VERSION 5.8 ;
BUSBITCHARS "[]" ;
DIVIDERCHAR "/" ;

PROPERTYDEFINITIONS
  MACRO CatenaDesignType STRING ;
  MACRO oaTaper STRING ;
END PROPERTYDEFINITIONS

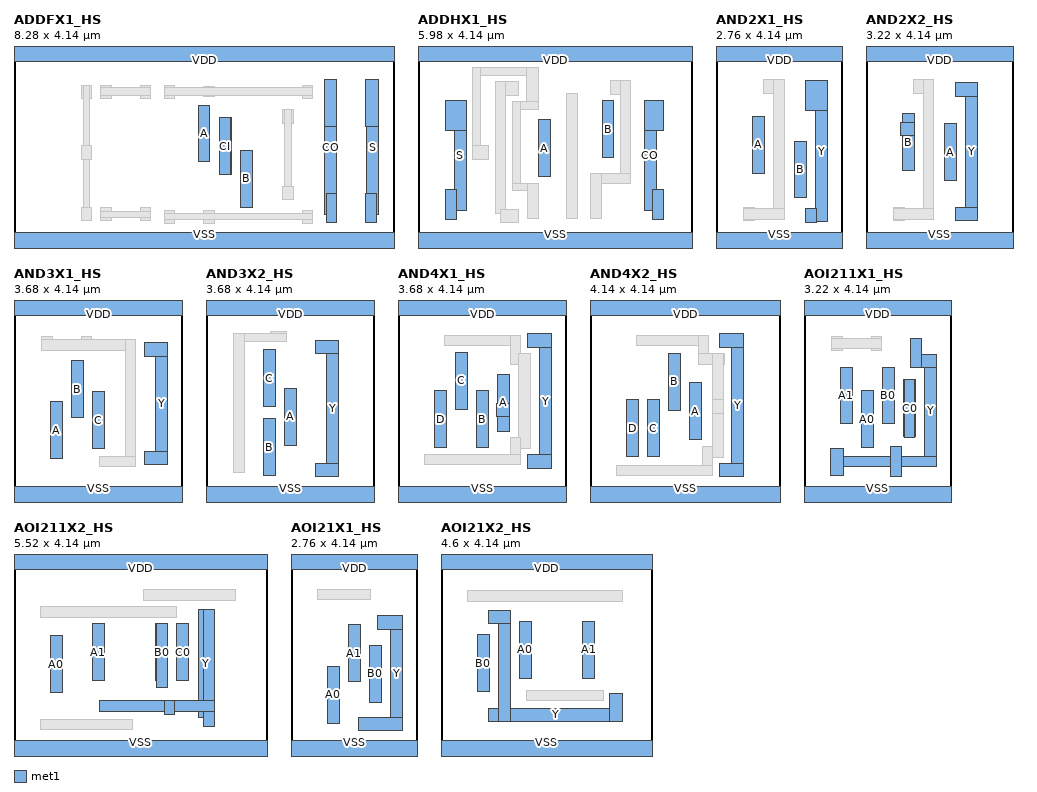
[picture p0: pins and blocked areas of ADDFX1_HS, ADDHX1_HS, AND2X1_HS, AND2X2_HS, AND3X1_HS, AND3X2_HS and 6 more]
MACRO ADDFX1_HS
  CLASS CORE ;
  ORIGIN 0 0 ;
  FOREIGN ADDFX1_HS 0 0 ;
  SIZE 8.28 BY 4.14 ;
  SYMMETRY X Y ;
  SITE CoreSite ;
  PIN A
    DIRECTION INPUT ;
    USE SIGNAL ;
    ANTENNAMODEL OXIDE1 ;
      ANTENNAGATEAREA 0.723 LAYER met1 ;
      ANTENNAMAXAREACAR 1.168603 LAYER met1 ;
      ANTENNAMAXSIDEAREACAR 1.233748 LAYER met1 ;
    PORT
      LAYER met1 ;
        RECT 4.01 1.745 4.27 2.985 ;
    END
  END A
  PIN B
    DIRECTION INPUT ;
    USE SIGNAL ;
    ANTENNAMODEL OXIDE1 ;
      ANTENNAGATEAREA 0.723 LAYER met1 ;
      ANTENNAMAXAREACAR 1.168603 LAYER met1 ;
      ANTENNAMAXSIDEAREACAR 1.233748 LAYER met1 ;
    PORT
      LAYER met1 ;
        RECT 4.93 0.76 5.19 2 ;
    END
  END B
  PIN CI
    DIRECTION INPUT ;
    USE SIGNAL ;
    ANTENNAMODEL OXIDE1 ;
      ANTENNAGATEAREA 0.54225 LAYER met1 ;
      ANTENNAMAXAREACAR 1.504841 LAYER met1 ;
      ANTENNAMAXSIDEAREACAR 1.644998 LAYER met1 ;
    PORT
      LAYER met1 ;
        RECT 4.47 1.47 4.73 2.71 ;
        RECT 4.485 1.465 4.715 2.71 ;
    END
  END CI
  PIN CO
    DIRECTION OUTPUT ;
    USE SIGNAL ;
    ANTENNADIFFAREA 0.5883 LAYER met1 ;
    PORT
      LAYER met1 ;
        RECT 6.77 2.52 7.035 3.53 ;
        RECT 6.805 0.415 7.035 1.065 ;
        RECT 6.77 0.61 7.03 3.53 ;
    END
  END CO
  PIN S
    DIRECTION OUTPUT ;
    USE SIGNAL ;
    ANTENNADIFFAREA 0.5883 LAYER met1 ;
    PORT
      LAYER met1 ;
        RECT 7.665 2.52 7.95 3.53 ;
        RECT 7.69 0.61 7.95 3.53 ;
        RECT 7.665 0.415 7.895 1.065 ;
    END
  END S
  PIN VDD
    DIRECTION INPUT ;
    USE POWER ;
    SHAPE ABUTMENT ;
    NETEXPR "VDD VDD!" ;
    PORT
      LAYER met1 ;
        RECT 0 3.94 8.28 4.34 ;
    END
  END VDD
  PIN VSS
    DIRECTION INPUT ;
    USE GROUND ;
    SHAPE ABUTMENT ;
    NETEXPR "VSS VSS!" ;
    PORT
      LAYER met1 ;
        RECT 0 -0.2 8.28 0.2 ;
    END
  END VSS
  OBS
    LAYER met1 ;
      RECT 6.285 0.405 6.515 0.695 ;
      RECT 4.135 0.405 4.365 0.695 ;
      RECT 3.275 0.405 3.505 0.695 ;
      RECT 3.275 0.48 6.515 0.62 ;
      RECT 6.285 3.13 6.515 3.42 ;
      RECT 3.275 3.13 3.505 3.42 ;
      RECT 4.135 3.16 4.365 3.39 ;
      RECT 3.275 3.19 6.515 3.36 ;
      RECT 5.855 2.59 6.085 2.88 ;
      RECT 5.9 0.93 6.04 2.88 ;
      RECT 5.855 0.93 6.085 1.22 ;
      RECT 2.755 0.46 2.985 0.75 ;
      RECT 1.895 0.46 2.125 0.75 ;
      RECT 1.895 0.535 2.985 0.675 ;
      RECT 2.755 3.13 2.985 3.42 ;
      RECT 1.895 3.13 2.125 3.42 ;
      RECT 1.895 3.19 2.985 3.36 ;
      RECT 1.465 3.13 1.695 3.42 ;
      RECT 1.51 0.46 1.65 3.42 ;
      RECT 1.465 1.805 1.695 2.095 ;
      RECT 1.465 0.46 1.695 0.75 ;
  END
  PROPERTY CatenaDesignType "deviceLevel" ;
END ADDFX1_HS

MACRO ADDHX1_HS
  CLASS CORE ;
  ORIGIN 0 0 ;
  FOREIGN ADDHX1_HS 0 0 ;
  SIZE 5.98 BY 4.14 ;
  SYMMETRY X Y ;
  SITE CoreSite ;
  PIN A
    DIRECTION INPUT ;
    USE SIGNAL ;
    ANTENNAMODEL OXIDE1 ;
      ANTENNAGATEAREA 0.3615 LAYER met1 ;
      ANTENNAMAXAREACAR 1.184509 LAYER met1 ;
      ANTENNAMAXSIDEAREACAR 1.289073 LAYER met1 ;
    PORT
      LAYER met1 ;
        RECT 2.63 1.425 2.89 2.665 ;
    END
  END A
  PIN B
    DIRECTION INPUT ;
    USE SIGNAL ;
    ANTENNAMODEL OXIDE1 ;
      ANTENNAGATEAREA 0.54225 LAYER met1 ;
      ANTENNAMAXAREACAR 0.858276 LAYER met1 ;
      ANTENNAMAXSIDEAREACAR 0.870447 LAYER met1 ;
    PORT
      LAYER met1 ;
        RECT 4.01 1.84 4.27 3.08 ;
        RECT 4.025 1.835 4.255 3.08 ;
    END
  END B
  PIN CO
    DIRECTION OUTPUT ;
    USE SIGNAL ;
    ANTENNADIFFAREA 0.5883 LAYER met1 ;
    PORT
      LAYER met1 ;
        RECT 4.93 2.44 5.345 3.09 ;
        RECT 5.115 0.485 5.345 1.135 ;
        RECT 4.93 0.68 5.19 3.09 ;
    END
  END CO
  PIN S
    DIRECTION OUTPUT ;
    USE SIGNAL ;
    ANTENNADIFFAREA 0.5883 LAYER met1 ;
    PORT
      LAYER met1 ;
        RECT 0.605 2.44 1.05 3.09 ;
        RECT 0.79 0.68 1.05 3.09 ;
        RECT 0.605 0.485 0.835 1.135 ;
    END
  END S
  PIN VDD
    DIRECTION INPUT ;
    USE POWER ;
    SHAPE ABUTMENT ;
    NETEXPR "VDD VDD!" ;
    PORT
      LAYER met1 ;
        RECT 0 3.94 5.98 4.34 ;
    END
  END VDD
  PIN VSS
    DIRECTION INPUT ;
    USE GROUND ;
    SHAPE ABUTMENT ;
    NETEXPR "VSS VSS!" ;
    PORT
      LAYER met1 ;
        RECT 0 -0.2 5.98 0.2 ;
    END
  END VSS
  OBS
    LAYER met1 ;
      RECT 4.195 3.22 4.64 3.51 ;
      RECT 4.41 1.265 4.64 3.51 ;
      RECT 3.765 1.265 4.64 1.495 ;
      RECT 3.765 0.51 3.995 1.495 ;
      RECT 1.19 3.63 2.615 3.8 ;
      RECT 2.355 2.89 2.615 3.8 ;
      RECT 1.19 1.805 1.36 3.8 ;
      RECT 2.065 2.89 2.615 3.06 ;
      RECT 2.065 1.115 2.235 3.06 ;
      RECT 1.19 1.805 1.54 2.095 ;
      RECT 2.065 1.115 2.615 1.285 ;
      RECT 2.385 0.51 2.615 1.285 ;
      RECT 1.68 3.2 2.185 3.49 ;
      RECT 1.68 0.615 1.91 3.49 ;
      RECT 1.795 0.42 2.185 0.71 ;
      RECT 3.245 0.51 3.475 3.235 ;
  END
  PROPERTY CatenaDesignType "deviceLevel" ;
END ADDHX1_HS

MACRO AND2X1_HS
  CLASS CORE ;
  ORIGIN 0 0 ;
  FOREIGN AND2X1_HS 0 0 ;
  SIZE 2.76 BY 4.14 ;
  SYMMETRY X Y ;
  SITE CoreSite ;
  PIN A
    DIRECTION INPUT ;
    USE SIGNAL ;
    ANTENNAMODEL OXIDE1 ;
      ANTENNAGATEAREA 0.18075 LAYER met1 ;
      ANTENNAMAXAREACAR 0.484371 LAYER met1 ;
      ANTENNAMAXSIDEAREACAR 0.569848 LAYER met1 ;
    PORT
      LAYER met1 ;
        RECT 0.79 1.5 1.05 2.74 ;
    END
  END A
  PIN B
    DIRECTION INPUT ;
    USE SIGNAL ;
    ANTENNAMODEL OXIDE1 ;
      ANTENNAGATEAREA 0.18075 LAYER met1 ;
      ANTENNAMAXAREACAR 0.917012 LAYER met1 ;
      ANTENNAMAXSIDEAREACAR 1.078838 LAYER met1 ;
    PORT
      LAYER met1 ;
        RECT 1.71 0.96 1.97 2.2 ;
    END
  END B
  PIN VDD
    DIRECTION INPUT ;
    USE POWER ;
    SHAPE ABUTMENT ;
    NETEXPR "VDD VDD!" ;
    PORT
      LAYER met1 ;
        RECT 0 3.94 2.76 4.34 ;
    END
  END VDD
  PIN VSS
    DIRECTION INPUT ;
    USE GROUND ;
    SHAPE ABUTMENT ;
    NETEXPR "VSS VSS!" ;
    PORT
      LAYER met1 ;
        RECT 0 -0.2 2.76 0.2 ;
    END
  END VSS
  PIN Y
    DIRECTION OUTPUT ;
    USE SIGNAL ;
    ANTENNADIFFAREA 0.5883 LAYER met1 ;
    PORT
      LAYER met1 ;
        RECT 1.955 2.86 2.43 3.51 ;
        RECT 2.17 0.44 2.43 3.51 ;
        RECT 1.955 0.43 2.185 0.72 ;
    END
  END Y
  OBS
    LAYER met1 ;
      RECT 1.035 3.24 1.49 3.53 ;
      RECT 1.26 0.49 1.49 3.53 ;
      RECT 0.605 0.46 0.835 0.75 ;
      RECT 0.605 0.49 1.49 0.72 ;
  END
  PROPERTY CatenaDesignType "deviceLevel" ;
END AND2X1_HS

MACRO AND2X2_HS
  CLASS CORE ;
  ORIGIN 0 0 ;
  FOREIGN AND2X2_HS 0 0 ;
  SIZE 3.22 BY 4.14 ;
  SYMMETRY X Y ;
  SITE CoreSite ;
  PIN A
    DIRECTION INPUT ;
    USE SIGNAL ;
    ANTENNAMODEL OXIDE1 ;
      ANTENNAGATEAREA 0.18075 LAYER met1 ;
      ANTENNAMAXAREACAR 0.935823 LAYER met1 ;
      ANTENNAMAXSIDEAREACAR 1.100968 LAYER met1 ;
    PORT
      LAYER met1 ;
        RECT 1.71 1.34 1.97 2.58 ;
    END
  END A
  PIN B
    DIRECTION INPUT ;
    USE SIGNAL ;
    ANTENNAMODEL OXIDE1 ;
      ANTENNAGATEAREA 0.18075 LAYER met1 ;
      ANTENNAMAXAREACAR 0.672476 LAYER met1 ;
      ANTENNAMAXSIDEAREACAR 0.791148 LAYER met1 ;
    PORT
      LAYER met1 ;
        RECT 0.79 1.55 1.05 2.79 ;
        RECT 0.745 2.31 1.05 2.6 ;
    END
  END B
  PIN VDD
    DIRECTION INPUT ;
    USE POWER ;
    SHAPE ABUTMENT ;
    NETEXPR "VDD VDD!" ;
    PORT
      LAYER met1 ;
        RECT 0 3.94 3.22 4.34 ;
    END
  END VDD
  PIN VSS
    DIRECTION INPUT ;
    USE GROUND ;
    SHAPE ABUTMENT ;
    NETEXPR "VSS VSS!" ;
    PORT
      LAYER met1 ;
        RECT 0 -0.2 3.22 0.2 ;
    END
  END VSS
  PIN Y
    DIRECTION OUTPUT ;
    USE SIGNAL ;
    ANTENNADIFFAREA 0.6216 LAYER met1 ;
    PORT
      LAYER met1 ;
        RECT 1.955 3.18 2.43 3.47 ;
        RECT 2.17 0.46 2.43 3.47 ;
        RECT 1.955 0.46 2.43 0.75 ;
    END
  END Y
  OBS
    LAYER met1 ;
      RECT 1.035 3.24 1.48 3.53 ;
      RECT 1.25 0.685 1.48 3.53 ;
      RECT 0.605 0.46 0.835 0.75 ;
      RECT 0.605 0.49 1.475 0.72 ;
  END
  PROPERTY CatenaDesignType "deviceLevel" ;
END AND2X2_HS

MACRO AND3X1_HS
  CLASS CORE ;
  ORIGIN 0 0 ;
  FOREIGN AND3X1_HS 0 0 ;
  SIZE 3.68 BY 4.14 ;
  SYMMETRY X Y ;
  SITE CoreSite ;
  PIN A
    DIRECTION INPUT ;
    USE SIGNAL ;
    ANTENNAMODEL OXIDE1 ;
      ANTENNAGATEAREA 0.18075 LAYER met1 ;
      ANTENNAMAXAREACAR 0.658368 LAYER met1 ;
      ANTENNAMAXSIDEAREACAR 0.77455 LAYER met1 ;
    PORT
      LAYER met1 ;
        RECT 0.79 0.815 1.05 2.055 ;
    END
  END A
  PIN B
    DIRECTION INPUT ;
    USE SIGNAL ;
    ANTENNAMODEL OXIDE1 ;
      ANTENNAGATEAREA 0.18075 LAYER met1 ;
      ANTENNAMAXAREACAR 0.691286 LAYER met1 ;
      ANTENNAMAXSIDEAREACAR 0.813278 LAYER met1 ;
    PORT
      LAYER met1 ;
        RECT 1.25 1.705 1.51 2.945 ;
    END
  END B
  PIN C
    DIRECTION INPUT ;
    USE SIGNAL ;
    ANTENNAMODEL OXIDE1 ;
      ANTENNAGATEAREA 0.18075 LAYER met1 ;
      ANTENNAMAXAREACAR 0.489073 LAYER met1 ;
      ANTENNAMAXSIDEAREACAR 0.57538 LAYER met1 ;
    PORT
      LAYER met1 ;
        RECT 1.71 1.03 1.97 2.27 ;
    END
  END C
  PIN VDD
    DIRECTION INPUT ;
    USE POWER ;
    SHAPE ABUTMENT ;
    NETEXPR "VDD VDD!" ;
    PORT
      LAYER met1 ;
        RECT 0 3.94 3.68 4.34 ;
    END
  END VDD
  PIN VSS
    DIRECTION INPUT ;
    USE GROUND ;
    SHAPE ABUTMENT ;
    NETEXPR "VSS VSS!" ;
    PORT
      LAYER met1 ;
        RECT 0 -0.2 3.68 0.2 ;
    END
  END VSS
  PIN Y
    DIRECTION OUTPUT ;
    USE SIGNAL ;
    ANTENNADIFFAREA 0.5883 LAYER met1 ;
    PORT
      LAYER met1 ;
        RECT 2.845 3.045 3.35 3.335 ;
        RECT 3.09 0.69 3.35 3.335 ;
        RECT 2.845 0.69 3.35 0.98 ;
    END
  END Y
  OBS
    LAYER met1 ;
      RECT 1.465 3.175 1.695 3.465 ;
      RECT 0.605 3.175 0.835 3.465 ;
      RECT 0.605 3.175 2.65 3.405 ;
      RECT 2.42 0.64 2.65 3.405 ;
      RECT 1.865 0.64 2.65 0.87 ;
  END
  PROPERTY CatenaDesignType "deviceLevel" ;
END AND3X1_HS

MACRO AND3X2_HS
  CLASS CORE ;
  ORIGIN 0 0 ;
  FOREIGN AND3X2_HS 0 0 ;
  SIZE 3.68 BY 4.14 ;
  SYMMETRY X Y ;
  SITE CoreSite ;
  PIN A
    DIRECTION INPUT ;
    USE SIGNAL ;
    ANTENNAMODEL OXIDE1 ;
      ANTENNAGATEAREA 0.18075 LAYER met1 ;
      ANTENNAMAXAREACAR 0.512586 LAYER met1 ;
      ANTENNAMAXSIDEAREACAR 0.603043 LAYER met1 ;
    PORT
      LAYER met1 ;
        RECT 1.71 1.105 1.97 2.345 ;
    END
  END A
  PIN B
    DIRECTION INPUT ;
    USE SIGNAL ;
    ANTENNAMODEL OXIDE1 ;
      ANTENNAGATEAREA 0.18075 LAYER met1 ;
      ANTENNAMAXAREACAR 0.470263 LAYER met1 ;
      ANTENNAMAXSIDEAREACAR 0.55325 LAYER met1 ;
    PORT
      LAYER met1 ;
        RECT 1.25 0.44 1.51 1.68 ;
    END
  END B
  PIN C
    DIRECTION INPUT ;
    USE SIGNAL ;
    ANTENNAMODEL OXIDE1 ;
      ANTENNAGATEAREA 0.18075 LAYER met1 ;
      ANTENNAMAXAREACAR 0.91231 LAYER met1 ;
      ANTENNAMAXSIDEAREACAR 1.073306 LAYER met1 ;
    PORT
      LAYER met1 ;
        RECT 1.25 1.945 1.51 3.185 ;
    END
  END C
  PIN VDD
    DIRECTION INPUT ;
    USE POWER ;
    SHAPE ABUTMENT ;
    NETEXPR "VDD VDD!" ;
    PORT
      LAYER met1 ;
        RECT 0 3.94 3.68 4.34 ;
    END
  END VDD
  PIN VSS
    DIRECTION INPUT ;
    USE GROUND ;
    SHAPE ABUTMENT ;
    NETEXPR "VSS VSS!" ;
    PORT
      LAYER met1 ;
        RECT 0 -0.2 3.68 0.2 ;
    END
  END VSS
  PIN Y
    DIRECTION OUTPUT ;
    USE SIGNAL ;
    ANTENNADIFFAREA 0.6216 LAYER met1 ;
    PORT
      LAYER met1 ;
        RECT 2.385 3.095 2.89 3.385 ;
        RECT 2.63 0.415 2.89 3.385 ;
        RECT 2.385 0.415 2.89 0.705 ;
    END
  END Y
  OBS
    LAYER met1 ;
      RECT 1.415 3.36 1.745 3.59 ;
      RECT 0.605 3.36 1.745 3.53 ;
      RECT 0.605 0.51 0.835 3.53 ;
  END
  PROPERTY CatenaDesignType "deviceLevel" ;
END AND3X2_HS

MACRO AND4X1_HS
  CLASS CORE ;
  ORIGIN 0 0 ;
  FOREIGN AND4X1_HS 0 0 ;
  SIZE 3.68 BY 4.14 ;
  SYMMETRY X Y ;
  SITE CoreSite ;
  PIN A
    DIRECTION INPUT ;
    USE SIGNAL ;
    ANTENNAMODEL OXIDE1 ;
      ANTENNAGATEAREA 0.18075 LAYER met1 ;
      ANTENNAMAXAREACAR 0.545505 LAYER met1 ;
      ANTENNAMAXSIDEAREACAR 0.64177 LAYER met1 ;
    PORT
      LAYER met1 ;
        RECT 2.17 1.41 2.43 2.65 ;
        RECT 2.14 1.73 2.43 2.02 ;
    END
  END A
  PIN B
    DIRECTION INPUT ;
    USE SIGNAL ;
    ANTENNAMODEL OXIDE1 ;
      ANTENNAGATEAREA 0.18075 LAYER met1 ;
      ANTENNAMAXAREACAR 0.5361 LAYER met1 ;
      ANTENNAMAXSIDEAREACAR 0.630705 LAYER met1 ;
    PORT
      LAYER met1 ;
        RECT 1.71 1.055 1.97 2.295 ;
    END
  END B
  PIN C
    DIRECTION INPUT ;
    USE SIGNAL ;
    ANTENNAMODEL OXIDE1 ;
      ANTENNAGATEAREA 0.18075 LAYER met1 ;
      ANTENNAMAXAREACAR 0.489073 LAYER met1 ;
      ANTENNAMAXSIDEAREACAR 0.57538 LAYER met1 ;
    PORT
      LAYER met1 ;
        RECT 1.25 1.89 1.51 3.13 ;
    END
  END C
  PIN D
    DIRECTION INPUT ;
    USE SIGNAL ;
    ANTENNAMODEL OXIDE1 ;
      ANTENNAGATEAREA 0.18075 LAYER met1 ;
      ANTENNAMAXAREACAR 0.484371 LAYER met1 ;
      ANTENNAMAXSIDEAREACAR 0.569848 LAYER met1 ;
    PORT
      LAYER met1 ;
        RECT 0.79 1.055 1.05 2.295 ;
    END
  END D
  PIN VDD
    DIRECTION INPUT ;
    USE POWER ;
    SHAPE ABUTMENT ;
    NETEXPR "VDD VDD!" ;
    PORT
      LAYER met1 ;
        RECT 0 3.94 3.68 4.34 ;
    END
  END VDD
  PIN VSS
    DIRECTION INPUT ;
    USE GROUND ;
    SHAPE ABUTMENT ;
    NETEXPR "VSS VSS!" ;
    PORT
      LAYER met1 ;
        RECT 0 -0.2 3.68 0.2 ;
    END
  END VSS
  PIN Y
    DIRECTION OUTPUT ;
    USE SIGNAL ;
    ANTENNADIFFAREA 0.5883 LAYER met1 ;
    PORT
      LAYER met1 ;
        RECT 2.815 3.24 3.35 3.53 ;
        RECT 3.09 0.61 3.35 3.53 ;
        RECT 2.815 0.61 3.35 0.9 ;
    END
  END Y
  OBS
    LAYER met1 ;
      RECT 1.005 3.27 2.675 3.5 ;
      RECT 2.445 2.87 2.675 3.5 ;
      RECT 2.63 1.04 2.89 3.1 ;
      RECT 2.445 0.685 2.675 1.27 ;
      RECT 0.575 0.685 2.675 0.915 ;
  END
  PROPERTY CatenaDesignType "deviceLevel" ;
END AND4X1_HS

MACRO AND4X2_HS
  CLASS CORE ;
  ORIGIN 0 0 ;
  FOREIGN AND4X2_HS 0 0 ;
  SIZE 4.14 BY 4.14 ;
  SYMMETRY X Y ;
  SITE CoreSite ;
  PIN A
    DIRECTION INPUT ;
    USE SIGNAL ;
    ANTENNAMODEL OXIDE1 ;
      ANTENNAGATEAREA 0.18075 LAYER met1 ;
      ANTENNAMAXAREACAR 0.757123 LAYER met1 ;
      ANTENNAMAXSIDEAREACAR 0.890733 LAYER met1 ;
    PORT
      LAYER met1 ;
        RECT 2.17 1.23 2.43 2.47 ;
    END
  END A
  PIN B
    DIRECTION INPUT ;
    USE SIGNAL ;
    ANTENNAMODEL OXIDE1 ;
      ANTENNAGATEAREA 0.18075 LAYER met1 ;
      ANTENNAMAXAREACAR 0.719502 LAYER met1 ;
      ANTENNAMAXSIDEAREACAR 0.846473 LAYER met1 ;
    PORT
      LAYER met1 ;
        RECT 1.71 1.865 1.97 3.105 ;
    END
  END B
  PIN C
    DIRECTION INPUT ;
    USE SIGNAL ;
    ANTENNAMODEL OXIDE1 ;
      ANTENNAGATEAREA 0.18075 LAYER met1 ;
      ANTENNAMAXAREACAR 0.681881 LAYER met1 ;
      ANTENNAMAXSIDEAREACAR 0.802213 LAYER met1 ;
    PORT
      LAYER met1 ;
        RECT 1.25 0.86 1.51 2.1 ;
    END
  END C
  PIN D
    DIRECTION INPUT ;
    USE SIGNAL ;
    ANTENNAMODEL OXIDE1 ;
      ANTENNAGATEAREA 0.18075 LAYER met1 ;
      ANTENNAMAXAREACAR 0.681881 LAYER met1 ;
      ANTENNAMAXSIDEAREACAR 0.802213 LAYER met1 ;
    PORT
      LAYER met1 ;
        RECT 0.79 0.86 1.05 2.1 ;
    END
  END D
  PIN VDD
    DIRECTION INPUT ;
    USE POWER ;
    SHAPE ABUTMENT ;
    NETEXPR "VDD VDD!" ;
    PORT
      LAYER met1 ;
        RECT 0 3.94 4.14 4.34 ;
    END
  END VDD
  PIN VSS
    DIRECTION INPUT ;
    USE GROUND ;
    SHAPE ABUTMENT ;
    NETEXPR "VSS VSS!" ;
    PORT
      LAYER met1 ;
        RECT 0 -0.2 4.14 0.2 ;
    END
  END VSS
  PIN Y
    DIRECTION OUTPUT ;
    USE SIGNAL ;
    ANTENNADIFFAREA 0.6216 LAYER met1 ;
    PORT
      LAYER met1 ;
        RECT 2.815 3.24 3.35 3.53 ;
        RECT 3.09 0.415 3.35 3.53 ;
        RECT 2.815 0.415 3.35 0.705 ;
    END
  END Y
  OBS
    LAYER met1 ;
      RECT 1.005 3.27 2.585 3.5 ;
      RECT 2.355 2.87 2.585 3.5 ;
      RECT 2.355 2.87 2.94 3.1 ;
      RECT 2.675 0.845 2.905 3.1 ;
      RECT 2.67 1.805 2.905 2.095 ;
      RECT 2.445 0.445 2.675 1.075 ;
      RECT 0.575 0.445 2.675 0.675 ;
  END
  PROPERTY CatenaDesignType "deviceLevel" ;
END AND4X2_HS

MACRO AOI211X1_HS
  CLASS CORE ;
  ORIGIN 0 0 ;
  FOREIGN AOI211X1_HS 0 0 ;
  SIZE 3.22 BY 4.14 ;
  SYMMETRY X Y ;
  SITE CoreSite ;
  PIN A0
    DIRECTION INPUT ;
    USE SIGNAL ;
    ANTENNAMODEL OXIDE1 ;
      ANTENNAGATEAREA 0.333 LAYER met1 ;
      ANTENNAMAXAREACAR 0.262913 LAYER met1 ;
      ANTENNAMAXSIDEAREACAR 0.309309 LAYER met1 ;
    PORT
      LAYER met1 ;
        RECT 1.25 1.05 1.51 2.29 ;
    END
  END A0
  PIN A1
    DIRECTION INPUT ;
    USE SIGNAL ;
    ANTENNAMODEL OXIDE1 ;
      ANTENNAGATEAREA 0.333 LAYER met1 ;
      ANTENNAMAXAREACAR 0.262913 LAYER met1 ;
      ANTENNAMAXSIDEAREACAR 0.309309 LAYER met1 ;
    PORT
      LAYER met1 ;
        RECT 0.79 1.57 1.05 2.81 ;
    END
  END A1
  PIN B0
    DIRECTION INPUT ;
    USE SIGNAL ;
    ANTENNAMODEL OXIDE1 ;
      ANTENNAGATEAREA 0.333 LAYER met1 ;
      ANTENNAMAXAREACAR 0.278228 LAYER met1 ;
      ANTENNAMAXSIDEAREACAR 0.327327 LAYER met1 ;
    PORT
      LAYER met1 ;
        RECT 1.71 1.57 1.97 2.81 ;
    END
  END B0
  PIN C0
    DIRECTION INPUT ;
    USE SIGNAL ;
    ANTENNAMODEL OXIDE1 ;
      ANTENNAGATEAREA 0.333 LAYER met1 ;
      ANTENNAMAXAREACAR 0.293544 LAYER met1 ;
      ANTENNAMAXSIDEAREACAR 0.345345 LAYER met1 ;
    PORT
      LAYER met1 ;
        RECT 2.17 1.29 2.43 2.53 ;
        RECT 2.185 1.285 2.415 2.53 ;
    END
  END C0
  PIN VDD
    DIRECTION INPUT ;
    USE POWER ;
    SHAPE ABUTMENT ;
    NETEXPR "VDD VDD!" ;
    PORT
      LAYER met1 ;
        RECT 0 3.94 3.22 4.34 ;
    END
  END VDD
  PIN VSS
    DIRECTION INPUT ;
    USE GROUND ;
    SHAPE ABUTMENT ;
    NETEXPR "VSS VSS!" ;
    PORT
      LAYER met1 ;
        RECT 0 -0.2 3.22 0.2 ;
    END
  END VSS
  PIN Y
    DIRECTION OUTPUT ;
    USE SIGNAL ;
    ANTENNADIFFAREA 0.8011 LAYER met1 ;
    PORT
      LAYER met1 ;
        RECT 2.33 2.79 2.89 3.08 ;
        RECT 2.63 0.64 2.89 3.08 ;
        RECT 0.575 0.64 2.89 0.87 ;
        RECT 2.33 2.79 2.56 3.44 ;
        RECT 1.895 0.43 2.125 1.08 ;
        RECT 0.575 0.445 0.865 1.035 ;
    END
  END Y
  OBS
    LAYER met1 ;
      RECT 1.465 3.18 1.695 3.47 ;
      RECT 0.605 3.18 0.835 3.47 ;
      RECT 0.605 3.21 1.695 3.44 ;
  END
  PROPERTY CatenaDesignType "deviceLevel" ;
END AOI211X1_HS

MACRO AOI211X2_HS
  CLASS CORE ;
  ORIGIN 0 0 ;
  FOREIGN AOI211X2_HS 0 0 ;
  SIZE 5.52 BY 4.14 ;
  SYMMETRY X Y ;
  SITE CoreSite ;
  PIN A0
    DIRECTION INPUT ;
    USE SIGNAL ;
    ANTENNAMODEL OXIDE1 ;
      ANTENNAGATEAREA 0.666 LAYER met1 ;
      ANTENNAMAXAREACAR 0.279505 LAYER met1 ;
      ANTENNAMAXSIDEAREACAR 0.277778 LAYER met1 ;
    PORT
      LAYER met1 ;
        RECT 0.79 1.25 1.05 2.49 ;
    END
  END A0
  PIN A1
    DIRECTION INPUT ;
    USE SIGNAL ;
    ANTENNAMODEL OXIDE1 ;
      ANTENNAGATEAREA 0.666 LAYER met1 ;
      ANTENNAMAXAREACAR 0.270571 LAYER met1 ;
      ANTENNAMAXSIDEAREACAR 0.267267 LAYER met1 ;
    PORT
      LAYER met1 ;
        RECT 1.71 1.51 1.97 2.75 ;
    END
  END A1
  PIN B0
    DIRECTION INPUT ;
    USE SIGNAL ;
    ANTENNAMODEL OXIDE1 ;
      ANTENNAGATEAREA 0.666 LAYER met1 ;
      ANTENNAMAXAREACAR 0.295345 LAYER met1 ;
      ANTENNAMAXSIDEAREACAR 0.282282 LAYER met1 ;
    PORT
      LAYER met1 ;
        RECT 3.09 1.51 3.35 2.75 ;
        RECT 3.105 1.37 3.335 2.75 ;
    END
  END B0
  PIN C0
    DIRECTION INPUT ;
    USE SIGNAL ;
    ANTENNAMODEL OXIDE1 ;
      ANTENNAGATEAREA 0.666 LAYER met1 ;
      ANTENNAMAXAREACAR 0.366291 LAYER met1 ;
      ANTENNAMAXSIDEAREACAR 0.37988 LAYER met1 ;
    PORT
      LAYER met1 ;
        RECT 3.55 1.51 3.81 2.75 ;
    END
  END C0
  PIN VDD
    DIRECTION INPUT ;
    USE POWER ;
    SHAPE ABUTMENT ;
    NETEXPR "VDD VDD!" ;
    PORT
      LAYER met1 ;
        RECT 0 3.94 5.52 4.34 ;
    END
  END VDD
  PIN VSS
    DIRECTION INPUT ;
    USE GROUND ;
    SHAPE ABUTMENT ;
    NETEXPR "VSS VSS!" ;
    PORT
      LAYER met1 ;
        RECT 0 -0.2 5.52 0.2 ;
    END
  END VSS
  PIN Y
    DIRECTION OUTPUT ;
    USE SIGNAL ;
    ANTENNADIFFAREA 1.0472 LAYER met1 ;
    PORT
      LAYER met1 ;
        RECT 4.01 0.7 4.365 3.07 ;
        RECT 4.135 0.505 4.365 3.07 ;
        RECT 1.865 0.84 4.365 1.07 ;
        RECT 3.275 0.775 3.505 1.07 ;
    END
  END Y
  OBS
    LAYER met1 ;
      RECT 2.815 3.26 4.825 3.49 ;
      RECT 0.57 2.89 3.535 3.12 ;
      RECT 0.57 0.445 2.58 0.675 ;
  END
  PROPERTY CatenaDesignType "deviceLevel" ;
END AOI211X2_HS

MACRO AOI21X1_HS
  CLASS CORE ;
  ORIGIN 0 0 ;
  FOREIGN AOI21X1_HS 0 0 ;
  SIZE 2.76 BY 4.14 ;
  SYMMETRY X Y ;
  SITE CoreSite ;
  PIN A0
    DIRECTION INPUT ;
    USE SIGNAL ;
    ANTENNAMODEL OXIDE1 ;
      ANTENNAGATEAREA 0.333 LAYER met1 ;
      ANTENNAMAXAREACAR 0.324174 LAYER met1 ;
      ANTENNAMAXSIDEAREACAR 0.381381 LAYER met1 ;
    PORT
      LAYER met1 ;
        RECT 0.79 0.58 1.05 1.82 ;
    END
  END A0
  PIN A1
    DIRECTION INPUT ;
    USE SIGNAL ;
    ANTENNAMODEL OXIDE1 ;
      ANTENNAGATEAREA 0.333 LAYER met1 ;
      ANTENNAMAXAREACAR 0.296096 LAYER met1 ;
      ANTENNAMAXSIDEAREACAR 0.348348 LAYER met1 ;
    PORT
      LAYER met1 ;
        RECT 1.25 1.49 1.51 2.73 ;
    END
  END A1
  PIN B0
    DIRECTION INPUT ;
    USE SIGNAL ;
    ANTENNAMODEL OXIDE1 ;
      ANTENNAGATEAREA 0.333 LAYER met1 ;
      ANTENNAMAXAREACAR 0.321622 LAYER met1 ;
      ANTENNAMAXSIDEAREACAR 0.378378 LAYER met1 ;
    PORT
      LAYER met1 ;
        RECT 1.71 1.04 1.97 2.28 ;
    END
  END B0
  PIN VDD
    DIRECTION INPUT ;
    USE POWER ;
    SHAPE ABUTMENT ;
    NETEXPR "VDD VDD!" ;
    PORT
      LAYER met1 ;
        RECT 0 3.94 2.76 4.34 ;
    END
  END VDD
  PIN VSS
    DIRECTION INPUT ;
    USE GROUND ;
    SHAPE ABUTMENT ;
    NETEXPR "VSS VSS!" ;
    PORT
      LAYER met1 ;
        RECT 0 -0.2 2.76 0.2 ;
    END
  END VSS
  PIN Y
    DIRECTION OUTPUT ;
    USE SIGNAL ;
    ANTENNADIFFAREA 0.5997 LAYER met1 ;
    PORT
      LAYER met1 ;
        RECT 1.895 2.635 2.43 2.925 ;
        RECT 2.17 0.415 2.43 2.925 ;
        RECT 1.465 0.415 2.43 0.705 ;
    END
  END Y
  OBS
    LAYER met1 ;
      RECT 0.575 3.27 1.725 3.5 ;
  END
  PROPERTY CatenaDesignType "deviceLevel" ;
END AOI21X1_HS

MACRO AOI21X2_HS
  CLASS CORE ;
  ORIGIN 0 0 ;
  FOREIGN AOI21X2_HS 0 0 ;
  SIZE 4.6 BY 4.14 ;
  SYMMETRY X Y ;
  SITE CoreSite ;
  PIN A0
    DIRECTION INPUT ;
    USE SIGNAL ;
    ANTENNAMODEL OXIDE1 ;
      ANTENNAGATEAREA 0.666 LAYER met1 ;
      ANTENNAMAXAREACAR 0.257808 LAYER met1 ;
      ANTENNAMAXSIDEAREACAR 0.252252 LAYER met1 ;
    PORT
      LAYER met1 ;
        RECT 1.71 1.565 1.97 2.805 ;
    END
  END A0
  PIN A1
    DIRECTION INPUT ;
    USE SIGNAL ;
    ANTENNAMODEL OXIDE1 ;
      ANTENNAGATEAREA 0.666 LAYER met1 ;
      ANTENNAMAXAREACAR 0.257808 LAYER met1 ;
      ANTENNAMAXSIDEAREACAR 0.252252 LAYER met1 ;
    PORT
      LAYER met1 ;
        RECT 3.09 1.56 3.35 2.8 ;
    END
  END A1
  PIN B0
    DIRECTION INPUT ;
    USE SIGNAL ;
    ANTENNAMODEL OXIDE1 ;
      ANTENNAGATEAREA 0.666 LAYER met1 ;
      ANTENNAMAXAREACAR 0.261637 LAYER met1 ;
      ANTENNAMAXSIDEAREACAR 0.256757 LAYER met1 ;
    PORT
      LAYER met1 ;
        RECT 0.79 1.27 1.05 2.51 ;
    END
  END B0
  PIN VDD
    DIRECTION INPUT ;
    USE POWER ;
    SHAPE ABUTMENT ;
    NETEXPR "VDD VDD!" ;
    PORT
      LAYER met1 ;
        RECT 0 3.94 4.6 4.34 ;
    END
  END VDD
  PIN VSS
    DIRECTION INPUT ;
    USE GROUND ;
    SHAPE ABUTMENT ;
    NETEXPR "VSS VSS!" ;
    PORT
      LAYER met1 ;
        RECT 0 -0.2 4.6 0.2 ;
    END
  END VSS
  PIN Y
    DIRECTION OUTPUT ;
    USE SIGNAL ;
    ANTENNADIFFAREA 1.0244 LAYER met1 ;
    PORT
      LAYER met1 ;
        RECT 3.675 0.625 3.965 1.23 ;
        RECT 1.035 0.625 3.965 0.915 ;
        RECT 1.035 2.755 1.51 3.045 ;
        RECT 1.25 0.625 1.51 3.045 ;
    END
  END Y
  OBS
    LAYER met1 ;
      RECT 0.575 3.24 3.965 3.47 ;
      RECT 1.865 1.07 3.53 1.3 ;
  END
  PROPERTY CatenaDesignType "deviceLevel" ;
END AOI21X2_HS

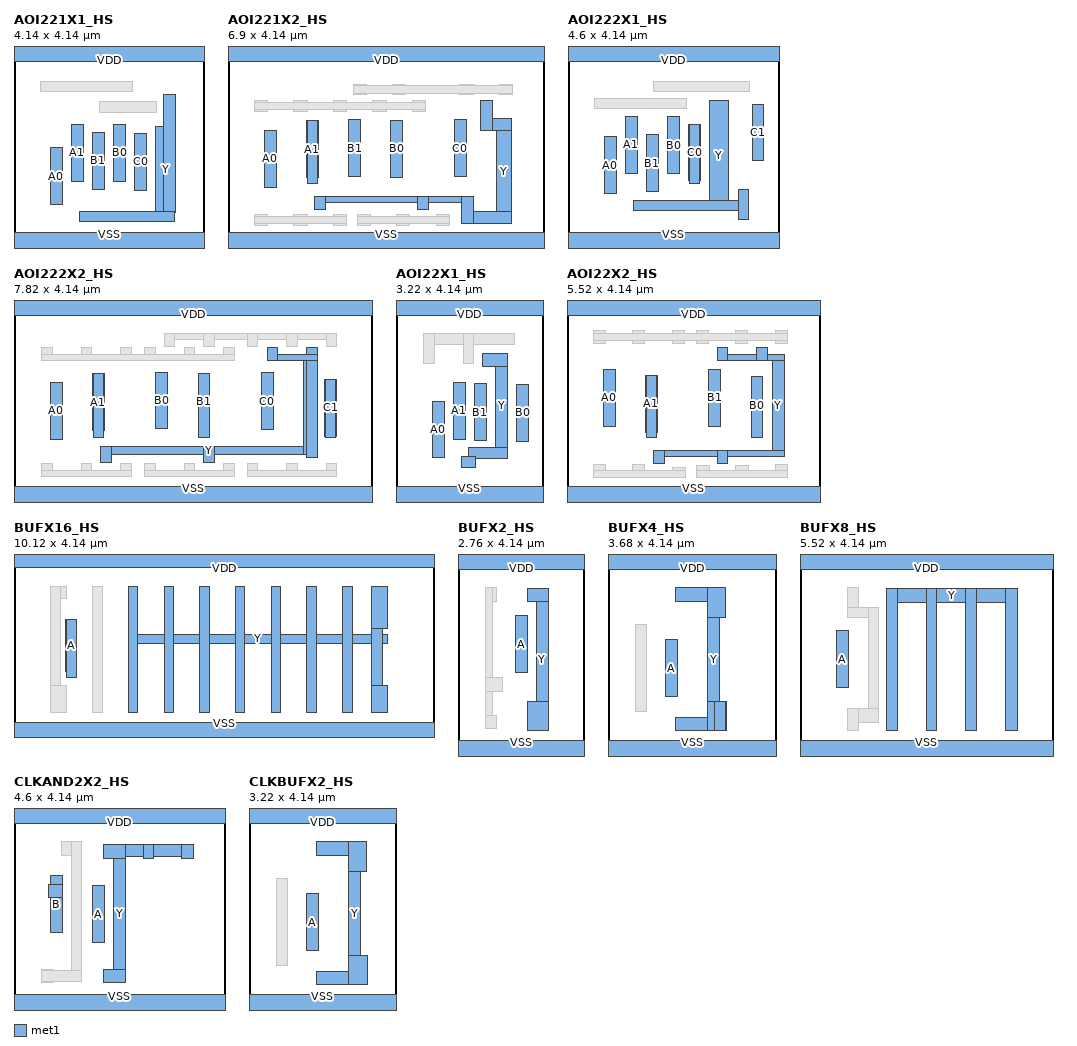
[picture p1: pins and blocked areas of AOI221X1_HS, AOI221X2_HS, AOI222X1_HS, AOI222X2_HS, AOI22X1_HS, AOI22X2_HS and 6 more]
MACRO AOI221X1_HS
  CLASS CORE ;
  ORIGIN 0 0 ;
  FOREIGN AOI221X1_HS 0 0 ;
  SIZE 4.14 BY 4.14 ;
  SYMMETRY X Y ;
  SITE CoreSite ;
  PIN A0
    DIRECTION INPUT ;
    USE SIGNAL ;
    ANTENNAMODEL OXIDE1 ;
      ANTENNAGATEAREA 0.333 LAYER met1 ;
      ANTENNAMAXAREACAR 0.37012 LAYER met1 ;
      ANTENNAMAXSIDEAREACAR 0.435435 LAYER met1 ;
    PORT
      LAYER met1 ;
        RECT 0.79 0.81 1.05 2.05 ;
    END
  END A0
  PIN A1
    DIRECTION INPUT ;
    USE SIGNAL ;
    ANTENNAMODEL OXIDE1 ;
      ANTENNAGATEAREA 0.333 LAYER met1 ;
      ANTENNAMAXAREACAR 0.37012 LAYER met1 ;
      ANTENNAMAXSIDEAREACAR 0.435435 LAYER met1 ;
    PORT
      LAYER met1 ;
        RECT 1.25 1.325 1.51 2.565 ;
    END
  END A1
  PIN B0
    DIRECTION INPUT ;
    USE SIGNAL ;
    ANTENNAMODEL OXIDE1 ;
      ANTENNAGATEAREA 0.333 LAYER met1 ;
      ANTENNAMAXAREACAR 0.37012 LAYER met1 ;
      ANTENNAMAXSIDEAREACAR 0.435435 LAYER met1 ;
    PORT
      LAYER met1 ;
        RECT 2.17 1.325 2.43 2.565 ;
    END
  END B0
  PIN B1
    DIRECTION INPUT ;
    USE SIGNAL ;
    ANTENNAMODEL OXIDE1 ;
      ANTENNAGATEAREA 0.333 LAYER met1 ;
      ANTENNAMAXAREACAR 0.37012 LAYER met1 ;
      ANTENNAMAXSIDEAREACAR 0.435435 LAYER met1 ;
    PORT
      LAYER met1 ;
        RECT 1.71 1.15 1.97 2.39 ;
    END
  END B1
  PIN C0
    DIRECTION INPUT ;
    USE SIGNAL ;
    ANTENNAMODEL OXIDE1 ;
      ANTENNAGATEAREA 0.333 LAYER met1 ;
      ANTENNAMAXAREACAR 0.46967 LAYER met1 ;
      ANTENNAMAXSIDEAREACAR 0.552553 LAYER met1 ;
    PORT
      LAYER met1 ;
        RECT 2.63 1.13 2.89 2.37 ;
    END
  END C0
  PIN VDD
    DIRECTION INPUT ;
    USE POWER ;
    SHAPE ABUTMENT ;
    NETEXPR "VDD VDD!" ;
    PORT
      LAYER met1 ;
        RECT 0 3.94 4.14 4.34 ;
    END
  END VDD
  PIN VSS
    DIRECTION INPUT ;
    USE GROUND ;
    SHAPE ABUTMENT ;
    NETEXPR "VSS VSS!" ;
    PORT
      LAYER met1 ;
        RECT 0 -0.2 4.14 0.2 ;
    END
  END VSS
  PIN Y
    DIRECTION OUTPUT ;
    USE SIGNAL ;
    ANTENNADIFFAREA 0.8011 LAYER met1 ;
    PORT
      LAYER met1 ;
        RECT 3.26 0.64 3.52 3.215 ;
        RECT 1.435 0.445 3.505 0.675 ;
        RECT 3.09 0.64 3.52 2.525 ;
    END
  END Y
  OBS
    LAYER met1 ;
      RECT 1.865 2.83 3.105 3.06 ;
      RECT 0.575 3.27 2.585 3.5 ;
  END
  PROPERTY CatenaDesignType "deviceLevel" ;
END AOI221X1_HS

MACRO AOI221X2_HS
  CLASS CORE ;
  ORIGIN 0 0 ;
  FOREIGN AOI221X2_HS 0 0 ;
  SIZE 6.9 BY 4.14 ;
  SYMMETRY X Y ;
  SITE CoreSite ;
  PIN A0
    DIRECTION INPUT ;
    USE SIGNAL ;
    ANTENNAMODEL OXIDE1 ;
      ANTENNAGATEAREA 0.666 LAYER met1 ;
      ANTENNAMAXAREACAR 0.32545 LAYER met1 ;
      ANTENNAMAXSIDEAREACAR 0.331832 LAYER met1 ;
    PORT
      LAYER met1 ;
        RECT 0.79 1.19 1.05 2.43 ;
    END
  END A0
  PIN A1
    DIRECTION INPUT ;
    USE SIGNAL ;
    ANTENNAMODEL OXIDE1 ;
      ANTENNAGATEAREA 0.666 LAYER met1 ;
      ANTENNAMAXAREACAR 0.32545 LAYER met1 ;
      ANTENNAMAXSIDEAREACAR 0.331832 LAYER met1 ;
    PORT
      LAYER met1 ;
        RECT 1.71 1.4 1.97 2.64 ;
        RECT 1.725 1.285 1.955 2.64 ;
    END
  END A1
  PIN B0
    DIRECTION INPUT ;
    USE SIGNAL ;
    ANTENNAMODEL OXIDE1 ;
      ANTENNAGATEAREA 0.666 LAYER met1 ;
      ANTENNAMAXAREACAR 0.169745 LAYER met1 ;
      ANTENNAMAXSIDEAREACAR 0.1997 LAYER met1 ;
    PORT
      LAYER met1 ;
        RECT 3.55 1.415 3.81 2.655 ;
    END
  END B0
  PIN B1
    DIRECTION INPUT ;
    USE SIGNAL ;
    ANTENNAMODEL OXIDE1 ;
      ANTENNAGATEAREA 0.666 LAYER met1 ;
      ANTENNAMAXAREACAR 0.154429 LAYER met1 ;
      ANTENNAMAXSIDEAREACAR 0.181682 LAYER met1 ;
    PORT
      LAYER met1 ;
        RECT 2.63 1.42 2.89 2.66 ;
    END
  END B1
  PIN C0
    DIRECTION INPUT ;
    USE SIGNAL ;
    ANTENNAMODEL OXIDE1 ;
      ANTENNAGATEAREA 0.666 LAYER met1 ;
      ANTENNAMAXAREACAR 0.361186 LAYER met1 ;
      ANTENNAMAXSIDEAREACAR 0.373874 LAYER met1 ;
    PORT
      LAYER met1 ;
        RECT 4.93 1.425 5.19 2.665 ;
    END
  END C0
  PIN VDD
    DIRECTION INPUT ;
    USE POWER ;
    SHAPE ABUTMENT ;
    NETEXPR "VDD VDD!" ;
    PORT
      LAYER met1 ;
        RECT 0 3.94 6.9 4.34 ;
    END
  END VDD
  PIN VSS
    DIRECTION INPUT ;
    USE GROUND ;
    SHAPE ABUTMENT ;
    NETEXPR "VSS VSS!" ;
    PORT
      LAYER met1 ;
        RECT 0 -0.2 6.9 0.2 ;
    END
  END VSS
  PIN Y
    DIRECTION OUTPUT ;
    USE SIGNAL ;
    ANTENNADIFFAREA 1.2372 LAYER met1 ;
    PORT
      LAYER met1 ;
        RECT 5.51 2.43 6.175 2.69 ;
        RECT 5.85 0.395 6.175 2.69 ;
        RECT 5.08 0.395 6.175 0.655 ;
        RECT 5.51 2.43 5.77 3.08 ;
        RECT 1.895 0.855 5.34 0.995 ;
        RECT 5.08 0.395 5.34 0.995 ;
        RECT 4.135 0.705 4.365 0.995 ;
        RECT 1.895 0.705 2.125 0.995 ;
    END
  END Y
  OBS
    LAYER met1 ;
      RECT 5.915 3.21 6.205 3.44 ;
      RECT 5.055 3.21 5.345 3.44 ;
      RECT 3.585 3.21 3.875 3.44 ;
      RECT 2.725 3.21 3.015 3.44 ;
      RECT 2.725 3.24 6.205 3.41 ;
      RECT 4.535 0.365 4.825 0.595 ;
      RECT 3.675 0.365 3.965 0.595 ;
      RECT 2.815 0.365 3.105 0.595 ;
      RECT 2.815 0.395 4.825 0.565 ;
      RECT 4.015 2.85 4.305 3.08 ;
      RECT 3.155 2.85 3.445 3.08 ;
      RECT 2.295 2.85 2.585 3.08 ;
      RECT 1.435 2.85 1.725 3.08 ;
      RECT 0.575 2.85 0.865 3.08 ;
      RECT 0.575 2.88 4.305 3.05 ;
      RECT 2.295 0.365 2.585 0.595 ;
      RECT 1.435 0.365 1.725 0.595 ;
      RECT 0.575 0.365 0.865 0.595 ;
      RECT 0.575 0.395 2.585 0.565 ;
  END
  PROPERTY CatenaDesignType "deviceLevel" ;
END AOI221X2_HS

MACRO AOI222X1_HS
  CLASS CORE ;
  ORIGIN 0 0 ;
  FOREIGN AOI222X1_HS 0 0 ;
  SIZE 4.6 BY 4.14 ;
  SYMMETRY X Y ;
  SITE CoreSite ;
  PIN A0
    DIRECTION INPUT ;
    USE SIGNAL ;
    ANTENNAMODEL OXIDE1 ;
      ANTENNAGATEAREA 0.333 LAYER met1 ;
      ANTENNAMAXAREACAR 0.321622 LAYER met1 ;
      ANTENNAMAXSIDEAREACAR 0.378378 LAYER met1 ;
    PORT
      LAYER met1 ;
        RECT 0.79 1.05 1.05 2.29 ;
    END
  END A0
  PIN A1
    DIRECTION INPUT ;
    USE SIGNAL ;
    ANTENNAMODEL OXIDE1 ;
      ANTENNAGATEAREA 0.333 LAYER met1 ;
      ANTENNAMAXAREACAR 0.321622 LAYER met1 ;
      ANTENNAMAXSIDEAREACAR 0.378378 LAYER met1 ;
    PORT
      LAYER met1 ;
        RECT 1.25 1.495 1.51 2.735 ;
    END
  END A1
  PIN B0
    DIRECTION INPUT ;
    USE SIGNAL ;
    ANTENNAMODEL OXIDE1 ;
      ANTENNAGATEAREA 0.333 LAYER met1 ;
      ANTENNAMAXAREACAR 0.410961 LAYER met1 ;
      ANTENNAMAXSIDEAREACAR 0.483483 LAYER met1 ;
    PORT
      LAYER met1 ;
        RECT 2.17 1.49 2.43 2.73 ;
    END
  END B0
  PIN B1
    DIRECTION INPUT ;
    USE SIGNAL ;
    ANTENNAMODEL OXIDE1 ;
      ANTENNAGATEAREA 0.333 LAYER met1 ;
      ANTENNAMAXAREACAR 0.321622 LAYER met1 ;
      ANTENNAMAXSIDEAREACAR 0.378378 LAYER met1 ;
    PORT
      LAYER met1 ;
        RECT 1.71 1.1 1.97 2.34 ;
    END
  END B1
  PIN C0
    DIRECTION INPUT ;
    USE SIGNAL ;
    ANTENNAMODEL OXIDE1 ;
      ANTENNAGATEAREA 0.333 LAYER met1 ;
      ANTENNAMAXAREACAR 0.446697 LAYER met1 ;
      ANTENNAMAXSIDEAREACAR 0.525526 LAYER met1 ;
    PORT
      LAYER met1 ;
        RECT 2.63 1.33 2.89 2.57 ;
        RECT 2.645 1.285 2.875 2.57 ;
    END
  END C0
  PIN C1
    DIRECTION INPUT ;
    USE SIGNAL ;
    ANTENNAMODEL OXIDE1 ;
      ANTENNAGATEAREA 0.333 LAYER met1 ;
      ANTENNAMAXAREACAR 0.507958 LAYER met1 ;
      ANTENNAMAXSIDEAREACAR 0.597598 LAYER met1 ;
    PORT
      LAYER met1 ;
        RECT 4.01 1.765 4.27 3.005 ;
    END
  END C1
  PIN VDD
    DIRECTION INPUT ;
    USE POWER ;
    SHAPE ABUTMENT ;
    NETEXPR "VDD VDD!" ;
    PORT
      LAYER met1 ;
        RECT 0 3.94 4.6 4.34 ;
    END
  END VDD
  PIN VSS
    DIRECTION INPUT ;
    USE GROUND ;
    SHAPE ABUTMENT ;
    NETEXPR "VSS VSS!" ;
    PORT
      LAYER met1 ;
        RECT 0 -0.2 4.6 0.2 ;
    END
  END VSS
  PIN Y
    DIRECTION OUTPUT ;
    USE SIGNAL ;
    ANTENNADIFFAREA 0.823 LAYER met1 ;
    PORT
      LAYER met1 ;
        RECT 3.705 0.485 3.935 1.135 ;
        RECT 1.435 0.68 3.935 0.91 ;
        RECT 3.09 0.68 3.505 3.09 ;
    END
  END Y
  OBS
    LAYER met1 ;
      RECT 1.865 3.27 3.965 3.5 ;
      RECT 0.575 2.9 2.585 3.13 ;
  END
  PROPERTY CatenaDesignType "deviceLevel" ;
END AOI222X1_HS

MACRO AOI222X2_HS
  CLASS CORE ;
  ORIGIN 0 0 ;
  FOREIGN AOI222X2_HS 0 0 ;
  SIZE 7.82 BY 4.14 ;
  SYMMETRY X Y ;
  SITE CoreSite ;
  PIN A0
    DIRECTION INPUT ;
    USE SIGNAL ;
    ANTENNAMODEL OXIDE1 ;
      ANTENNAGATEAREA 0.666 LAYER met1 ;
      ANTENNAMAXAREACAR 0.28461 LAYER met1 ;
      ANTENNAMAXSIDEAREACAR 0.283784 LAYER met1 ;
    PORT
      LAYER met1 ;
        RECT 0.79 1.24 1.05 2.48 ;
    END
  END A0
  PIN A1
    DIRECTION INPUT ;
    USE SIGNAL ;
    ANTENNAMODEL OXIDE1 ;
      ANTENNAGATEAREA 0.666 LAYER met1 ;
      ANTENNAMAXAREACAR 0.280781 LAYER met1 ;
      ANTENNAMAXSIDEAREACAR 0.279279 LAYER met1 ;
    PORT
      LAYER met1 ;
        RECT 1.71 1.42 1.97 2.66 ;
        RECT 1.725 1.285 1.955 2.66 ;
    END
  END A1
  PIN B0
    DIRECTION INPUT ;
    USE SIGNAL ;
    ANTENNAMODEL OXIDE1 ;
      ANTENNAGATEAREA 0.666 LAYER met1 ;
      ANTENNAMAXAREACAR 0.280781 LAYER met1 ;
      ANTENNAMAXSIDEAREACAR 0.279279 LAYER met1 ;
    PORT
      LAYER met1 ;
        RECT 3.09 1.46 3.35 2.7 ;
    END
  END B0
  PIN B1
    DIRECTION INPUT ;
    USE SIGNAL ;
    ANTENNAMODEL OXIDE1 ;
      ANTENNAGATEAREA 0.666 LAYER met1 ;
      ANTENNAMAXAREACAR 0.280781 LAYER met1 ;
      ANTENNAMAXSIDEAREACAR 0.279279 LAYER met1 ;
    PORT
      LAYER met1 ;
        RECT 4.01 1.43 4.27 2.67 ;
        RECT 4.025 1.285 4.255 2.67 ;
    END
  END B1
  PIN C0
    DIRECTION INPUT ;
    USE SIGNAL ;
    ANTENNAMODEL OXIDE1 ;
      ANTENNAGATEAREA 0.666 LAYER met1 ;
      ANTENNAMAXAREACAR 0.280781 LAYER met1 ;
      ANTENNAMAXSIDEAREACAR 0.279279 LAYER met1 ;
    PORT
      LAYER met1 ;
        RECT 5.39 1.445 5.65 2.685 ;
    END
  END C0
  PIN C1
    DIRECTION INPUT ;
    USE SIGNAL ;
    ANTENNAMODEL OXIDE1 ;
      ANTENNAGATEAREA 0.666 LAYER met1 ;
      ANTENNAMAXAREACAR 0.330556 LAYER met1 ;
      ANTENNAMAXSIDEAREACAR 0.337838 LAYER met1 ;
    PORT
      LAYER met1 ;
        RECT 6.77 1.305 7.03 2.545 ;
        RECT 6.785 1.285 7.015 2.545 ;
    END
  END C1
  PIN VDD
    DIRECTION INPUT ;
    USE POWER ;
    SHAPE ABUTMENT ;
    NETEXPR "VDD VDD!" ;
    PORT
      LAYER met1 ;
        RECT 0 3.94 7.82 4.34 ;
    END
  END VDD
  PIN VSS
    DIRECTION INPUT ;
    USE GROUND ;
    SHAPE ABUTMENT ;
    NETEXPR "VSS VSS!" ;
    PORT
      LAYER met1 ;
        RECT 0 -0.2 7.82 0.2 ;
    END
  END VSS
  PIN Y
    DIRECTION OUTPUT ;
    USE SIGNAL ;
    ANTENNADIFFAREA 1.456 LAYER met1 ;
    PORT
      LAYER met1 ;
        RECT 6.375 0.845 6.605 3.235 ;
        RECT 5.515 2.945 6.605 3.085 ;
        RECT 6.31 0.905 6.605 3.085 ;
        RECT 1.895 0.905 6.605 1.075 ;
        RECT 5.515 2.945 5.745 3.235 ;
        RECT 4.135 0.725 4.365 1.075 ;
        RECT 1.895 0.725 2.125 1.075 ;
    END
  END Y
  OBS
    LAYER met1 ;
      RECT 6.805 0.415 7.035 0.705 ;
      RECT 5.945 0.415 6.175 0.705 ;
      RECT 5.085 0.415 5.315 0.705 ;
      RECT 5.085 0.415 7.035 0.555 ;
      RECT 3.275 3.405 7.035 3.545 ;
      RECT 6.805 3.255 7.035 3.545 ;
      RECT 5.945 3.255 6.175 3.545 ;
      RECT 5.085 3.255 5.315 3.545 ;
      RECT 4.135 3.255 4.365 3.545 ;
      RECT 3.275 3.255 3.505 3.545 ;
      RECT 4.565 0.415 4.795 0.705 ;
      RECT 3.705 0.415 3.935 0.705 ;
      RECT 2.845 0.415 3.075 0.705 ;
      RECT 2.845 0.415 4.795 0.555 ;
      RECT 4.565 2.945 4.795 3.235 ;
      RECT 3.705 2.945 3.935 3.235 ;
      RECT 2.845 2.945 3.075 3.235 ;
      RECT 2.325 2.945 2.555 3.235 ;
      RECT 1.465 2.945 1.695 3.235 ;
      RECT 0.605 2.945 0.835 3.235 ;
      RECT 0.605 2.945 4.795 3.085 ;
      RECT 2.325 0.415 2.555 0.705 ;
      RECT 1.465 0.415 1.695 0.705 ;
      RECT 0.605 0.415 0.835 0.705 ;
      RECT 0.605 0.415 2.555 0.555 ;
  END
  PROPERTY CatenaDesignType "deviceLevel" ;
END AOI222X2_HS

MACRO AOI22X1_HS
  CLASS CORE ;
  ORIGIN 0 0 ;
  FOREIGN AOI22X1_HS 0 0 ;
  SIZE 3.22 BY 4.14 ;
  SYMMETRY X Y ;
  SITE CoreSite ;
  PIN A0
    DIRECTION INPUT ;
    USE SIGNAL ;
    ANTENNAMODEL OXIDE1 ;
      ANTENNAGATEAREA 0.333 LAYER met1 ;
      ANTENNAMAXAREACAR 0.3497 LAYER met1 ;
      ANTENNAMAXSIDEAREACAR 0.411411 LAYER met1 ;
    PORT
      LAYER met1 ;
        RECT 0.79 0.83 1.05 2.07 ;
    END
  END A0
  PIN A1
    DIRECTION INPUT ;
    USE SIGNAL ;
    ANTENNAMODEL OXIDE1 ;
      ANTENNAGATEAREA 0.333 LAYER met1 ;
      ANTENNAMAXAREACAR 0.38033 LAYER met1 ;
      ANTENNAMAXSIDEAREACAR 0.447447 LAYER met1 ;
    PORT
      LAYER met1 ;
        RECT 1.25 1.24 1.51 2.48 ;
    END
  END A1
  PIN B0
    DIRECTION INPUT ;
    USE SIGNAL ;
    ANTENNAMODEL OXIDE1 ;
      ANTENNAGATEAREA 0.333 LAYER met1 ;
      ANTENNAMAXAREACAR 0.515616 LAYER met1 ;
      ANTENNAMAXSIDEAREACAR 0.606607 LAYER met1 ;
    PORT
      LAYER met1 ;
        RECT 2.63 1.195 2.89 2.435 ;
    END
  END B0
  PIN B1
    DIRECTION INPUT ;
    USE SIGNAL ;
    ANTENNAMODEL OXIDE1 ;
      ANTENNAGATEAREA 0.333 LAYER met1 ;
      ANTENNAMAXAREACAR 0.367568 LAYER met1 ;
      ANTENNAMAXSIDEAREACAR 0.432432 LAYER met1 ;
    PORT
      LAYER met1 ;
        RECT 1.71 1.205 1.97 2.445 ;
    END
  END B1
  PIN VDD
    DIRECTION INPUT ;
    USE POWER ;
    SHAPE ABUTMENT ;
    NETEXPR "VDD VDD!" ;
    PORT
      LAYER met1 ;
        RECT 0 3.94 3.22 4.34 ;
    END
  END VDD
  PIN VSS
    DIRECTION INPUT ;
    USE GROUND ;
    SHAPE ABUTMENT ;
    NETEXPR "VSS VSS!" ;
    PORT
      LAYER met1 ;
        RECT 0 -0.2 3.22 0.2 ;
    END
  END VSS
  PIN Y
    DIRECTION OUTPUT ;
    USE SIGNAL ;
    ANTENNADIFFAREA 0.6216 LAYER met1 ;
    PORT
      LAYER met1 ;
        RECT 1.895 2.82 2.43 3.11 ;
        RECT 2.17 0.82 2.43 3.11 ;
        RECT 1.58 0.82 2.43 1.05 ;
        RECT 1.435 0.625 1.725 0.855 ;
    END
  END Y
  OBS
    LAYER met1 ;
      RECT 0.605 3.3 2.585 3.53 ;
      RECT 1.465 2.88 1.695 3.53 ;
      RECT 0.605 2.88 0.835 3.53 ;
  END
  PROPERTY CatenaDesignType "deviceLevel" ;
END AOI22X1_HS

MACRO AOI22X2_HS
  CLASS CORE ;
  ORIGIN 0 0 ;
  FOREIGN AOI22X2_HS 0 0 ;
  SIZE 5.52 BY 4.14 ;
  SYMMETRY X Y ;
  SITE CoreSite ;
  PIN A0
    DIRECTION INPUT ;
    USE SIGNAL ;
    ANTENNAMODEL OXIDE1 ;
      ANTENNAGATEAREA 0.666 LAYER met1 ;
      ANTENNAMAXAREACAR 0.32545 LAYER met1 ;
      ANTENNAMAXSIDEAREACAR 0.331832 LAYER met1 ;
    PORT
      LAYER met1 ;
        RECT 0.79 1.52 1.05 2.76 ;
    END
  END A0
  PIN A1
    DIRECTION INPUT ;
    USE SIGNAL ;
    ANTENNAMODEL OXIDE1 ;
      ANTENNAGATEAREA 0.666 LAYER met1 ;
      ANTENNAMAXAREACAR 0.32545 LAYER met1 ;
      ANTENNAMAXSIDEAREACAR 0.331832 LAYER met1 ;
    PORT
      LAYER met1 ;
        RECT 1.71 1.39 1.97 2.63 ;
        RECT 1.725 1.285 1.955 2.63 ;
    END
  END A1
  PIN B0
    DIRECTION INPUT ;
    USE SIGNAL ;
    ANTENNAMODEL OXIDE1 ;
      ANTENNAGATEAREA 0.666 LAYER met1 ;
      ANTENNAMAXAREACAR 0.32545 LAYER met1 ;
      ANTENNAMAXSIDEAREACAR 0.331832 LAYER met1 ;
    PORT
      LAYER met1 ;
        RECT 4.01 1.355 4.27 2.595 ;
        RECT 4.025 1.285 4.255 2.595 ;
    END
  END B0
  PIN B1
    DIRECTION INPUT ;
    USE SIGNAL ;
    ANTENNAMODEL OXIDE1 ;
      ANTENNAGATEAREA 0.666 LAYER met1 ;
      ANTENNAMAXAREACAR 0.32545 LAYER met1 ;
      ANTENNAMAXSIDEAREACAR 0.331832 LAYER met1 ;
    PORT
      LAYER met1 ;
        RECT 3.09 1.52 3.35 2.76 ;
    END
  END B1
  PIN VDD
    DIRECTION INPUT ;
    USE POWER ;
    SHAPE ABUTMENT ;
    NETEXPR "VDD VDD!" ;
    PORT
      LAYER met1 ;
        RECT 0 3.94 5.52 4.34 ;
    END
  END VDD
  PIN VSS
    DIRECTION INPUT ;
    USE GROUND ;
    SHAPE ABUTMENT ;
    NETEXPR "VSS VSS!" ;
    PORT
      LAYER met1 ;
        RECT 0 -0.2 5.52 0.2 ;
    END
  END VSS
  PIN Y
    DIRECTION OUTPUT ;
    USE SIGNAL ;
    ANTENNADIFFAREA 1.2432 LAYER met1 ;
    PORT
      LAYER met1 ;
        RECT 3.275 2.95 4.73 3.09 ;
        RECT 4.47 0.85 4.73 3.09 ;
        RECT 1.895 0.855 4.73 0.995 ;
        RECT 4.135 2.95 4.365 3.24 ;
        RECT 3.275 2.95 3.505 3.24 ;
        RECT 3.275 0.705 3.505 0.995 ;
        RECT 1.895 0.705 2.125 0.995 ;
    END
  END Y
  OBS
    LAYER met1 ;
      RECT 4.535 0.395 4.795 0.685 ;
      RECT 3.675 0.395 3.965 0.655 ;
      RECT 2.815 0.395 3.105 0.655 ;
      RECT 2.815 0.395 4.795 0.565 ;
      RECT 4.535 3.32 4.795 3.61 ;
      RECT 3.675 3.32 3.935 3.61 ;
      RECT 2.815 3.32 3.075 3.61 ;
      RECT 2.295 3.32 2.555 3.61 ;
      RECT 1.435 3.32 1.695 3.61 ;
      RECT 0.575 3.32 0.835 3.61 ;
      RECT 0.575 3.38 4.795 3.55 ;
      RECT 1.435 0.395 1.695 0.685 ;
      RECT 0.575 0.395 0.835 0.685 ;
      RECT 2.295 0.395 2.585 0.625 ;
      RECT 0.575 0.395 2.585 0.565 ;
  END
  PROPERTY CatenaDesignType "deviceLevel" ;
END AOI22X2_HS

MACRO BUFX16_HS
  CLASS CORE ;
  ORIGIN 0 0 ;
  FOREIGN BUFX16_HS 0 0 ;
  SIZE 10.12 BY 4.14 ;
  SYMMETRY X Y ;
  SITE CoreSite ;
  PIN A
    DIRECTION INPUT ;
    USE SIGNAL ;
    ANTENNAMODEL OXIDE1 ;
      ANTENNAGATEAREA 1.332 LAYER met1 ;
      ANTENNAMAXAREACAR 0.216967 LAYER met1 ;
      ANTENNAMAXSIDEAREACAR 0.204204 LAYER met1 ;
    PORT
      LAYER met1 ;
        RECT 1.25 1.435 1.51 2.675 ;
        RECT 1.265 1.285 1.495 2.675 ;
    END
  END A
  PIN VDD
    DIRECTION INPUT ;
    USE POWER ;
    SHAPE ABUTMENT ;
    NETEXPR "VDD VDD!" ;
    PORT
      LAYER met1 ;
        RECT 0 3.94 10.12 4.34 ;
    END
  END VDD
  PIN VSS
    DIRECTION INPUT ;
    USE GROUND ;
    SHAPE ABUTMENT ;
    NETEXPR "VSS VSS!" ;
    PORT
      LAYER met1 ;
        RECT 0 -0.2 10.12 0.2 ;
    END
  END VSS
  PIN Y
    DIRECTION OUTPUT ;
    USE SIGNAL ;
    ANTENNADIFFAREA 4.9728 LAYER met1 ;
    PORT
      LAYER met1 ;
        RECT 8.61 2.48 9.005 3.49 ;
        RECT 2.755 2.105 9.005 2.335 ;
        RECT 8.61 0.45 9.005 1.1 ;
        RECT 8.61 0.45 8.87 3.49 ;
        RECT 7.915 0.45 8.145 3.49 ;
        RECT 7.055 0.45 7.285 3.49 ;
        RECT 6.195 0.45 6.425 3.49 ;
        RECT 5.335 0.45 5.565 3.49 ;
        RECT 4.475 0.45 4.705 3.49 ;
        RECT 3.615 0.45 3.845 3.49 ;
        RECT 2.755 0.45 2.985 3.49 ;
    END
  END Y
  OBS
    LAYER met1 ;
      RECT 0.88 3.2 1.265 3.49 ;
      RECT 0.88 0.45 1.11 3.49 ;
      RECT 0.88 0.45 1.265 1.1 ;
      RECT 1.895 0.45 2.125 3.49 ;
  END
  PROPERTY CatenaDesignType "deviceLevel" ;
END BUFX16_HS

MACRO BUFX2_HS
  CLASS CORE ;
  ORIGIN 0 0 ;
  FOREIGN BUFX2_HS 0 0 ;
  SIZE 2.76 BY 4.14 ;
  SYMMETRY X Y ;
  SITE CoreSite ;
  PIN A
    DIRECTION INPUT ;
    USE SIGNAL ;
    ANTENNAMODEL OXIDE1 ;
      ANTENNAGATEAREA 0.18075 LAYER met1 ;
      ANTENNAMAXAREACAR 0.827663 LAYER met1 ;
      ANTENNAMAXSIDEAREACAR 0.973721 LAYER met1 ;
    PORT
      LAYER met1 ;
        RECT 1.25 1.685 1.51 2.925 ;
    END
  END A
  PIN VDD
    DIRECTION INPUT ;
    USE POWER ;
    SHAPE ABUTMENT ;
    NETEXPR "VDD VDD!" ;
    PORT
      LAYER met1 ;
        RECT 0 3.94 2.76 4.34 ;
    END
  END VDD
  PIN VSS
    DIRECTION INPUT ;
    USE GROUND ;
    SHAPE ABUTMENT ;
    NETEXPR "VSS VSS!" ;
    PORT
      LAYER met1 ;
        RECT 0 -0.2 2.76 0.2 ;
    END
  END VSS
  PIN Y
    DIRECTION OUTPUT ;
    USE SIGNAL ;
    ANTENNADIFFAREA 0.6216 LAYER met1 ;
    PORT
      LAYER met1 ;
        RECT 1.525 3.23 1.97 3.52 ;
        RECT 1.71 0.415 1.97 3.52 ;
        RECT 1.525 0.415 1.97 1.065 ;
    END
  END Y
  OBS
    LAYER met1 ;
      RECT 0.605 3.24 0.835 3.53 ;
      RECT 0.605 0.46 0.745 3.53 ;
      RECT 0.605 1.285 0.975 1.575 ;
      RECT 0.605 0.46 0.835 0.75 ;
  END
  PROPERTY CatenaDesignType "deviceLevel" ;
END BUFX2_HS

MACRO BUFX4_HS
  CLASS CORE ;
  ORIGIN 0 0 ;
  FOREIGN BUFX4_HS 0 0 ;
  SIZE 3.68 BY 4.14 ;
  SYMMETRY X Y ;
  SITE CoreSite ;
  PIN A
    DIRECTION INPUT ;
    USE SIGNAL ;
    ANTENNAMODEL OXIDE1 ;
      ANTENNAGATEAREA 0.333 LAYER met1 ;
      ANTENNAMAXAREACAR 0.523273 LAYER met1 ;
      ANTENNAMAXSIDEAREACAR 0.615616 LAYER met1 ;
    PORT
      LAYER met1 ;
        RECT 1.25 1.165 1.51 2.405 ;
    END
  END A
  PIN VDD
    DIRECTION INPUT ;
    USE POWER ;
    SHAPE ABUTMENT ;
    NETEXPR "VDD VDD!" ;
    PORT
      LAYER met1 ;
        RECT 0 3.94 3.68 4.34 ;
    END
  END VDD
  PIN VSS
    DIRECTION INPUT ;
    USE GROUND ;
    SHAPE ABUTMENT ;
    NETEXPR "VSS VSS!" ;
    PORT
      LAYER met1 ;
        RECT 0 -0.2 3.68 0.2 ;
    END
  END VSS
  PIN Y
    DIRECTION OUTPUT ;
    USE SIGNAL ;
    ANTENNADIFFAREA 1.2432 LAYER met1 ;
    PORT
      LAYER met1 ;
        RECT 2.17 0.42 2.585 1.065 ;
        RECT 1.465 3.24 2.555 3.53 ;
        RECT 2.17 2.88 2.555 3.53 ;
        RECT 2.325 0.415 2.555 1.065 ;
        RECT 2.17 0.42 2.43 3.53 ;
        RECT 1.465 0.42 2.585 0.71 ;
    END
  END Y
  OBS
    LAYER met1 ;
      RECT 0.605 0.845 0.835 2.73 ;
  END
  PROPERTY CatenaDesignType "deviceLevel" ;
END BUFX4_HS

MACRO BUFX8_HS
  CLASS CORE ;
  ORIGIN 0 0 ;
  FOREIGN BUFX8_HS 0 0 ;
  SIZE 5.52 BY 4.14 ;
  SYMMETRY X Y ;
  SITE CoreSite ;
  PIN A
    DIRECTION INPUT ;
    USE SIGNAL ;
    ANTENNAMODEL OXIDE1 ;
      ANTENNAGATEAREA 0.666 LAYER met1 ;
      ANTENNAMAXAREACAR 0.307583 LAYER met1 ;
      ANTENNAMAXSIDEAREACAR 0.310811 LAYER met1 ;
    PORT
      LAYER met1 ;
        RECT 0.79 1.355 1.05 2.595 ;
    END
  END A
  PIN VDD
    DIRECTION INPUT ;
    USE POWER ;
    SHAPE ABUTMENT ;
    NETEXPR "VDD VDD!" ;
    PORT
      LAYER met1 ;
        RECT 0 3.94 5.52 4.34 ;
    END
  END VDD
  PIN VSS
    DIRECTION INPUT ;
    USE GROUND ;
    SHAPE ABUTMENT ;
    NETEXPR "VSS VSS!" ;
    PORT
      LAYER met1 ;
        RECT 0 -0.2 5.52 0.2 ;
    END
  END VSS
  PIN Y
    DIRECTION OUTPUT ;
    USE SIGNAL ;
    ANTENNADIFFAREA 2.4864 LAYER met1 ;
    PORT
      LAYER met1 ;
        RECT 1.895 3.22 4.73 3.51 ;
        RECT 4.47 0.43 4.73 3.51 ;
        RECT 3.615 0.43 3.845 3.51 ;
        RECT 2.755 0.43 2.985 3.51 ;
        RECT 1.895 0.435 2.125 3.51 ;
    END
  END Y
  OBS
    LAYER met1 ;
      RECT 1.035 2.88 1.265 3.53 ;
      RECT 1.035 2.88 1.72 3.11 ;
      RECT 1.49 0.61 1.72 3.11 ;
      RECT 1.035 0.61 1.72 0.9 ;
      RECT 1.035 0.415 1.265 0.9 ;
  END
  PROPERTY CatenaDesignType "deviceLevel" ;
END BUFX8_HS

MACRO CLKAND2X2_HS
  CLASS CORE ;
  ORIGIN 0 0 ;
  FOREIGN CLKAND2X2_HS 0 0 ;
  SIZE 4.6 BY 4.14 ;
  SYMMETRY X Y ;
  SITE CoreSite ;
  PIN A
    DIRECTION INPUT ;
    USE SIGNAL ;
    ANTENNAMODEL OXIDE1 ;
      ANTENNAGATEAREA 0.18075 LAYER met1 ;
      ANTENNAMAXAREACAR 0.935823 LAYER met1 ;
      ANTENNAMAXSIDEAREACAR 1.100968 LAYER met1 ;
    PORT
      LAYER met1 ;
        RECT 1.71 1.34 1.97 2.58 ;
    END
  END A
  PIN B
    DIRECTION INPUT ;
    USE SIGNAL ;
    ANTENNAMODEL OXIDE1 ;
      ANTENNAGATEAREA 0.18075 LAYER met1 ;
      ANTENNAMAXAREACAR 0.672476 LAYER met1 ;
      ANTENNAMAXSIDEAREACAR 0.791148 LAYER met1 ;
    PORT
      LAYER met1 ;
        RECT 0.79 1.55 1.05 2.79 ;
        RECT 0.745 2.31 1.05 2.6 ;
    END
  END B
  PIN VDD
    DIRECTION INPUT ;
    USE POWER ;
    SHAPE ABUTMENT ;
    NETEXPR "VDD VDD!" ;
    PORT
      LAYER met1 ;
        RECT 0 3.94 4.6 4.34 ;
    END
  END VDD
  PIN VSS
    DIRECTION INPUT ;
    USE GROUND ;
    SHAPE ABUTMENT ;
    NETEXPR "VSS VSS!" ;
    PORT
      LAYER met1 ;
        RECT 0 -0.2 4.6 0.2 ;
    END
  END VSS
  PIN Y
    DIRECTION OUTPUT ;
    USE SIGNAL ;
    ANTENNADIFFAREA 1.4392 LAYER met1 ;
    PORT
      LAYER met1 ;
        RECT 1.955 3.21 3.92 3.47 ;
        RECT 3.66 3.18 3.92 3.47 ;
        RECT 2.815 3.18 3.045 3.47 ;
        RECT 1.955 3.18 2.43 3.47 ;
        RECT 2.17 0.46 2.43 3.47 ;
        RECT 1.955 0.46 2.43 0.75 ;
    END
  END Y
  OBS
    LAYER met1 ;
      RECT 1.035 3.24 1.48 3.53 ;
      RECT 1.25 0.685 1.48 3.53 ;
      RECT 0.605 0.46 0.835 0.75 ;
      RECT 0.605 0.49 1.475 0.72 ;
  END
  PROPERTY CatenaDesignType "deviceLevel" ;
END CLKAND2X2_HS

MACRO CLKBUFX2_HS
  CLASS CORE ;
  ORIGIN 0 0 ;
  FOREIGN CLKBUFX2_HS 0 0 ;
  SIZE 3.22 BY 4.14 ;
  SYMMETRY X Y ;
  SITE CoreSite ;
  PIN A
    DIRECTION INPUT ;
    USE SIGNAL ;
    ANTENNAMODEL OXIDE1 ;
      ANTENNAGATEAREA 0.273 LAYER met1 ;
      ANTENNAMAXAREACAR 0.638278 LAYER met1 ;
      ANTENNAMAXSIDEAREACAR 0.750916 LAYER met1 ;
    PORT
      LAYER met1 ;
        RECT 1.25 1.165 1.51 2.405 ;
    END
  END A
  PIN VDD
    DIRECTION INPUT ;
    USE POWER ;
    SHAPE ABUTMENT ;
    NETEXPR "VDD VDD!" ;
    PORT
      LAYER met1 ;
        RECT 0 3.94 3.22 4.34 ;
    END
  END VDD
  PIN VSS
    DIRECTION INPUT ;
    USE GROUND ;
    SHAPE ABUTMENT ;
    NETEXPR "VSS VSS!" ;
    PORT
      LAYER met1 ;
        RECT 0 -0.2 3.22 0.2 ;
    END
  END VSS
  PIN Y
    DIRECTION OUTPUT ;
    USE SIGNAL ;
    ANTENNADIFFAREA 0.8064 LAYER met1 ;
    PORT
      LAYER met1 ;
        RECT 2.17 0.42 2.585 1.065 ;
        RECT 1.465 3.24 2.555 3.53 ;
        RECT 2.17 2.88 2.555 3.53 ;
        RECT 2.17 0.42 2.43 3.53 ;
        RECT 1.465 0.42 2.585 0.71 ;
    END
  END Y
  OBS
    LAYER met1 ;
      RECT 0.605 0.845 0.835 2.73 ;
  END
  PROPERTY CatenaDesignType "deviceLevel" ;
END CLKBUFX2_HS

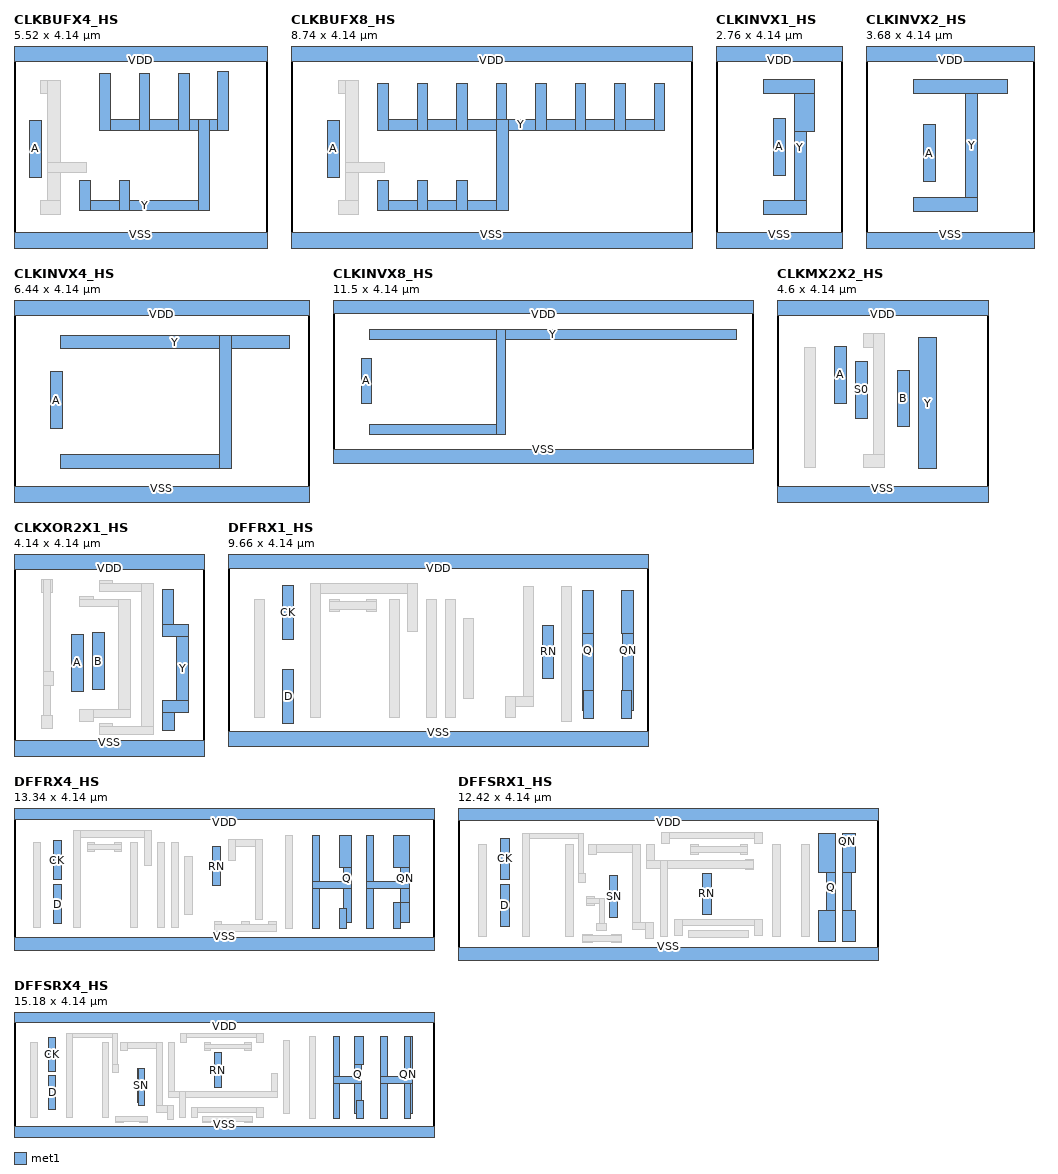
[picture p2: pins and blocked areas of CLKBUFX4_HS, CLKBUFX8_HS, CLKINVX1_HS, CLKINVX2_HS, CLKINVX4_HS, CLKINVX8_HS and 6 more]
MACRO CLKBUFX4_HS
  CLASS CORE ;
  ORIGIN 0 0 ;
  FOREIGN CLKBUFX4_HS 0 0 ;
  SIZE 5.52 BY 4.14 ;
  SYMMETRY X Y ;
  SITE CoreSite ;
  PIN A
    DIRECTION INPUT ;
    USE SIGNAL ;
    ANTENNAMODEL OXIDE1 ;
      ANTENNAGATEAREA 0.333 LAYER met1 ;
      ANTENNAMAXAREACAR 0.574324 LAYER met1 ;
      ANTENNAMAXSIDEAREACAR 0.573574 LAYER met1 ;
    PORT
      LAYER met1 ;
        RECT 0.33 1.415 0.59 2.655 ;
    END
  END A
  PIN VDD
    DIRECTION INPUT ;
    USE POWER ;
    SHAPE ABUTMENT ;
    NETEXPR "VDD VDD!" ;
    PORT
      LAYER met1 ;
        RECT 0 3.94 5.52 4.34 ;
    END
  END VDD
  PIN VSS
    DIRECTION INPUT ;
    USE GROUND ;
    SHAPE ABUTMENT ;
    NETEXPR "VSS VSS!" ;
    PORT
      LAYER met1 ;
        RECT 0 -0.2 5.52 0.2 ;
    END
  END VSS
  PIN Y
    DIRECTION OUTPUT ;
    USE SIGNAL ;
    ANTENNADIFFAREA 1.6128 LAYER met1 ;
    PORT
      LAYER met1 ;
        RECT 4.445 2.44 4.675 3.725 ;
        RECT 1.865 2.44 4.675 2.67 ;
        RECT 4.01 0.68 4.27 2.67 ;
        RECT 1.435 0.68 4.27 0.91 ;
        RECT 3.585 2.44 3.815 3.68 ;
        RECT 2.725 2.44 2.955 3.68 ;
        RECT 2.295 0.68 2.525 1.33 ;
        RECT 1.865 2.44 2.095 3.68 ;
        RECT 1.435 0.68 1.665 1.33 ;
    END
  END Y
  OBS
    LAYER met1 ;
      RECT 0.575 3.235 1.02 3.525 ;
      RECT 0.73 0.61 1.02 3.525 ;
      RECT 0.73 1.51 1.57 1.74 ;
      RECT 0.575 0.61 1.02 0.9 ;
  END
  PROPERTY CatenaDesignType "deviceLevel" ;
END CLKBUFX4_HS

MACRO CLKBUFX8_HS
  CLASS CORE ;
  ORIGIN 0 0 ;
  FOREIGN CLKBUFX8_HS 0 0 ;
  SIZE 8.74 BY 4.14 ;
  SYMMETRY X Y ;
  SITE CoreSite ;
  PIN A
    DIRECTION INPUT ;
    USE SIGNAL ;
    ANTENNAMODEL OXIDE1 ;
      ANTENNAGATEAREA 0.546 LAYER met1 ;
      ANTENNAMAXAREACAR 0.350275 LAYER met1 ;
      ANTENNAMAXSIDEAREACAR 0.349817 LAYER met1 ;
    PORT
      LAYER met1 ;
        RECT 0.79 1.415 1.05 2.655 ;
    END
  END A
  PIN VDD
    DIRECTION INPUT ;
    USE POWER ;
    SHAPE ABUTMENT ;
    NETEXPR "VDD VDD!" ;
    PORT
      LAYER met1 ;
        RECT 0 3.94 8.74 4.34 ;
    END
  END VDD
  PIN VSS
    DIRECTION INPUT ;
    USE GROUND ;
    SHAPE ABUTMENT ;
    NETEXPR "VSS VSS!" ;
    PORT
      LAYER met1 ;
        RECT 0 -0.2 8.74 0.2 ;
    END
  END VSS
  PIN Y
    DIRECTION OUTPUT ;
    USE SIGNAL ;
    ANTENNADIFFAREA 3.2256 LAYER met1 ;
    PORT
      LAYER met1 ;
        RECT 7.915 2.44 8.145 3.45 ;
        RECT 1.895 2.44 8.145 2.67 ;
        RECT 7.055 2.44 7.285 3.45 ;
        RECT 6.195 2.44 6.425 3.45 ;
        RECT 5.335 2.44 5.565 3.45 ;
        RECT 4.47 0.68 4.73 2.67 ;
        RECT 4.475 0.68 4.705 3.45 ;
        RECT 1.895 0.68 4.73 0.91 ;
        RECT 3.615 2.44 3.845 3.45 ;
        RECT 3.615 0.68 3.845 1.33 ;
        RECT 2.755 2.44 2.985 3.45 ;
        RECT 2.755 0.68 2.985 1.33 ;
        RECT 1.895 2.44 2.125 3.45 ;
        RECT 1.895 0.68 2.125 1.33 ;
    END
  END Y
  OBS
    LAYER met1 ;
      RECT 1.035 3.235 1.48 3.525 ;
      RECT 1.19 0.61 1.48 3.525 ;
      RECT 1.19 1.51 2.03 1.74 ;
      RECT 1.035 0.61 1.48 0.9 ;
  END
  PROPERTY CatenaDesignType "deviceLevel" ;
END CLKBUFX8_HS

MACRO CLKINVX1_HS
  CLASS CORE ;
  ORIGIN 0 0 ;
  FOREIGN CLKINVX1_HS 0 0 ;
  SIZE 2.76 BY 4.14 ;
  SYMMETRY X Y ;
  SITE CoreSite ;
  PIN A
    DIRECTION INPUT ;
    USE SIGNAL ;
    ANTENNAMODEL OXIDE1 ;
      ANTENNAGATEAREA 0.591 LAYER met1 ;
      ANTENNAMAXAREACAR 0.451607 LAYER met1 ;
      ANTENNAMAXSIDEAREACAR 0.416244 LAYER met1 ;
    PORT
      LAYER met1 ;
        RECT 1.25 1.455 1.51 2.695 ;
    END
  END A
  PIN VDD
    DIRECTION INPUT ;
    USE POWER ;
    SHAPE ABUTMENT ;
    NETEXPR "VDD VDD!" ;
    PORT
      LAYER met1 ;
        RECT 0 3.94 2.76 4.34 ;
    END
  END VDD
  PIN VSS
    DIRECTION INPUT ;
    USE GROUND ;
    SHAPE ABUTMENT ;
    NETEXPR "VSS VSS!" ;
    PORT
      LAYER met1 ;
        RECT 0 -0.2 2.76 0.2 ;
    END
  END VSS
  PIN Y
    DIRECTION OUTPUT ;
    USE SIGNAL ;
    ANTENNADIFFAREA 0.7791 LAYER met1 ;
    PORT
      LAYER met1 ;
        RECT 1.035 3.24 2.155 3.53 ;
        RECT 1.71 2.41 2.155 3.53 ;
        RECT 1.71 0.61 1.97 3.53 ;
        RECT 1.035 0.61 1.97 0.9 ;
    END
  END Y
  PROPERTY CatenaDesignType "deviceLevel" ;
END CLKINVX1_HS

MACRO CLKINVX2_HS
  CLASS CORE ;
  ORIGIN 0 0 ;
  FOREIGN CLKINVX2_HS 0 0 ;
  SIZE 3.68 BY 4.14 ;
  SYMMETRY X Y ;
  SITE CoreSite ;
  PIN A
    DIRECTION INPUT ;
    USE SIGNAL ;
    ANTENNAMODEL OXIDE1 ;
      ANTENNAGATEAREA 1.182 LAYER met1 ;
      ANTENNAMAXAREACAR 0.512014 LAYER met1 ;
      ANTENNAMAXSIDEAREACAR 0.458545 LAYER met1 ;
    PORT
      LAYER met1 ;
        RECT 1.25 1.315 1.51 2.555 ;
    END
  END A
  PIN VDD
    DIRECTION INPUT ;
    USE POWER ;
    SHAPE ABUTMENT ;
    NETEXPR "VDD VDD!" ;
    PORT
      LAYER met1 ;
        RECT 0 3.94 3.68 4.34 ;
    END
  END VDD
  PIN VSS
    DIRECTION INPUT ;
    USE GROUND ;
    SHAPE ABUTMENT ;
    NETEXPR "VSS VSS!" ;
    PORT
      LAYER met1 ;
        RECT 0 -0.2 3.68 0.2 ;
    END
  END VSS
  PIN Y
    DIRECTION OUTPUT ;
    USE SIGNAL ;
    ANTENNADIFFAREA 1.1032 LAYER met1 ;
    PORT
      LAYER met1 ;
        RECT 1.035 3.24 3.075 3.53 ;
        RECT 2.17 0.675 2.43 3.53 ;
        RECT 1.035 0.675 2.43 0.965 ;
    END
  END Y
  PROPERTY CatenaDesignType "deviceLevel" ;
END CLKINVX2_HS

MACRO CLKINVX4_HS
  CLASS CORE ;
  ORIGIN 0 0 ;
  FOREIGN CLKINVX4_HS 0 0 ;
  SIZE 6.44 BY 4.14 ;
  SYMMETRY X Y ;
  SITE CoreSite ;
  PIN A
    DIRECTION INPUT ;
    USE SIGNAL ;
    ANTENNAMODEL OXIDE1 ;
      ANTENNAGATEAREA 2.364 LAYER met1 ;
      ANTENNAMAXAREACAR 0.513092 LAYER met1 ;
      ANTENNAMAXSIDEAREACAR 0.445431 LAYER met1 ;
    PORT
      LAYER met1 ;
        RECT 0.79 1.465 1.05 2.705 ;
    END
  END A
  PIN VDD
    DIRECTION INPUT ;
    USE POWER ;
    SHAPE ABUTMENT ;
    NETEXPR "VDD VDD!" ;
    PORT
      LAYER met1 ;
        RECT 0 3.94 6.44 4.34 ;
    END
  END VDD
  PIN VSS
    DIRECTION INPUT ;
    USE GROUND ;
    SHAPE ABUTMENT ;
    NETEXPR "VSS VSS!" ;
    PORT
      LAYER met1 ;
        RECT 0 -0.2 6.44 0.2 ;
    END
  END VSS
  PIN Y
    DIRECTION OUTPUT ;
    USE SIGNAL ;
    ANTENNADIFFAREA 2.2064 LAYER met1 ;
    PORT
      LAYER met1 ;
        RECT 1.005 3.21 6.005 3.5 ;
        RECT 1.005 0.61 4.735 0.9 ;
        RECT 4.47 0.61 4.73 3.5 ;
    END
  END Y
  PROPERTY CatenaDesignType "deviceLevel" ;
END CLKINVX4_HS

MACRO CLKINVX8_HS
  CLASS CORE ;
  ORIGIN 0 0 ;
  FOREIGN CLKINVX8_HS 0 0 ;
  SIZE 11.5 BY 4.14 ;
  SYMMETRY X Y ;
  SITE CoreSite ;
  PIN A
    DIRECTION INPUT ;
    USE SIGNAL ;
    ANTENNAMODEL OXIDE1 ;
      ANTENNAGATEAREA 4.728 LAYER met1 ;
      ANTENNAMAXAREACAR 0.515609 LAYER met1 ;
      ANTENNAMAXSIDEAREACAR 0.441201 LAYER met1 ;
    PORT
      LAYER met1 ;
        RECT 0.79 1.465 1.05 2.705 ;
    END
  END A
  PIN VDD
    DIRECTION INPUT ;
    USE POWER ;
    SHAPE ABUTMENT ;
    NETEXPR "VDD VDD!" ;
    PORT
      LAYER met1 ;
        RECT 0 3.94 11.5 4.34 ;
    END
  END VDD
  PIN VSS
    DIRECTION INPUT ;
    USE GROUND ;
    SHAPE ABUTMENT ;
    NETEXPR "VSS VSS!" ;
    PORT
      LAYER met1 ;
        RECT 0 -0.2 11.5 0.2 ;
    END
  END VSS
  PIN Y
    DIRECTION OUTPUT ;
    USE SIGNAL ;
    ANTENNADIFFAREA 4.4128 LAYER met1 ;
    PORT
      LAYER met1 ;
        RECT 1.005 3.21 11.04 3.5 ;
        RECT 1.005 0.61 4.735 0.9 ;
        RECT 4.47 0.61 4.73 3.5 ;
    END
  END Y
  PROPERTY CatenaDesignType "deviceLevel" ;
  PROPERTY oaTaper "virtuosoDefaultSetup" ;
END CLKINVX8_HS

MACRO CLKMX2X2_HS
  CLASS CORE ;
  ORIGIN 0 0 ;
  FOREIGN CLKMX2X2_HS 0 0 ;
  SIZE 4.6 BY 4.14 ;
  SYMMETRY X Y ;
  SITE CoreSite ;
  PIN A
    DIRECTION INPUT ;
    USE SIGNAL ;
    ANTENNAMODEL OXIDE1 ;
      ANTENNAGATEAREA 0.18075 LAYER met1 ;
      ANTENNAMAXAREACAR 0.686584 LAYER met1 ;
      ANTENNAMAXSIDEAREACAR 0.807746 LAYER met1 ;
    PORT
      LAYER met1 ;
        RECT 1.25 2.02 1.51 3.26 ;
    END
  END A
  PIN B
    DIRECTION INPUT ;
    USE SIGNAL ;
    ANTENNAMODEL OXIDE1 ;
      ANTENNAGATEAREA 0.18075 LAYER met1 ;
      ANTENNAMAXAREACAR 0.672476 LAYER met1 ;
      ANTENNAMAXSIDEAREACAR 0.791148 LAYER met1 ;
    PORT
      LAYER met1 ;
        RECT 2.63 1.505 2.89 2.745 ;
    END
  END B
  PIN S0
    DIRECTION INPUT ;
    USE SIGNAL ;
    ANTENNAMODEL OXIDE1 ;
      ANTENNAGATEAREA 0.3615 LAYER met1 ;
      ANTENNAMAXAREACAR 0.94758 LAYER met1 ;
      ANTENNAMAXSIDEAREACAR 0.954357 LAYER met1 ;
    PORT
      LAYER met1 ;
        RECT 1.71 1.69 1.97 2.93 ;
    END
  END S0
  PIN VDD
    DIRECTION INPUT ;
    USE POWER ;
    SHAPE ABUTMENT ;
    NETEXPR "VDD VDD!" ;
    PORT
      LAYER met1 ;
        RECT 0 3.94 4.6 4.34 ;
    END
  END VDD
  PIN VSS
    DIRECTION INPUT ;
    USE GROUND ;
    SHAPE ABUTMENT ;
    NETEXPR "VSS VSS!" ;
    PORT
      LAYER met1 ;
        RECT 0 -0.2 4.6 0.2 ;
    END
  END VSS
  PIN Y
    DIRECTION OUTPUT ;
    USE SIGNAL ;
    ANTENNADIFFAREA 0.5376 LAYER met1 ;
    PORT
      LAYER met1 ;
        RECT 3.09 0.59 3.475 3.45 ;
    END
  END Y
  OBS
    LAYER met1 ;
      RECT 1.895 3.24 2.34 3.53 ;
      RECT 2.11 0.615 2.34 3.53 ;
      RECT 1.895 0.615 2.34 0.905 ;
      RECT 0.605 0.615 0.835 3.235 ;
  END
  PROPERTY CatenaDesignType "deviceLevel" ;
END CLKMX2X2_HS

MACRO CLKXOR2X1_HS
  CLASS CORE ;
  ORIGIN 0 0 ;
  FOREIGN CLKXOR2X1_HS 0 0 ;
  SIZE 4.14 BY 4.14 ;
  SYMMETRY X Y ;
  SITE CoreSite ;
  PIN A
    DIRECTION INPUT ;
    USE SIGNAL ;
    ANTENNAMODEL OXIDE1 ;
      ANTENNAGATEAREA 0.18075 LAYER met1 ;
      ANTENNAMAXAREACAR 0.606639 LAYER met1 ;
      ANTENNAMAXSIDEAREACAR 0.713693 LAYER met1 ;
    PORT
      LAYER met1 ;
        RECT 1.25 1.285 1.51 2.525 ;
    END
  END A
  PIN B
    DIRECTION INPUT ;
    USE SIGNAL ;
    ANTENNAMODEL OXIDE1 ;
      ANTENNAGATEAREA 0.3615 LAYER met1 ;
      ANTENNAMAXAREACAR 1.795934 LAYER met1 ;
      ANTENNAMAXSIDEAREACAR 1.767635 LAYER met1 ;
    PORT
      LAYER met1 ;
        RECT 1.71 1.31 1.97 2.55 ;
    END
  END B
  PIN VDD
    DIRECTION INPUT ;
    USE POWER ;
    SHAPE ABUTMENT ;
    NETEXPR "VDD VDD!" ;
    PORT
      LAYER met1 ;
        RECT 0 3.94 4.14 4.34 ;
    END
  END VDD
  PIN VSS
    DIRECTION INPUT ;
    USE GROUND ;
    SHAPE ABUTMENT ;
    NETEXPR "VSS VSS!" ;
    PORT
      LAYER met1 ;
        RECT 0 -0.2 4.14 0.2 ;
    END
  END VSS
  PIN Y
    DIRECTION OUTPUT ;
    USE SIGNAL ;
    ANTENNADIFFAREA 0.5883 LAYER met1 ;
    PORT
      LAYER met1 ;
        RECT 3.245 2.48 3.81 2.74 ;
        RECT 3.55 0.81 3.81 2.74 ;
        RECT 3.23 0.81 3.81 1.07 ;
        RECT 3.23 0.42 3.49 1.07 ;
        RECT 3.245 2.48 3.475 3.49 ;
    END
  END Y
  OBS
    LAYER met1 ;
      RECT 1.865 3.46 2.155 3.69 ;
      RECT 1.865 3.46 3.03 3.63 ;
      RECT 2.77 0.34 3.03 3.63 ;
      RECT 1.865 0.34 2.155 0.57 ;
      RECT 1.865 0.34 3.03 0.51 ;
      RECT 1.435 3.12 1.725 3.35 ;
      RECT 1.435 3.12 2.535 3.29 ;
      RECT 2.275 0.71 2.535 3.29 ;
      RECT 1.435 0.71 2.535 0.88 ;
      RECT 1.435 0.62 1.725 0.88 ;
      RECT 0.605 3.435 0.835 3.725 ;
      RECT 0.635 0.46 0.805 3.725 ;
      RECT 0.635 1.415 0.865 1.705 ;
      RECT 0.605 0.46 0.835 0.75 ;
  END
  PROPERTY CatenaDesignType "deviceLevel" ;
END CLKXOR2X1_HS

MACRO DFFRX1_HS
  CLASS CORE ;
  ORIGIN 0 0 ;
  FOREIGN DFFRX1_HS 0 0 ;
  SIZE 9.66 BY 4.14 ;
  SYMMETRY X Y ;
  SITE CoreSite ;
  PIN CK
    DIRECTION INPUT ;
    USE SIGNAL ;
    ANTENNAMODEL OXIDE1 ;
      ANTENNAGATEAREA 0.18075 LAYER met1 ;
      ANTENNAMAXAREACAR 0.799447 LAYER met1 ;
      ANTENNAMAXSIDEAREACAR 0.940526 LAYER met1 ;
    PORT
      LAYER met1 ;
        RECT 1.25 2.315 1.51 3.555 ;
    END
  END CK
  PIN D
    DIRECTION INPUT ;
    USE SIGNAL ;
    ANTENNAMODEL OXIDE1 ;
      ANTENNAGATEAREA 0.18075 LAYER met1 ;
      ANTENNAMAXAREACAR 0.686584 LAYER met1 ;
      ANTENNAMAXSIDEAREACAR 0.807746 LAYER met1 ;
    PORT
      LAYER met1 ;
        RECT 1.25 0.385 1.51 1.625 ;
    END
  END D
  PIN Q
    DIRECTION OUTPUT ;
    USE SIGNAL ;
    ANTENNADIFFAREA 0.5883 LAYER met1 ;
    PORT
      LAYER met1 ;
        RECT 8.15 2.44 8.415 3.45 ;
        RECT 8.185 0.485 8.415 1.135 ;
        RECT 8.15 0.68 8.41 3.45 ;
    END
  END Q
  PIN QN
    DIRECTION OUTPUT ;
    USE SIGNAL ;
    ANTENNADIFFAREA 0.5883 LAYER met1 ;
    PORT
      LAYER met1 ;
        RECT 9.045 2.44 9.33 3.45 ;
        RECT 9.07 0.68 9.33 3.45 ;
        RECT 9.045 0.485 9.275 1.135 ;
    END
  END QN
  PIN RN
    DIRECTION INPUT ;
    USE SIGNAL ;
    ANTENNAMODEL OXIDE1 ;
      ANTENNAGATEAREA 0.3615 LAYER met1 ;
      ANTENNAMAXAREACAR 2.283126 LAYER met1 ;
      ANTENNAMAXSIDEAREACAR 2.591978 LAYER met1 ;
    PORT
      LAYER met1 ;
        RECT 7.23 1.405 7.49 2.645 ;
    END
  END RN
  PIN VDD
    DIRECTION INPUT ;
    USE POWER ;
    SHAPE ABUTMENT ;
    NETEXPR "VDD VDD!" ;
    PORT
      LAYER met1 ;
        RECT 0 3.94 9.66 4.34 ;
    END
  END VDD
  PIN VSS
    DIRECTION INPUT ;
    USE GROUND ;
    SHAPE ABUTMENT ;
    NETEXPR "VSS VSS!" ;
    PORT
      LAYER met1 ;
        RECT 0 -0.2 9.66 0.2 ;
    END
  END VSS
  OBS
    LAYER met1 ;
      RECT 6.805 0.765 7.035 3.53 ;
      RECT 6.375 0.765 7.035 0.995 ;
      RECT 6.375 0.51 6.605 0.995 ;
      RECT 1.895 3.375 4.365 3.605 ;
      RECT 4.135 2.495 4.365 3.605 ;
      RECT 1.895 0.51 2.125 3.605 ;
      RECT 3.185 2.945 3.415 3.235 ;
      RECT 2.325 2.945 2.555 3.235 ;
      RECT 2.325 3.005 3.415 3.175 ;
      RECT 7.665 0.415 7.895 3.53 ;
      RECT 5.425 0.95 5.655 2.795 ;
      RECT 4.995 0.51 5.225 3.235 ;
      RECT 4.565 0.51 4.795 3.235 ;
      RECT 3.705 0.51 3.935 3.235 ;
      RECT 0.605 0.51 0.835 3.235 ;
  END
  PROPERTY CatenaDesignType "deviceLevel" ;
END DFFRX1_HS

MACRO DFFRX4_HS
  CLASS CORE ;
  ORIGIN 0 0 ;
  FOREIGN DFFRX4_HS 0 0 ;
  SIZE 13.34 BY 4.14 ;
  SYMMETRY X Y ;
  SITE CoreSite ;
  PIN CK
    DIRECTION INPUT ;
    USE SIGNAL ;
    ANTENNAMODEL OXIDE1 ;
      ANTENNAGATEAREA 0.18075 LAYER met1 ;
      ANTENNAMAXAREACAR 0.879391 LAYER met1 ;
      ANTENNAMAXSIDEAREACAR 1.034578 LAYER met1 ;
    PORT
      LAYER met1 ;
        RECT 1.25 2.045 1.51 3.285 ;
    END
  END CK
  PIN D
    DIRECTION INPUT ;
    USE SIGNAL ;
    ANTENNAMODEL OXIDE1 ;
      ANTENNAGATEAREA 0.18075 LAYER met1 ;
      ANTENNAMAXAREACAR 0.686584 LAYER met1 ;
      ANTENNAMAXSIDEAREACAR 0.807746 LAYER met1 ;
    PORT
      LAYER met1 ;
        RECT 1.25 0.645 1.51 1.885 ;
    END
  END D
  PIN Q
    DIRECTION OUTPUT ;
    USE SIGNAL ;
    ANTENNADIFFAREA 1.2432 LAYER met1 ;
    PORT
      LAYER met1 ;
        RECT 10.335 2.44 10.71 3.45 ;
        RECT 10.45 0.68 10.71 3.45 ;
        RECT 10.335 0.485 10.565 1.135 ;
        RECT 9.475 1.77 10.71 2 ;
        RECT 9.475 0.485 9.705 3.45 ;
    END
  END Q
  PIN QN
    DIRECTION OUTPUT ;
    USE SIGNAL ;
    ANTENNADIFFAREA 1.2432 LAYER met1 ;
    PORT
      LAYER met1 ;
        RECT 12.055 2.44 12.55 3.45 ;
        RECT 12.29 0.68 12.55 3.45 ;
        RECT 11.195 1.77 12.55 2 ;
        RECT 12.055 0.68 12.55 1.33 ;
        RECT 12.055 0.485 12.285 1.33 ;
        RECT 11.195 0.485 11.425 3.45 ;
    END
  END QN
  PIN RN
    DIRECTION INPUT ;
    USE SIGNAL ;
    ANTENNAMODEL OXIDE1 ;
      ANTENNAGATEAREA 0.73575 LAYER met1 ;
      ANTENNAMAXAREACAR 1.141881 LAYER met1 ;
      ANTENNAMAXSIDEAREACAR 1.201495 LAYER met1 ;
    PORT
      LAYER met1 ;
        RECT 6.31 1.85 6.57 3.09 ;
    END
  END RN
  PIN VDD
    DIRECTION INPUT ;
    USE POWER ;
    SHAPE ABUTMENT ;
    NETEXPR "VDD VDD!" ;
    PORT
      LAYER met1 ;
        RECT 0 3.94 13.34 4.34 ;
    END
  END VDD
  PIN VSS
    DIRECTION INPUT ;
    USE GROUND ;
    SHAPE ABUTMENT ;
    NETEXPR "VSS VSS!" ;
    PORT
      LAYER met1 ;
        RECT 0 -0.2 13.34 0.2 ;
    END
  END VSS
  OBS
    LAYER met1 ;
      RECT 8.095 0.4 8.325 0.705 ;
      RECT 7.235 0.4 7.465 0.705 ;
      RECT 6.375 0.4 6.605 0.705 ;
      RECT 6.375 0.4 8.325 0.63 ;
      RECT 6.805 3.1 7.895 3.33 ;
      RECT 7.665 0.775 7.895 3.33 ;
      RECT 6.805 2.665 7.035 3.33 ;
      RECT 1.895 3.375 4.365 3.605 ;
      RECT 4.135 2.495 4.365 3.605 ;
      RECT 1.895 0.51 2.125 3.605 ;
      RECT 3.185 2.945 3.415 3.235 ;
      RECT 2.325 2.945 2.555 3.235 ;
      RECT 2.325 3.005 3.415 3.175 ;
      RECT 8.615 0.485 8.845 3.45 ;
      RECT 5.425 0.95 5.655 2.795 ;
      RECT 4.995 0.51 5.225 3.235 ;
      RECT 4.565 0.51 4.795 3.235 ;
      RECT 3.705 0.51 3.935 3.235 ;
      RECT 0.605 0.51 0.835 3.235 ;
  END
  PROPERTY CatenaDesignType "deviceLevel" ;
END DFFRX4_HS

MACRO DFFSRX1_HS
  CLASS CORE ;
  ORIGIN 0 0 ;
  FOREIGN DFFSRX1_HS 0 0 ;
  SIZE 12.42 BY 4.14 ;
  SYMMETRY X Y ;
  SITE CoreSite ;
  PIN CK
    DIRECTION INPUT ;
    USE SIGNAL ;
    ANTENNAMODEL OXIDE1 ;
      ANTENNAGATEAREA 0.18075 LAYER met1 ;
      ANTENNAMAXAREACAR 0.888797 LAYER met1 ;
      ANTENNAMAXSIDEAREACAR 1.045643 LAYER met1 ;
    PORT
      LAYER met1 ;
        RECT 1.25 2.19 1.51 3.43 ;
    END
  END CK
  PIN D
    DIRECTION INPUT ;
    USE SIGNAL ;
    ANTENNAMODEL OXIDE1 ;
      ANTENNAGATEAREA 0.18075 LAYER met1 ;
      ANTENNAMAXAREACAR 0.550207 LAYER met1 ;
      ANTENNAMAXSIDEAREACAR 0.647303 LAYER met1 ;
    PORT
      LAYER met1 ;
        RECT 1.25 0.805 1.51 2.045 ;
    END
  END D
  PIN Q
    DIRECTION OUTPUT ;
    USE SIGNAL ;
    ANTENNADIFFAREA 0.5883 LAYER met1 ;
    PORT
      LAYER met1 ;
        RECT 10.675 2.42 11.17 3.57 ;
        RECT 10.91 0.375 11.17 3.57 ;
        RECT 10.675 0.375 11.17 1.275 ;
    END
  END Q
  PIN QN
    DIRECTION OUTPUT ;
    USE SIGNAL ;
    ANTENNADIFFAREA 0.5883 LAYER met1 ;
    PORT
      LAYER met1 ;
        RECT 11.37 2.42 11.765 3.57 ;
        RECT 11.37 0.375 11.765 1.275 ;
        RECT 11.37 0.375 11.63 3.57 ;
    END
  END QN
  PIN RN
    DIRECTION INPUT ;
    USE SIGNAL ;
    ANTENNAMODEL OXIDE1 ;
      ANTENNAGATEAREA 0.18075 LAYER met1 ;
      ANTENNAMAXAREACAR 0.757123 LAYER met1 ;
      ANTENNAMAXSIDEAREACAR 0.890733 LAYER met1 ;
    PORT
      LAYER met1 ;
        RECT 7.23 1.155 7.49 2.395 ;
    END
  END RN
  PIN SN
    DIRECTION INPUT ;
    USE SIGNAL ;
    ANTENNAMODEL OXIDE1 ;
      ANTENNAGATEAREA 0.3615 LAYER met1 ;
      ANTENNAMAXAREACAR 1.526003 LAYER met1 ;
      ANTENNAMAXSIDEAREACAR 1.701245 LAYER met1 ;
    PORT
      LAYER met1 ;
        RECT 4.47 1.075 4.73 2.315 ;
    END
  END SN
  PIN VDD
    DIRECTION INPUT ;
    USE POWER ;
    SHAPE ABUTMENT ;
    NETEXPR "VDD VDD!" ;
    PORT
      LAYER met1 ;
        RECT 0 3.94 12.42 4.34 ;
    END
  END VDD
  PIN VSS
    DIRECTION INPUT ;
    USE GROUND ;
    SHAPE ABUTMENT ;
    NETEXPR "VSS VSS!" ;
    PORT
      LAYER met1 ;
        RECT 0 -0.2 12.42 0.2 ;
    END
  END VSS
  OBS
    LAYER met1 ;
      RECT 6.405 0.845 9.005 1.015 ;
      RECT 8.775 0.555 9.005 1.015 ;
      RECT 6.405 0.555 6.635 1.015 ;
      RECT 6.015 3.425 9.005 3.595 ;
      RECT 8.775 3.26 9.005 3.595 ;
      RECT 6.015 3.26 6.245 3.595 ;
      RECT 5.585 2.535 5.815 3.235 ;
      RECT 8.51 2.495 8.74 2.785 ;
      RECT 5.585 2.535 8.74 2.765 ;
      RECT 5.975 0.51 6.205 2.765 ;
      RECT 8.345 2.945 8.575 3.235 ;
      RECT 6.875 2.945 7.105 3.235 ;
      RECT 6.875 3.005 8.575 3.175 ;
      RECT 3.865 3.005 5.385 3.235 ;
      RECT 5.155 0.715 5.385 3.235 ;
      RECT 3.865 2.945 4.095 3.235 ;
      RECT 5.155 0.715 5.775 0.945 ;
      RECT 5.545 0.46 5.775 0.945 ;
      RECT 4.535 0.345 4.825 0.575 ;
      RECT 3.675 0.345 3.965 0.575 ;
      RECT 3.675 0.375 4.825 0.545 ;
      RECT 3.8 1.42 4.03 1.71 ;
      RECT 3.8 1.5 4.32 1.64 ;
      RECT 4.18 0.685 4.32 1.64 ;
      RECT 4.105 0.685 4.395 0.915 ;
      RECT 1.895 3.405 3.725 3.575 ;
      RECT 3.555 2.105 3.725 3.575 ;
      RECT 1.895 0.51 2.125 3.575 ;
      RECT 3.555 2.105 3.785 2.395 ;
      RECT 10.155 0.51 10.385 3.235 ;
      RECT 9.295 0.51 9.525 3.235 ;
      RECT 6.805 0.475 8.605 0.705 ;
      RECT 3.185 0.51 3.415 3.235 ;
      RECT 0.605 0.51 0.835 3.235 ;
  END
  PROPERTY CatenaDesignType "deviceLevel" ;
END DFFSRX1_HS

MACRO DFFSRX4_HS
  CLASS CORE ;
  ORIGIN 0 0 ;
  FOREIGN DFFSRX4_HS 0 0 ;
  SIZE 15.18 BY 4.14 ;
  SYMMETRY X Y ;
  SITE CoreSite ;
  PIN CK
    DIRECTION INPUT ;
    USE SIGNAL ;
    ANTENNAMODEL OXIDE1 ;
      ANTENNAGATEAREA 0.18075 LAYER met1 ;
      ANTENNAMAXAREACAR 0.874689 LAYER met1 ;
      ANTENNAMAXSIDEAREACAR 1.029046 LAYER met1 ;
    PORT
      LAYER met1 ;
        RECT 1.25 2.19 1.51 3.43 ;
    END
  END CK
  PIN D
    DIRECTION INPUT ;
    USE SIGNAL ;
    ANTENNAMODEL OXIDE1 ;
      ANTENNAGATEAREA 0.18075 LAYER met1 ;
      ANTENNAMAXAREACAR 0.686584 LAYER met1 ;
      ANTENNAMAXSIDEAREACAR 0.807746 LAYER met1 ;
    PORT
      LAYER met1 ;
        RECT 1.25 0.805 1.51 2.045 ;
    END
  END D
  PIN Q
    DIRECTION OUTPUT ;
    USE SIGNAL ;
    ANTENNADIFFAREA 1.2432 LAYER met1 ;
    PORT
      LAYER met1 ;
        RECT 12.29 2.44 12.625 3.45 ;
        RECT 12.395 0.485 12.625 1.135 ;
        RECT 12.29 0.68 12.55 3.45 ;
        RECT 11.535 1.77 12.55 2 ;
        RECT 11.535 0.485 11.765 3.45 ;
    END
  END Q
  PIN QN
    DIRECTION OUTPUT ;
    USE SIGNAL ;
    ANTENNADIFFAREA 1.2432 LAYER met1 ;
    PORT
      LAYER met1 ;
        RECT 14.115 0.68 14.39 3.45 ;
        RECT 14.115 0.485 14.345 3.45 ;
        RECT 13.255 1.77 14.39 2 ;
        RECT 13.255 0.485 13.485 3.45 ;
    END
  END QN
  PIN RN
    DIRECTION INPUT ;
    USE SIGNAL ;
    ANTENNAMODEL OXIDE1 ;
      ANTENNAGATEAREA 0.18075 LAYER met1 ;
      ANTENNAMAXAREACAR 0.757123 LAYER met1 ;
      ANTENNAMAXSIDEAREACAR 0.890733 LAYER met1 ;
    PORT
      LAYER met1 ;
        RECT 7.23 1.62 7.49 2.86 ;
    END
  END RN
  PIN SN
    DIRECTION INPUT ;
    USE SIGNAL ;
    ANTENNAMODEL OXIDE1 ;
      ANTENNAGATEAREA 0.3615 LAYER met1 ;
      ANTENNAMAXAREACAR 1.5213 LAYER met1 ;
      ANTENNAMAXSIDEAREACAR 1.695712 LAYER met1 ;
    PORT
      LAYER met1 ;
        RECT 4.47 1.06 4.73 2.3 ;
        RECT 4.495 0.95 4.725 2.3 ;
    END
  END SN
  PIN VDD
    DIRECTION INPUT ;
    USE POWER ;
    SHAPE ABUTMENT ;
    NETEXPR "VDD VDD!" ;
    PORT
      LAYER met1 ;
        RECT 0 3.94 15.18 4.34 ;
    END
  END VDD
  PIN VSS
    DIRECTION INPUT ;
    USE GROUND ;
    SHAPE ABUTMENT ;
    NETEXPR "VSS VSS!" ;
    PORT
      LAYER met1 ;
        RECT 0 -0.2 15.18 0.2 ;
    END
  END VSS
  OBS
    LAYER met1 ;
      RECT 5.585 1.25 5.815 3.235 ;
      RECT 9.295 1.25 9.525 2.115 ;
      RECT 5.585 1.25 9.525 1.48 ;
      RECT 5.975 0.51 6.205 1.48 ;
      RECT 6.405 0.715 9.005 0.885 ;
      RECT 8.775 0.51 9.005 0.885 ;
      RECT 6.405 0.51 6.635 0.885 ;
      RECT 6.015 3.405 9.005 3.575 ;
      RECT 8.775 3.24 9.005 3.575 ;
      RECT 6.015 3.24 6.245 3.575 ;
      RECT 8.315 0.345 8.605 0.575 ;
      RECT 6.805 0.345 7.095 0.575 ;
      RECT 6.805 0.375 8.605 0.545 ;
      RECT 8.345 2.945 8.575 3.235 ;
      RECT 6.875 2.945 7.105 3.235 ;
      RECT 6.875 3.005 8.575 3.175 ;
      RECT 3.865 3.005 5.385 3.235 ;
      RECT 5.155 0.715 5.385 3.235 ;
      RECT 3.865 2.945 4.095 3.235 ;
      RECT 5.155 0.715 5.775 0.945 ;
      RECT 5.545 0.46 5.775 0.945 ;
      RECT 4.535 0.345 4.825 0.575 ;
      RECT 3.675 0.345 3.965 0.575 ;
      RECT 3.675 0.375 4.825 0.545 ;
      RECT 1.895 3.405 3.725 3.575 ;
      RECT 3.555 2.155 3.725 3.575 ;
      RECT 1.895 0.51 2.125 3.575 ;
      RECT 3.555 2.155 3.785 2.445 ;
      RECT 10.675 0.485 10.905 3.45 ;
      RECT 9.725 0.685 9.955 3.315 ;
      RECT 3.185 0.51 3.415 3.235 ;
      RECT 0.605 0.51 0.835 3.235 ;
  END
  PROPERTY CatenaDesignType "deviceLevel" ;
END DFFSRX4_HS

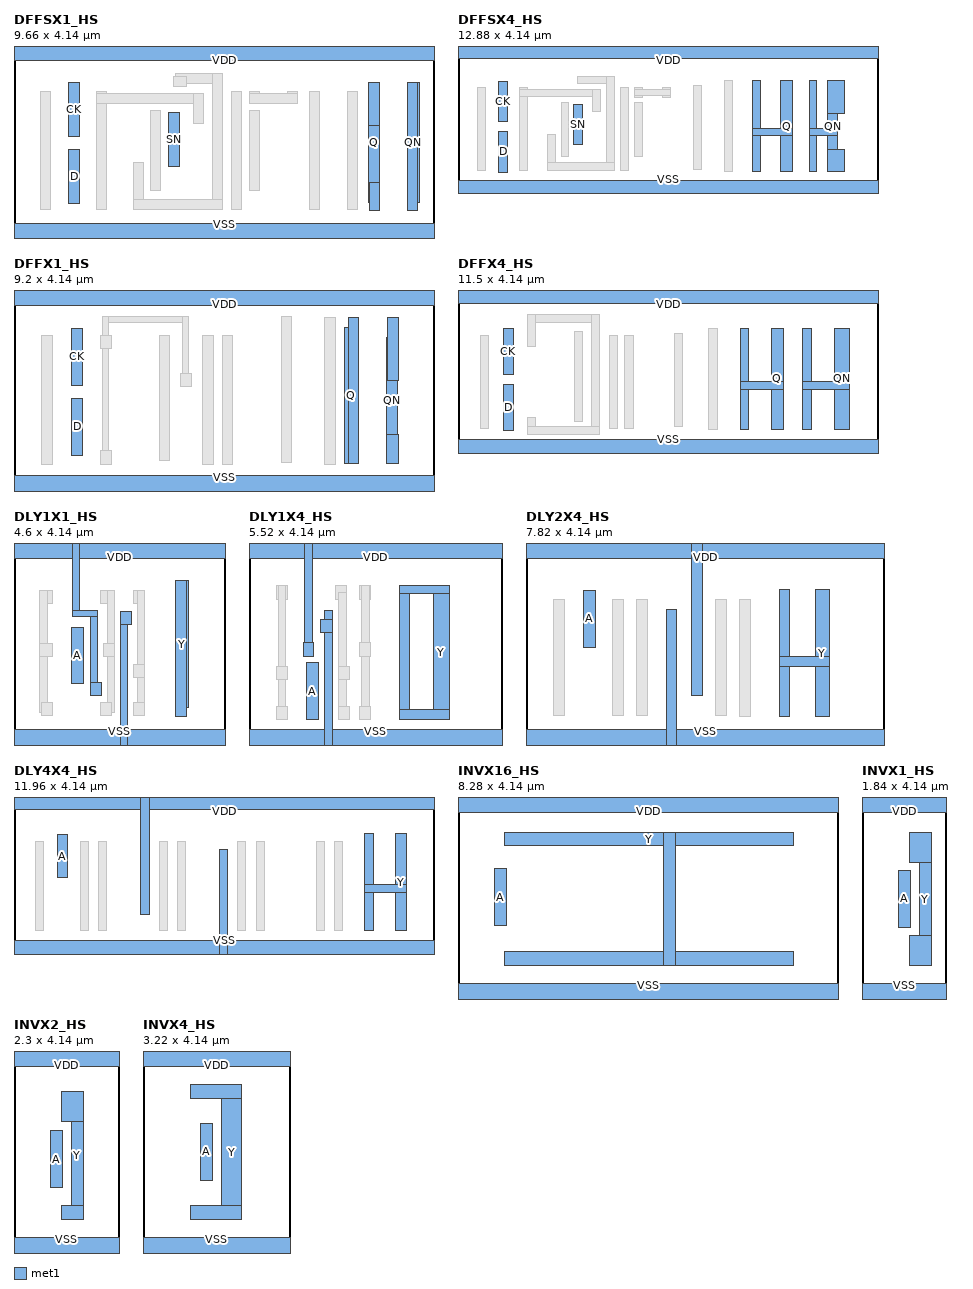
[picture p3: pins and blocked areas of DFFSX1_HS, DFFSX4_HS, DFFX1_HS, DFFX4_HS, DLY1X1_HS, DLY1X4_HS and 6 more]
MACRO DFFSX1_HS
  CLASS CORE ;
  ORIGIN 0 0 ;
  FOREIGN DFFSX1_HS 0 0 ;
  SIZE 9.66 BY 4.14 ;
  SYMMETRY X Y ;
  SITE CoreSite ;
  PIN CK
    DIRECTION INPUT ;
    USE SIGNAL ;
    ANTENNAMODEL OXIDE1 ;
      ANTENNAGATEAREA 0.18075 LAYER met1 ;
      ANTENNAMAXAREACAR 0.874689 LAYER met1 ;
      ANTENNAMAXSIDEAREACAR 1.029046 LAYER met1 ;
    PORT
      LAYER met1 ;
        RECT 1.25 2.19 1.51 3.43 ;
    END
  END CK
  PIN D
    DIRECTION INPUT ;
    USE SIGNAL ;
    ANTENNAMODEL OXIDE1 ;
      ANTENNAGATEAREA 0.18075 LAYER met1 ;
      ANTENNAMAXAREACAR 0.686584 LAYER met1 ;
      ANTENNAMAXSIDEAREACAR 0.807746 LAYER met1 ;
    PORT
      LAYER met1 ;
        RECT 1.25 0.655 1.51 1.895 ;
    END
  END D
  PIN Q
    DIRECTION OUTPUT ;
    USE SIGNAL ;
    ANTENNADIFFAREA 0.5883 LAYER met1 ;
    PORT
      LAYER met1 ;
        RECT 8.15 2.44 8.415 3.45 ;
        RECT 8.185 0.485 8.415 1.135 ;
        RECT 8.15 0.68 8.41 3.45 ;
    END
  END Q
  PIN QN
    DIRECTION OUTPUT ;
    USE SIGNAL ;
    ANTENNADIFFAREA 0.5883 LAYER met1 ;
    PORT
      LAYER met1 ;
        RECT 9.045 0.68 9.33 3.45 ;
        RECT 9.045 0.485 9.275 3.45 ;
    END
  END QN
  PIN SN
    DIRECTION INPUT ;
    USE SIGNAL ;
    ANTENNAMODEL OXIDE1 ;
      ANTENNAGATEAREA 0.3615 LAYER met1 ;
      ANTENNAMAXAREACAR 1.5213 LAYER met1 ;
      ANTENNAMAXSIDEAREACAR 1.695712 LAYER met1 ;
    PORT
      LAYER met1 ;
        RECT 3.545 1.5 3.805 2.74 ;
    END
  END SN
  PIN VDD
    DIRECTION INPUT ;
    USE POWER ;
    SHAPE ABUTMENT ;
    NETEXPR "VDD VDD!" ;
    PORT
      LAYER met1 ;
        RECT 0 3.94 9.66 4.34 ;
    END
  END VDD
  PIN VSS
    DIRECTION INPUT ;
    USE GROUND ;
    SHAPE ABUTMENT ;
    NETEXPR "VSS VSS!" ;
    PORT
      LAYER met1 ;
        RECT 0 -0.2 9.66 0.2 ;
    END
  END VSS
  OBS
    LAYER met1 ;
      RECT 6.285 2.945 6.515 3.235 ;
      RECT 5.425 2.945 5.655 3.235 ;
      RECT 5.425 2.945 6.515 3.175 ;
      RECT 3.705 3.41 4.795 3.64 ;
      RECT 4.565 0.51 4.795 3.64 ;
      RECT 3.675 3.355 3.965 3.585 ;
      RECT 2.755 0.51 2.985 1.6 ;
      RECT 2.755 0.51 4.795 0.74 ;
      RECT 1.895 0.51 2.125 3.235 ;
      RECT 1.895 2.965 4.365 3.195 ;
      RECT 4.135 2.495 4.365 3.195 ;
      RECT 7.665 0.51 7.895 3.235 ;
      RECT 6.805 0.51 7.035 3.235 ;
      RECT 5.425 0.95 5.655 2.795 ;
      RECT 4.995 0.51 5.225 3.235 ;
      RECT 3.145 0.95 3.375 2.795 ;
      RECT 0.605 0.51 0.835 3.235 ;
  END
  PROPERTY CatenaDesignType "deviceLevel" ;
END DFFSX1_HS

MACRO DFFSX4_HS
  CLASS CORE ;
  ORIGIN 0 0 ;
  FOREIGN DFFSX4_HS 0 0 ;
  SIZE 12.88 BY 4.14 ;
  SYMMETRY X Y ;
  SITE CoreSite ;
  PIN CK
    DIRECTION INPUT ;
    USE SIGNAL ;
    ANTENNAMODEL OXIDE1 ;
      ANTENNAGATEAREA 0.18075 LAYER met1 ;
      ANTENNAMAXAREACAR 0.874689 LAYER met1 ;
      ANTENNAMAXSIDEAREACAR 1.029046 LAYER met1 ;
    PORT
      LAYER met1 ;
        RECT 1.25 1.995 1.51 3.235 ;
    END
  END CK
  PIN D
    DIRECTION INPUT ;
    USE SIGNAL ;
    ANTENNAMODEL OXIDE1 ;
      ANTENNAGATEAREA 0.18075 LAYER met1 ;
      ANTENNAMAXAREACAR 0.686584 LAYER met1 ;
      ANTENNAMAXSIDEAREACAR 0.807746 LAYER met1 ;
    PORT
      LAYER met1 ;
        RECT 1.25 0.46 1.51 1.7 ;
    END
  END D
  PIN Q
    DIRECTION OUTPUT ;
    USE SIGNAL ;
    ANTENNADIFFAREA 1.2432 LAYER met1 ;
    PORT
      LAYER met1 ;
        RECT 9.905 0.485 10.25 3.255 ;
        RECT 9.045 1.575 10.25 1.805 ;
        RECT 9.045 0.485 9.275 3.255 ;
    END
  END Q
  PIN QN
    DIRECTION OUTPUT ;
    USE SIGNAL ;
    ANTENNADIFFAREA 1.2432 LAYER met1 ;
    PORT
      LAYER met1 ;
        RECT 11.345 2.245 11.855 3.255 ;
        RECT 11.345 0.485 11.855 1.135 ;
        RECT 11.345 0.485 11.63 3.255 ;
        RECT 10.765 1.575 11.63 1.805 ;
        RECT 10.765 0.485 10.995 3.255 ;
    END
  END QN
  PIN SN
    DIRECTION INPUT ;
    USE SIGNAL ;
    ANTENNAMODEL OXIDE1 ;
      ANTENNAGATEAREA 0.3615 LAYER met1 ;
      ANTENNAMAXAREACAR 1.518949 LAYER met1 ;
      ANTENNAMAXSIDEAREACAR 1.692946 LAYER met1 ;
    PORT
      LAYER met1 ;
        RECT 3.55 1.305 3.81 2.545 ;
    END
  END SN
  PIN VDD
    DIRECTION INPUT ;
    USE POWER ;
    SHAPE ABUTMENT ;
    NETEXPR "VDD VDD!" ;
    PORT
      LAYER met1 ;
        RECT 0 3.94 12.88 4.34 ;
    END
  END VDD
  PIN VSS
    DIRECTION INPUT ;
    USE GROUND ;
    SHAPE ABUTMENT ;
    NETEXPR "VSS VSS!" ;
    PORT
      LAYER met1 ;
        RECT 0 -0.2 12.88 0.2 ;
    END
  END VSS
  OBS
    LAYER met1 ;
      RECT 6.285 2.75 6.515 3.04 ;
      RECT 5.425 2.75 5.655 3.04 ;
      RECT 5.425 2.81 6.515 2.98 ;
      RECT 3.675 3.16 4.795 3.39 ;
      RECT 4.565 0.51 4.795 3.39 ;
      RECT 2.755 0.51 2.985 1.6 ;
      RECT 2.755 0.51 4.795 0.74 ;
      RECT 1.895 0.51 2.125 3.04 ;
      RECT 1.895 2.77 4.365 3 ;
      RECT 4.135 2.31 4.365 3 ;
      RECT 8.185 0.485 8.415 3.255 ;
      RECT 7.235 0.55 7.465 3.12 ;
      RECT 5.425 0.95 5.655 2.6 ;
      RECT 4.995 0.51 5.225 3.04 ;
      RECT 3.17 0.95 3.4 2.6 ;
      RECT 0.605 0.51 0.835 3.04 ;
  END
  PROPERTY CatenaDesignType "deviceLevel" ;
END DFFSX4_HS

MACRO DFFX1_HS
  CLASS CORE ;
  ORIGIN 0 0 ;
  FOREIGN DFFX1_HS 0 0 ;
  SIZE 9.2 BY 4.14 ;
  SYMMETRY X Y ;
  SITE CoreSite ;
  PIN CK
    DIRECTION INPUT ;
    USE SIGNAL ;
    ANTENNAMODEL OXIDE1 ;
      ANTENNAGATEAREA 0.18075 LAYER met1 ;
      ANTENNAMAXAREACAR 0.874689 LAYER met1 ;
      ANTENNAMAXSIDEAREACAR 1.029046 LAYER met1 ;
    PORT
      LAYER met1 ;
        RECT 1.25 2.19 1.51 3.43 ;
    END
  END CK
  PIN D
    DIRECTION INPUT ;
    USE SIGNAL ;
    ANTENNAMODEL OXIDE1 ;
      ANTENNAGATEAREA 0.18075 LAYER met1 ;
      ANTENNAMAXAREACAR 0.686584 LAYER met1 ;
      ANTENNAMAXSIDEAREACAR 0.807746 LAYER met1 ;
    PORT
      LAYER met1 ;
        RECT 1.25 0.655 1.51 1.895 ;
    END
  END D
  PIN Q
    DIRECTION OUTPUT ;
    USE SIGNAL ;
    ANTENNADIFFAREA 0.5883 LAYER met1 ;
    PORT
      LAYER met1 ;
        RECT 7.325 0.465 7.555 3.67 ;
        RECT 7.23 0.465 7.555 3.45 ;
    END
  END Q
  PIN QN
    DIRECTION OUTPUT ;
    USE SIGNAL ;
    ANTENNADIFFAREA 0.5883 LAYER met1 ;
    PORT
      LAYER met1 ;
        RECT 8.185 2.3 8.415 3.67 ;
        RECT 8.15 0.465 8.415 1.115 ;
        RECT 8.15 0.465 8.41 3.235 ;
    END
  END QN
  PIN VDD
    DIRECTION INPUT ;
    USE POWER ;
    SHAPE ABUTMENT ;
    NETEXPR "VDD VDD!" ;
    PORT
      LAYER met1 ;
        RECT 0 3.94 9.2 4.34 ;
    END
  END VDD
  PIN VSS
    DIRECTION INPUT ;
    USE GROUND ;
    SHAPE ABUTMENT ;
    NETEXPR "VSS VSS!" ;
    PORT
      LAYER met1 ;
        RECT 0 -0.2 9.2 0.2 ;
    END
  END VSS
  OBS
    LAYER met1 ;
      RECT 1.94 3.555 3.83 3.695 ;
      RECT 3.69 2.155 3.83 3.695 ;
      RECT 1.94 0.46 2.08 3.695 ;
      RECT 1.895 2.985 2.125 3.275 ;
      RECT 3.65 2.155 3.88 2.445 ;
      RECT 1.895 0.46 2.125 0.75 ;
      RECT 6.805 0.445 7.035 3.675 ;
      RECT 5.855 0.5 6.085 3.69 ;
      RECT 4.565 0.46 4.795 3.275 ;
      RECT 4.135 0.46 4.365 3.275 ;
      RECT 3.185 0.54 3.415 3.275 ;
      RECT 0.605 0.46 0.835 3.275 ;
  END
  PROPERTY CatenaDesignType "deviceLevel" ;
END DFFX1_HS

MACRO DFFX4_HS
  CLASS CORE ;
  ORIGIN 0 0 ;
  FOREIGN DFFX4_HS 0 0 ;
  SIZE 11.5 BY 4.14 ;
  SYMMETRY X Y ;
  SITE CoreSite ;
  PIN CK
    DIRECTION INPUT ;
    USE SIGNAL ;
    ANTENNAMODEL OXIDE1 ;
      ANTENNAGATEAREA 0.18075 LAYER met1 ;
      ANTENNAMAXAREACAR 0.874689 LAYER met1 ;
      ANTENNAMAXSIDEAREACAR 1.029046 LAYER met1 ;
    PORT
      LAYER met1 ;
        RECT 1.25 1.995 1.51 3.235 ;
    END
  END CK
  PIN D
    DIRECTION INPUT ;
    USE SIGNAL ;
    ANTENNAMODEL OXIDE1 ;
      ANTENNAGATEAREA 0.18075 LAYER met1 ;
      ANTENNAMAXAREACAR 0.686584 LAYER met1 ;
      ANTENNAMAXSIDEAREACAR 0.807746 LAYER met1 ;
    PORT
      LAYER met1 ;
        RECT 1.25 0.46 1.51 1.7 ;
    END
  END D
  PIN Q
    DIRECTION OUTPUT ;
    USE SIGNAL ;
    ANTENNADIFFAREA 1.2432 LAYER met1 ;
    PORT
      LAYER met1 ;
        RECT 8.585 0.485 8.91 3.255 ;
        RECT 7.725 1.575 8.91 1.805 ;
        RECT 7.725 0.485 7.955 3.255 ;
    END
  END Q
  PIN QN
    DIRECTION OUTPUT ;
    USE SIGNAL ;
    ANTENNADIFFAREA 1.2432 LAYER met1 ;
    PORT
      LAYER met1 ;
        RECT 10.305 0.485 10.71 3.255 ;
        RECT 9.445 1.575 10.71 1.805 ;
        RECT 9.445 0.485 9.675 3.255 ;
    END
  END QN
  PIN VDD
    DIRECTION INPUT ;
    USE POWER ;
    SHAPE ABUTMENT ;
    NETEXPR "VDD VDD!" ;
    PORT
      LAYER met1 ;
        RECT 0 3.94 11.5 4.34 ;
    END
  END VDD
  PIN VSS
    DIRECTION INPUT ;
    USE GROUND ;
    SHAPE ABUTMENT ;
    NETEXPR "VSS VSS!" ;
    PORT
      LAYER met1 ;
        RECT 0 -0.2 11.5 0.2 ;
    END
  END VSS
  OBS
    LAYER met1 ;
      RECT 1.895 3.41 3.88 3.64 ;
      RECT 3.65 0.34 3.88 3.64 ;
      RECT 1.895 2.75 2.125 3.64 ;
      RECT 1.895 0.34 2.125 0.8 ;
      RECT 1.895 0.34 3.88 0.57 ;
      RECT 6.865 0.485 7.095 3.255 ;
      RECT 5.915 0.55 6.145 3.12 ;
      RECT 4.565 0.51 4.795 3.04 ;
      RECT 4.135 0.51 4.365 3.04 ;
      RECT 3.185 0.71 3.415 3.16 ;
      RECT 0.605 0.51 0.835 3.04 ;
  END
  PROPERTY CatenaDesignType "deviceLevel" ;
END DFFX4_HS

MACRO DLY1X1_HS
  CLASS CORE ;
  ORIGIN 0 0 ;
  FOREIGN DLY1X1_HS 0 0 ;
  SIZE 4.6 BY 4.14 ;
  SYMMETRY X Y ;
  SITE CoreSite ;
  PIN A
    DIRECTION INPUT ;
    USE SIGNAL ;
    ANTENNAMODEL OXIDE1 ;
      ANTENNAGATEAREA 0.18075 LAYER met1 ;
      ANTENNAMAXAREACAR 0.902905 LAYER met1 ;
      ANTENNAMAXSIDEAREACAR 1.062241 LAYER met1 ;
    PORT
      LAYER met1 ;
        RECT 1.25 1.2 1.51 2.44 ;
    END
  END A
  PIN VDD
    DIRECTION INPUT ;
    USE POWER ;
    SHAPE ABUTMENT ;
    NETEXPR "VDD VDD!" ;
    PORT
      LAYER met1 ;
        RECT 0 3.94 4.6 4.34 ;
        RECT 1.675 0.95 1.905 1.24 ;
        RECT 1.28 2.66 1.815 2.8 ;
        RECT 1.675 0.95 1.815 2.8 ;
        RECT 1.28 2.66 1.42 4.34 ;
    END
  END VDD
  PIN VSS
    DIRECTION INPUT ;
    USE GROUND ;
    SHAPE ABUTMENT ;
    NETEXPR "VSS VSS!" ;
    PORT
      LAYER met1 ;
        RECT 0 -0.2 4.6 0.2 ;
        RECT 2.325 2.495 2.555 2.785 ;
        RECT 2.325 -0.2 2.465 2.785 ;
    END
  END VSS
  PIN Y
    DIRECTION OUTPUT ;
    USE SIGNAL ;
    ANTENNADIFFAREA 0.5883 LAYER met1 ;
    PORT
      LAYER met1 ;
        RECT 3.525 0.68 3.81 3.45 ;
        RECT 3.525 0.485 3.755 3.45 ;
    END
  END Y
  OBS
    LAYER met1 ;
      RECT 2.605 2.955 2.835 3.245 ;
      RECT 2.695 0.51 2.835 3.245 ;
      RECT 2.605 1.33 2.835 1.62 ;
      RECT 2.605 0.51 2.835 0.8 ;
      RECT 1.895 2.955 2.185 3.245 ;
      RECT 2.045 0.585 2.185 3.245 ;
      RECT 1.955 1.8 2.185 2.09 ;
      RECT 1.895 0.51 2.125 0.8 ;
      RECT 0.55 2.945 0.835 3.235 ;
      RECT 0.55 0.57 0.72 3.235 ;
      RECT 0.55 1.8 0.835 2.09 ;
      RECT 0.605 0.51 0.835 0.8 ;
  END
  PROPERTY CatenaDesignType "deviceLevel" ;
END DLY1X1_HS

MACRO DLY1X4_HS
  CLASS CORE ;
  ORIGIN 0 0 ;
  FOREIGN DLY1X4_HS 0 0 ;
  SIZE 5.52 BY 4.14 ;
  SYMMETRY X Y ;
  SITE CoreSite ;
  PIN A
    DIRECTION INPUT ;
    USE SIGNAL ;
    ANTENNAMODEL OXIDE1 ;
      ANTENNAGATEAREA 0.18075 LAYER met1 ;
      ANTENNAMAXAREACAR 0.945228 LAYER met1 ;
      ANTENNAMAXSIDEAREACAR 1.112033 LAYER met1 ;
    PORT
      LAYER met1 ;
        RECT 1.25 0.425 1.51 1.665 ;
    END
  END A
  PIN VDD
    DIRECTION INPUT ;
    USE POWER ;
    SHAPE ABUTMENT ;
    NETEXPR "VDD VDD!" ;
    PORT
      LAYER met1 ;
        RECT 0 3.94 5.52 4.34 ;
        RECT 1.185 1.805 1.415 2.095 ;
        RECT 1.215 1.805 1.385 4.34 ;
    END
  END VDD
  PIN VSS
    DIRECTION INPUT ;
    USE GROUND ;
    SHAPE ABUTMENT ;
    NETEXPR "VSS VSS!" ;
    PORT
      LAYER met1 ;
        RECT 0 -0.2 5.52 0.2 ;
        RECT 1.65 -0.2 1.82 2.795 ;
        RECT 1.555 2.31 1.82 2.6 ;
    END
  END VSS
  PIN Y
    DIRECTION OUTPUT ;
    USE SIGNAL ;
    ANTENNADIFFAREA 1.2432 LAYER met1 ;
    PORT
      LAYER met1 ;
        RECT 3.275 3.165 4.365 3.335 ;
        RECT 4.01 0.415 4.365 3.335 ;
        RECT 3.275 0.415 4.365 0.645 ;
        RECT 3.275 0.415 3.505 3.335 ;
    END
  END Y
  OBS
    LAYER met1 ;
      RECT 2.415 3.045 2.645 3.335 ;
      RECT 2.445 0.415 2.615 3.335 ;
      RECT 2.415 1.805 2.645 2.095 ;
      RECT 2.415 0.415 2.645 0.705 ;
      RECT 1.895 3.045 2.125 3.335 ;
      RECT 1.96 0.415 2.13 3.19 ;
      RECT 1.96 1.29 2.19 1.58 ;
      RECT 1.96 0.415 2.19 0.705 ;
      RECT 0.605 3.045 0.835 3.335 ;
      RECT 0.635 0.415 0.805 3.335 ;
      RECT 0.6 1.29 0.83 1.58 ;
      RECT 0.605 0.415 0.835 0.705 ;
  END
  PROPERTY CatenaDesignType "deviceLevel" ;
END DLY1X4_HS

MACRO DLY2X4_HS
  CLASS CORE ;
  ORIGIN 0 0 ;
  FOREIGN DLY2X4_HS 0 0 ;
  SIZE 7.82 BY 4.14 ;
  SYMMETRY X Y ;
  SITE CoreSite ;
  PIN A
    DIRECTION INPUT ;
    USE SIGNAL ;
    ANTENNAMODEL OXIDE1 ;
      ANTENNAGATEAREA 0.18075 LAYER met1 ;
      ANTENNAMAXAREACAR 0.893499 LAYER met1 ;
      ANTENNAMAXSIDEAREACAR 1.051176 LAYER met1 ;
    PORT
      LAYER met1 ;
        RECT 1.25 1.995 1.51 3.235 ;
    END
  END A
  PIN VDD
    DIRECTION INPUT ;
    USE POWER ;
    SHAPE ABUTMENT ;
    NETEXPR "VDD VDD!" ;
    PORT
      LAYER met1 ;
        RECT 0 3.94 7.82 4.34 ;
        RECT 3.615 0.95 3.845 4.34 ;
    END
  END VDD
  PIN VSS
    DIRECTION INPUT ;
    USE GROUND ;
    SHAPE ABUTMENT ;
    NETEXPR "VSS VSS!" ;
    PORT
      LAYER met1 ;
        RECT 0 -0.2 7.82 0.2 ;
        RECT 3.06 -0.2 3.29 2.815 ;
    END
  END VSS
  PIN Y
    DIRECTION OUTPUT ;
    USE SIGNAL ;
    ANTENNADIFFAREA 1.2432 LAYER met1 ;
    PORT
      LAYER met1 ;
        RECT 6.31 0.485 6.605 3.255 ;
        RECT 5.515 1.575 6.605 1.805 ;
        RECT 5.515 0.485 5.745 3.255 ;
    END
  END Y
  OBS
    LAYER met1 ;
      RECT 4.655 0.485 4.885 3.04 ;
      RECT 4.135 0.51 4.365 3.04 ;
      RECT 2.415 0.51 2.645 3.04 ;
      RECT 1.895 0.51 2.125 3.04 ;
      RECT 0.605 0.51 0.835 3.04 ;
  END
  PROPERTY CatenaDesignType "deviceLevel" ;
END DLY2X4_HS

MACRO DLY4X4_HS
  CLASS CORE ;
  ORIGIN 0 0 ;
  FOREIGN DLY4X4_HS 0 0 ;
  SIZE 11.96 BY 4.14 ;
  SYMMETRY X Y ;
  SITE CoreSite ;
  PIN A
    DIRECTION INPUT ;
    USE SIGNAL ;
    ANTENNAMODEL OXIDE1 ;
      ANTENNAGATEAREA 0.18075 LAYER met1 ;
      ANTENNAMAXAREACAR 0.893499 LAYER met1 ;
      ANTENNAMAXSIDEAREACAR 1.051176 LAYER met1 ;
    PORT
      LAYER met1 ;
        RECT 1.25 1.995 1.51 3.235 ;
    END
  END A
  PIN VDD
    DIRECTION INPUT ;
    USE POWER ;
    SHAPE ABUTMENT ;
    NETEXPR "VDD VDD!" ;
    PORT
      LAYER met1 ;
        RECT 0 3.94 11.96 4.34 ;
        RECT 3.615 0.95 3.845 4.34 ;
    END
  END VDD
  PIN VSS
    DIRECTION INPUT ;
    USE GROUND ;
    SHAPE ABUTMENT ;
    NETEXPR "VSS VSS!" ;
    PORT
      LAYER met1 ;
        RECT 0 -0.2 11.965 0.2 ;
        RECT 5.855 -0.2 6.085 2.815 ;
    END
  END VSS
  PIN Y
    DIRECTION OUTPUT ;
    USE SIGNAL ;
    ANTENNADIFFAREA 1.2432 LAYER met1 ;
    PORT
      LAYER met1 ;
        RECT 10.855 0.485 11.17 3.255 ;
        RECT 9.995 1.575 11.17 1.805 ;
        RECT 9.995 0.485 10.225 3.255 ;
    END
  END Y
  OBS
    LAYER met1 ;
      RECT 9.135 0.485 9.365 3.04 ;
      RECT 8.615 0.51 8.845 3.04 ;
      RECT 6.895 0.51 7.125 3.04 ;
      RECT 6.375 0.51 6.605 3.04 ;
      RECT 4.655 0.51 4.885 3.04 ;
      RECT 4.135 0.51 4.365 3.04 ;
      RECT 2.415 0.51 2.645 3.04 ;
      RECT 1.895 0.51 2.125 3.04 ;
      RECT 0.605 0.51 0.835 3.04 ;
  END
  PROPERTY CatenaDesignType "deviceLevel" ;
END DLY4X4_HS

MACRO INVX16_HS
  CLASS CORE ;
  ORIGIN 0 0 ;
  FOREIGN INVX16_HS 0 0 ;
  SIZE 8.28 BY 4.14 ;
  SYMMETRY X Y ;
  SITE CoreSite ;
  PIN A
    DIRECTION INPUT ;
    USE SIGNAL ;
    ANTENNAMODEL OXIDE1 ;
      ANTENNAGATEAREA 5.328 LAYER met1 ;
      ANTENNAMAXAREACAR 0.303594 LAYER met1 ;
      ANTENNAMAXSIDEAREACAR 0.261449 LAYER met1 ;
    PORT
      LAYER met1 ;
        RECT 0.79 1.465 1.05 2.705 ;
    END
  END A
  PIN VDD
    DIRECTION INPUT ;
    USE POWER ;
    SHAPE ABUTMENT ;
    NETEXPR "VDD VDD!" ;
    PORT
      LAYER met1 ;
        RECT 0 3.94 8.28 4.34 ;
    END
  END VDD
  PIN VSS
    DIRECTION INPUT ;
    USE GROUND ;
    SHAPE ABUTMENT ;
    NETEXPR "VSS VSS!" ;
    PORT
      LAYER met1 ;
        RECT 0 -0.2 8.28 0.2 ;
    END
  END VSS
  PIN Y
    DIRECTION OUTPUT ;
    USE SIGNAL ;
    ANTENNADIFFAREA 4.9728 LAYER met1 ;
    PORT
      LAYER met1 ;
        RECT 1.005 3.21 7.315 3.5 ;
        RECT 1.005 0.61 7.315 0.9 ;
        RECT 4.47 0.61 4.73 3.5 ;
    END
  END Y
  PROPERTY CatenaDesignType "deviceLevel" ;
END INVX16_HS

MACRO INVX1_HS
  CLASS CORE ;
  ORIGIN 0 0 ;
  FOREIGN INVX1_HS 0 0 ;
  SIZE 1.84 BY 4.14 ;
  SYMMETRY X Y ;
  SITE CoreSite ;
  PIN A
    DIRECTION INPUT ;
    USE SIGNAL ;
    ANTENNAMODEL OXIDE1 ;
      ANTENNAGATEAREA 0.333 LAYER met1 ;
      ANTENNAMAXAREACAR 0.262913 LAYER met1 ;
      ANTENNAMAXSIDEAREACAR 0.309309 LAYER met1 ;
    PORT
      LAYER met1 ;
        RECT 0.79 1.43 1.05 2.67 ;
    END
  END A
  PIN VDD
    DIRECTION INPUT ;
    USE POWER ;
    SHAPE ABUTMENT ;
    NETEXPR "VDD VDD!" ;
    PORT
      LAYER met1 ;
        RECT 0 3.94 1.84 4.34 ;
    END
  END VDD
  PIN VSS
    DIRECTION INPUT ;
    USE GROUND ;
    SHAPE ABUTMENT ;
    NETEXPR "VSS VSS!" ;
    PORT
      LAYER met1 ;
        RECT 0 -0.2 1.84 0.2 ;
    END
  END VSS
  PIN Y
    DIRECTION OUTPUT ;
    USE SIGNAL ;
    ANTENNADIFFAREA 0.5883 LAYER met1 ;
    PORT
      LAYER met1 ;
        RECT 1.035 2.84 1.51 3.49 ;
        RECT 1.25 0.605 1.51 3.49 ;
        RECT 1.035 0.605 1.51 1.255 ;
    END
  END Y
END INVX1_HS

MACRO INVX2_HS
  CLASS CORE ;
  ORIGIN 0 0 ;
  FOREIGN INVX2_HS 0 0 ;
  SIZE 2.3 BY 4.14 ;
  SYMMETRY X Y ;
  SITE CoreSite ;
  PIN A
    DIRECTION INPUT ;
    USE SIGNAL ;
    ANTENNAMODEL OXIDE1 ;
      ANTENNAGATEAREA 0.666 LAYER met1 ;
      ANTENNAMAXAREACAR 0.320345 LAYER met1 ;
      ANTENNAMAXSIDEAREACAR 0.325826 LAYER met1 ;
    PORT
      LAYER met1 ;
        RECT 0.79 1.29 1.05 2.53 ;
    END
  END A
  PIN VDD
    DIRECTION INPUT ;
    USE POWER ;
    SHAPE ABUTMENT ;
    NETEXPR "VDD VDD!" ;
    PORT
      LAYER met1 ;
        RECT 0 3.94 2.3 4.34 ;
    END
  END VDD
  PIN VSS
    DIRECTION INPUT ;
    USE GROUND ;
    SHAPE ABUTMENT ;
    NETEXPR "VSS VSS!" ;
    PORT
      LAYER met1 ;
        RECT 0 -0.2 2.3 0.2 ;
    END
  END VSS
  PIN Y
    DIRECTION OUTPUT ;
    USE SIGNAL ;
    ANTENNADIFFAREA 0.6216 LAYER met1 ;
    PORT
      LAYER met1 ;
        RECT 1.035 2.735 1.51 3.385 ;
        RECT 1.25 0.61 1.51 3.385 ;
        RECT 1.035 0.61 1.51 0.9 ;
    END
  END Y
  PROPERTY CatenaDesignType "deviceLevel" ;
END INVX2_HS

MACRO INVX4_HS
  CLASS CORE ;
  ORIGIN 0 0 ;
  FOREIGN INVX4_HS 0 0 ;
  SIZE 3.22 BY 4.14 ;
  SYMMETRY X Y ;
  SITE CoreSite ;
  PIN A
    DIRECTION INPUT ;
    USE SIGNAL ;
    ANTENNAMODEL OXIDE1 ;
      ANTENNAGATEAREA 1.332 LAYER met1 ;
      ANTENNAMAXAREACAR 0.259084 LAYER met1 ;
      ANTENNAMAXSIDEAREACAR 0.228228 LAYER met1 ;
    PORT
      LAYER met1 ;
        RECT 1.25 1.455 1.51 2.695 ;
    END
  END A
  PIN VDD
    DIRECTION INPUT ;
    USE POWER ;
    SHAPE ABUTMENT ;
    NETEXPR "VDD VDD!" ;
    PORT
      LAYER met1 ;
        RECT 0 3.94 3.22 4.34 ;
    END
  END VDD
  PIN VSS
    DIRECTION INPUT ;
    USE GROUND ;
    SHAPE ABUTMENT ;
    NETEXPR "VSS VSS!" ;
    PORT
      LAYER met1 ;
        RECT 0 -0.2 3.22 0.2 ;
    END
  END VSS
  PIN Y
    DIRECTION OUTPUT ;
    USE SIGNAL ;
    ANTENNADIFFAREA 1.2432 LAYER met1 ;
    PORT
      LAYER met1 ;
        RECT 1.035 3.24 2.155 3.53 ;
        RECT 1.71 0.61 2.155 3.53 ;
        RECT 1.035 0.61 2.155 0.9 ;
    END
  END Y
  PROPERTY CatenaDesignType "deviceLevel" ;
END INVX4_HS

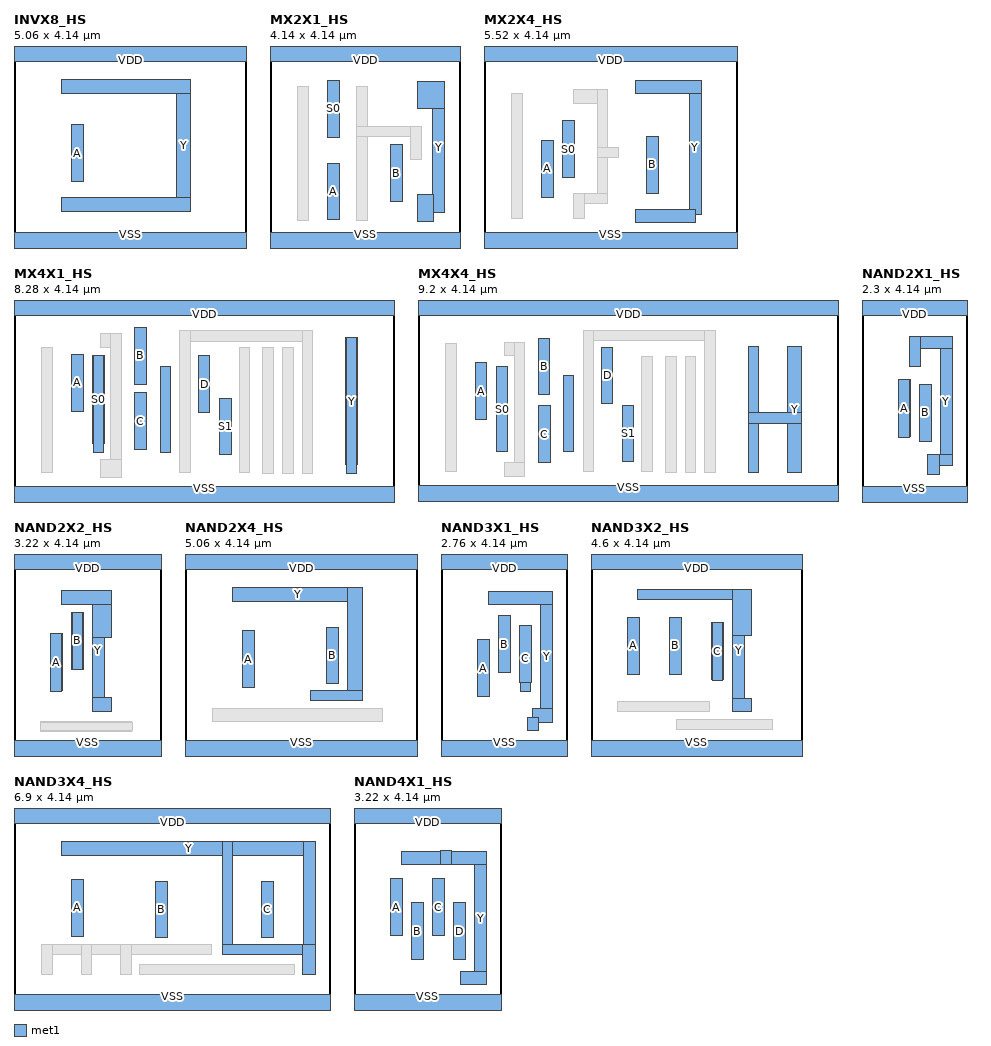
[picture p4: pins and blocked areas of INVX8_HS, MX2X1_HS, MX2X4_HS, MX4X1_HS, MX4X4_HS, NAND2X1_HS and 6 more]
MACRO INVX8_HS
  CLASS CORE ;
  ORIGIN 0 0 ;
  FOREIGN INVX8_HS 0 0 ;
  SIZE 5.06 BY 4.14 ;
  SYMMETRY X Y ;
  SITE CoreSite ;
  PIN A
    DIRECTION INPUT ;
    USE SIGNAL ;
    ANTENNAMODEL OXIDE1 ;
      ANTENNAGATEAREA 2.664 LAYER met1 ;
      ANTENNAMAXAREACAR 0.302477 LAYER met1 ;
      ANTENNAMAXSIDEAREACAR 0.266517 LAYER met1 ;
    PORT
      LAYER met1 ;
        RECT 1.25 1.315 1.51 2.555 ;
    END
  END A
  PIN VDD
    DIRECTION INPUT ;
    USE POWER ;
    SHAPE ABUTMENT ;
    NETEXPR "VDD VDD!" ;
    PORT
      LAYER met1 ;
        RECT 0 3.94 5.06 4.34 ;
    END
  END VDD
  PIN VSS
    DIRECTION INPUT ;
    USE GROUND ;
    SHAPE ABUTMENT ;
    NETEXPR "VSS VSS!" ;
    PORT
      LAYER met1 ;
        RECT 0 -0.2 5.06 0.2 ;
    END
  END VSS
  PIN Y
    DIRECTION OUTPUT ;
    USE SIGNAL ;
    ANTENNADIFFAREA 2.4864 LAYER met1 ;
    PORT
      LAYER met1 ;
        RECT 1.035 3.24 3.845 3.53 ;
        RECT 3.55 0.675 3.845 3.53 ;
        RECT 1.035 0.675 3.845 0.965 ;
    END
  END Y
  PROPERTY CatenaDesignType "deviceLevel" ;
END INVX8_HS

MACRO MX2X1_HS
  CLASS CORE ;
  ORIGIN 0 0 ;
  FOREIGN MX2X1_HS 0 0 ;
  SIZE 4.14 BY 4.14 ;
  SYMMETRY X Y ;
  SITE CoreSite ;
  PIN A
    DIRECTION INPUT ;
    USE SIGNAL ;
    ANTENNAMODEL OXIDE1 ;
      ANTENNAGATEAREA 0.18075 LAYER met1 ;
      ANTENNAMAXAREACAR 0.484371 LAYER met1 ;
      ANTENNAMAXSIDEAREACAR 0.569848 LAYER met1 ;
    PORT
      LAYER met1 ;
        RECT 1.25 0.48 1.51 1.72 ;
    END
  END A
  PIN B
    DIRECTION INPUT ;
    USE SIGNAL ;
    ANTENNAMODEL OXIDE1 ;
      ANTENNAGATEAREA 0.18075 LAYER met1 ;
      ANTENNAMAXAREACAR 0.587828 LAYER met1 ;
      ANTENNAMAXSIDEAREACAR 0.691563 LAYER met1 ;
    PORT
      LAYER met1 ;
        RECT 2.63 0.875 2.89 2.115 ;
    END
  END B
  PIN S0
    DIRECTION INPUT ;
    USE SIGNAL ;
    ANTENNAMODEL OXIDE1 ;
      ANTENNAGATEAREA 0.3615 LAYER met1 ;
      ANTENNAMAXAREACAR 1.991093 LAYER met1 ;
      ANTENNAMAXSIDEAREACAR 1.903181 LAYER met1 ;
    PORT
      LAYER met1 ;
        RECT 1.25 2.28 1.51 3.52 ;
    END
  END S0
  PIN VDD
    DIRECTION INPUT ;
    USE POWER ;
    SHAPE ABUTMENT ;
    NETEXPR "VDD VDD!" ;
    PORT
      LAYER met1 ;
        RECT 0 3.94 4.14 4.34 ;
    END
  END VDD
  PIN VSS
    DIRECTION INPUT ;
    USE GROUND ;
    SHAPE ABUTMENT ;
    NETEXPR "VSS VSS!" ;
    PORT
      LAYER met1 ;
        RECT 0 -0.2 4.14 0.2 ;
    END
  END VSS
  PIN Y
    DIRECTION OUTPUT ;
    USE SIGNAL ;
    ANTENNADIFFAREA 0.5883 LAYER met1 ;
    PORT
      LAYER met1 ;
        RECT 3.215 2.91 3.81 3.5 ;
        RECT 3.55 0.64 3.81 3.5 ;
        RECT 3.215 0.445 3.555 1.035 ;
    END
  END Y
  OBS
    LAYER met1 ;
      RECT 1.895 0.46 2.125 3.38 ;
      RECT 1.895 2.29 3.3 2.52 ;
      RECT 3.07 1.805 3.3 2.52 ;
      RECT 0.605 0.46 0.835 3.38 ;
  END
  PROPERTY CatenaDesignType "deviceLevel" ;
  PROPERTY oaTaper "virtuosoDefaultSetup" ;
END MX2X1_HS

MACRO MX2X4_HS
  CLASS CORE ;
  ORIGIN 0 0 ;
  FOREIGN MX2X4_HS 0 0 ;
  SIZE 5.52 BY 4.14 ;
  SYMMETRY X Y ;
  SITE CoreSite ;
  PIN A
    DIRECTION INPUT ;
    USE SIGNAL ;
    ANTENNAMODEL OXIDE1 ;
      ANTENNAGATEAREA 0.2775 LAYER met1 ;
      ANTENNAMAXAREACAR 0.324685 LAYER met1 ;
      ANTENNAMAXSIDEAREACAR 0.381982 LAYER met1 ;
    PORT
      LAYER met1 ;
        RECT 1.25 0.98 1.51 2.22 ;
    END
  END A
  PIN B
    DIRECTION INPUT ;
    USE SIGNAL ;
    ANTENNAMODEL OXIDE1 ;
      ANTENNAGATEAREA 0.2775 LAYER met1 ;
      ANTENNAMAXAREACAR 0.897477 LAYER met1 ;
      ANTENNAMAXSIDEAREACAR 1.055856 LAYER met1 ;
    PORT
      LAYER met1 ;
        RECT 3.55 1.06 3.81 2.3 ;
    END
  END B
  PIN S0
    DIRECTION INPUT ;
    USE SIGNAL ;
    ANTENNAMODEL OXIDE1 ;
      ANTENNAGATEAREA 0.45825 LAYER met1 ;
      ANTENNAMAXAREACAR 0.727483 LAYER met1 ;
      ANTENNAMAXSIDEAREACAR 0.741953 LAYER met1 ;
    PORT
      LAYER met1 ;
        RECT 1.71 1.405 1.97 2.645 ;
    END
  END S0
  PIN VDD
    DIRECTION INPUT ;
    USE POWER ;
    SHAPE ABUTMENT ;
    NETEXPR "VDD VDD!" ;
    PORT
      LAYER met1 ;
        RECT 0 3.94 5.52 4.34 ;
    END
  END VDD
  PIN VSS
    DIRECTION INPUT ;
    USE GROUND ;
    SHAPE ABUTMENT ;
    NETEXPR "VSS VSS!" ;
    PORT
      LAYER met1 ;
        RECT 0 -0.2 5.52 0.2 ;
    END
  END VSS
  PIN Y
    DIRECTION OUTPUT ;
    USE SIGNAL ;
    ANTENNADIFFAREA 1.2432 LAYER met1 ;
    PORT
      LAYER met1 ;
        RECT 3.305 3.235 4.73 3.525 ;
        RECT 4.47 0.61 4.73 3.525 ;
        RECT 3.305 0.415 4.6 0.705 ;
    END
  END Y
  OBS
    LAYER met1 ;
      RECT 1.955 3.025 2.695 3.315 ;
      RECT 2.465 0.83 2.695 3.315 ;
      RECT 2.465 1.835 2.93 2.065 ;
      RECT 1.955 0.83 2.695 1.06 ;
      RECT 1.955 0.51 2.185 1.06 ;
      RECT 0.605 0.51 0.835 3.235 ;
  END
  PROPERTY CatenaDesignType "deviceLevel" ;
END MX2X4_HS

MACRO MX4X1_HS
  CLASS CORE ;
  ORIGIN 0 0 ;
  FOREIGN MX4X1_HS 0 0 ;
  SIZE 8.28 BY 4.14 ;
  SYMMETRY X Y ;
  SITE CoreSite ;
  PIN A
    DIRECTION INPUT ;
    USE SIGNAL ;
    ANTENNAMODEL OXIDE1 ;
      ANTENNAGATEAREA 0.18075 LAYER met1 ;
      ANTENNAMAXAREACAR 0.681881 LAYER met1 ;
      ANTENNAMAXSIDEAREACAR 0.802213 LAYER met1 ;
    PORT
      LAYER met1 ;
        RECT 1.25 1.85 1.51 3.09 ;
    END
  END A
  PIN B
    DIRECTION INPUT ;
    USE SIGNAL ;
    ANTENNAMODEL OXIDE1 ;
      ANTENNAGATEAREA 0.18075 LAYER met1 ;
      ANTENNAMAXAREACAR 0.771231 LAYER met1 ;
      ANTENNAMAXSIDEAREACAR 0.907331 LAYER met1 ;
    PORT
      LAYER met1 ;
        RECT 2.63 2.435 2.89 3.675 ;
    END
  END B
  PIN C
    DIRECTION INPUT ;
    USE SIGNAL ;
    ANTENNAMODEL OXIDE1 ;
      ANTENNAGATEAREA 0.18075 LAYER met1 ;
      ANTENNAMAXAREACAR 0.775934 LAYER met1 ;
      ANTENNAMAXSIDEAREACAR 0.912863 LAYER met1 ;
    PORT
      LAYER met1 ;
        RECT 2.63 1.005 2.89 2.245 ;
    END
  END C
  PIN D
    DIRECTION INPUT ;
    USE SIGNAL ;
    ANTENNAMODEL OXIDE1 ;
      ANTENNAGATEAREA 0.18075 LAYER met1 ;
      ANTENNAMAXAREACAR 0.893499 LAYER met1 ;
      ANTENNAMAXSIDEAREACAR 1.051176 LAYER met1 ;
    PORT
      LAYER met1 ;
        RECT 4.01 1.815 4.27 3.055 ;
    END
  END D
  PIN S0
    DIRECTION INPUT ;
    USE SIGNAL ;
    ANTENNAPARTIALMETALAREA 0.54275 LAYER met1 ;
    ANTENNAPARTIALMETALSIDEAREA 1.659 LAYER met1 ;
    ANTENNAMODEL OXIDE1 ;
      ANTENNAGATEAREA 0.54225 LAYER met1 ;
      ANTENNAMAXAREACAR 3.30162 LAYER met1 ;
      ANTENNAMAXSIDEAREACAR 5.7005 LAYER met1 ;
    PORT
      LAYER met1 ;
        RECT 3.185 0.95 3.415 2.815 ;
        RECT 1.71 1.15 1.97 3.065 ;
        RECT 1.725 0.955 1.955 3.065 ;
    END
  END S0
  PIN S1
    DIRECTION INPUT ;
    USE SIGNAL ;
    ANTENNAMODEL OXIDE1 ;
      ANTENNAGATEAREA 0.3615 LAYER met1 ;
      ANTENNAMAXAREACAR 0.418534 LAYER met1 ;
      ANTENNAMAXSIDEAREACAR 0.39834 LAYER met1 ;
    PORT
      LAYER met1 ;
        RECT 4.47 0.895 4.73 2.135 ;
    END
  END S1
  PIN VDD
    DIRECTION INPUT ;
    USE POWER ;
    SHAPE ABUTMENT ;
    NETEXPR "VDD VDD!" ;
    PORT
      LAYER met1 ;
        RECT 0 3.94 8.28 4.34 ;
    END
  END VDD
  PIN VSS
    DIRECTION INPUT ;
    USE GROUND ;
    SHAPE ABUTMENT ;
    NETEXPR "VSS VSS!" ;
    PORT
      LAYER met1 ;
        RECT 0 -0.2 8.28 0.2 ;
    END
  END VSS
  PIN Y
    DIRECTION OUTPUT ;
    USE SIGNAL ;
    ANTENNADIFFAREA 0.5883 LAYER met1 ;
    PORT
      LAYER met1 ;
        RECT 7.23 0.68 7.49 3.45 ;
        RECT 7.235 0.485 7.465 3.45 ;
    END
  END Y
  OBS
    LAYER met1 ;
      RECT 3.615 3.375 6.515 3.605 ;
      RECT 6.285 0.485 6.515 3.605 ;
      RECT 3.615 0.51 3.845 3.605 ;
      RECT 1.895 3.24 2.34 3.53 ;
      RECT 2.11 0.395 2.34 3.53 ;
      RECT 1.895 0.395 2.34 0.8 ;
      RECT 5.855 0.485 6.085 3.235 ;
      RECT 5.425 0.485 5.655 3.235 ;
      RECT 4.905 0.51 5.135 3.235 ;
      RECT 0.605 0.51 0.835 3.235 ;
  END
  PROPERTY CatenaDesignType "deviceLevel" ;
END MX4X1_HS

MACRO MX4X4_HS
  CLASS CORE ;
  ORIGIN 0 0 ;
  FOREIGN MX4X4_HS 0 0 ;
  SIZE 9.2 BY 4.14 ;
  SYMMETRY X Y ;
  SITE CoreSite ;
  PIN A
    DIRECTION INPUT ;
    USE SIGNAL ;
    ANTENNAMODEL OXIDE1 ;
      ANTENNAGATEAREA 0.18075 LAYER met1 ;
      ANTENNAMAXAREACAR 0.686584 LAYER met1 ;
      ANTENNAMAXSIDEAREACAR 0.807746 LAYER met1 ;
    PORT
      LAYER met1 ;
        RECT 1.25 1.655 1.51 2.895 ;
    END
  END A
  PIN B
    DIRECTION INPUT ;
    USE SIGNAL ;
    ANTENNAMODEL OXIDE1 ;
      ANTENNAGATEAREA 0.18075 LAYER met1 ;
      ANTENNAMAXAREACAR 0.771231 LAYER met1 ;
      ANTENNAMAXSIDEAREACAR 0.907331 LAYER met1 ;
    PORT
      LAYER met1 ;
        RECT 2.63 2.195 2.89 3.435 ;
    END
  END B
  PIN C
    DIRECTION INPUT ;
    USE SIGNAL ;
    ANTENNAMODEL OXIDE1 ;
      ANTENNAGATEAREA 0.18075 LAYER met1 ;
      ANTENNAMAXAREACAR 0.757123 LAYER met1 ;
      ANTENNAMAXSIDEAREACAR 0.890733 LAYER met1 ;
    PORT
      LAYER met1 ;
        RECT 2.65 0.71 2.91 1.95 ;
    END
  END C
  PIN D
    DIRECTION INPUT ;
    USE SIGNAL ;
    ANTENNAMODEL OXIDE1 ;
      ANTENNAGATEAREA 0.18075 LAYER met1 ;
      ANTENNAMAXAREACAR 0.893499 LAYER met1 ;
      ANTENNAMAXSIDEAREACAR 1.051176 LAYER met1 ;
    PORT
      LAYER met1 ;
        RECT 4.01 1.995 4.27 3.235 ;
    END
  END D
  PIN S0
    DIRECTION INPUT ;
    USE SIGNAL ;
    ANTENNAPARTIALMETALAREA 0.4849 LAYER met1 ;
    ANTENNAPARTIALMETALSIDEAREA 1.4875 LAYER met1 ;
    ANTENNAMODEL OXIDE1 ;
      ANTENNAGATEAREA 0.54225 LAYER met1 ;
      ANTENNAMAXAREACAR 3.189582 LAYER met1 ;
      ANTENNAMAXSIDEAREACAR 5.384225 LAYER met1 ;
    PORT
      LAYER met1 ;
        RECT 3.185 0.95 3.415 2.62 ;
        RECT 1.71 0.95 1.97 2.815 ;
    END
  END S0
  PIN S1
    DIRECTION INPUT ;
    USE SIGNAL ;
    ANTENNAMODEL OXIDE1 ;
      ANTENNAGATEAREA 0.51375 LAYER met1 ;
      ANTENNAMAXAREACAR 0.292847 LAYER met1 ;
      ANTENNAMAXSIDEAREACAR 0.278345 LAYER met1 ;
    PORT
      LAYER met1 ;
        RECT 4.47 0.73 4.73 1.97 ;
    END
  END S1
  PIN VDD
    DIRECTION INPUT ;
    USE POWER ;
    SHAPE ABUTMENT ;
    NETEXPR "VDD VDD!" ;
    PORT
      LAYER met1 ;
        RECT 0 3.94 9.2 4.34 ;
    END
  END VDD
  PIN VSS
    DIRECTION INPUT ;
    USE GROUND ;
    SHAPE ABUTMENT ;
    NETEXPR "VSS VSS!" ;
    PORT
      LAYER met1 ;
        RECT 0 -0.2 9.2 0.2 ;
    END
  END VSS
  PIN Y
    DIRECTION OUTPUT ;
    USE SIGNAL ;
    ANTENNADIFFAREA 1.2432 LAYER met1 ;
    PORT
      LAYER met1 ;
        RECT 8.095 0.485 8.41 3.255 ;
        RECT 7.235 1.575 8.41 1.805 ;
        RECT 7.235 0.485 7.465 3.255 ;
    END
  END Y
  OBS
    LAYER met1 ;
      RECT 3.615 3.375 6.515 3.605 ;
      RECT 6.285 0.485 6.515 3.605 ;
      RECT 3.615 0.51 3.845 3.605 ;
      RECT 1.895 3.045 2.34 3.335 ;
      RECT 2.11 0.415 2.34 3.335 ;
      RECT 1.895 0.415 2.34 0.705 ;
      RECT 5.855 0.485 6.085 3.04 ;
      RECT 5.425 0.485 5.655 3.04 ;
      RECT 4.905 0.51 5.135 3.04 ;
      RECT 0.605 0.51 0.835 3.325 ;
  END
  PROPERTY CatenaDesignType "deviceLevel" ;
END MX4X4_HS

MACRO NAND2X1_HS
  CLASS CORE ;
  ORIGIN 0 0 ;
  FOREIGN NAND2X1_HS 0 0 ;
  SIZE 2.3 BY 4.14 ;
  SYMMETRY X Y ;
  SITE CoreSite ;
  PIN A
    DIRECTION INPUT ;
    USE SIGNAL ;
    ANTENNAMODEL OXIDE1 ;
      ANTENNAGATEAREA 0.333 LAYER met1 ;
      ANTENNAMAXAREACAR 0.365015 LAYER met1 ;
      ANTENNAMAXSIDEAREACAR 0.429429 LAYER met1 ;
    PORT
      LAYER met1 ;
        RECT 0.79 1.29 1.05 2.53 ;
        RECT 0.805 1.285 1.035 2.53 ;
    END
  END A
  PIN B
    DIRECTION INPUT ;
    USE SIGNAL ;
    ANTENNAMODEL OXIDE1 ;
      ANTENNAGATEAREA 0.333 LAYER met1 ;
      ANTENNAMAXAREACAR 0.372673 LAYER met1 ;
      ANTENNAMAXSIDEAREACAR 0.438438 LAYER met1 ;
    PORT
      LAYER met1 ;
        RECT 1.25 1.19 1.51 2.43 ;
    END
  END B
  PIN VDD
    DIRECTION INPUT ;
    USE POWER ;
    SHAPE ABUTMENT ;
    NETEXPR "VDD VDD!" ;
    PORT
      LAYER met1 ;
        RECT 0 3.94 2.3 4.34 ;
    END
  END VDD
  PIN VSS
    DIRECTION INPUT ;
    USE GROUND ;
    SHAPE ABUTMENT ;
    NETEXPR "VSS VSS!" ;
    PORT
      LAYER met1 ;
        RECT 0 -0.2 2.3 0.2 ;
    END
  END VSS
  PIN Y
    DIRECTION OUTPUT ;
    USE SIGNAL ;
    ANTENNADIFFAREA 0.6102 LAYER met1 ;
    PORT
      LAYER met1 ;
        RECT 1.035 3.21 1.97 3.47 ;
        RECT 1.71 0.655 1.97 3.47 ;
        RECT 1.425 0.655 1.97 0.915 ;
        RECT 1.425 0.475 1.695 0.915 ;
        RECT 1.435 0.46 1.695 0.915 ;
        RECT 1.035 2.82 1.265 3.47 ;
    END
  END Y
  PROPERTY CatenaDesignType "deviceLevel" ;
END NAND2X1_HS

MACRO NAND2X2_HS
  CLASS CORE ;
  ORIGIN 0 0 ;
  FOREIGN NAND2X2_HS 0 0 ;
  SIZE 3.22 BY 4.14 ;
  SYMMETRY X Y ;
  SITE CoreSite ;
  PIN A
    DIRECTION INPUT ;
    USE SIGNAL ;
    ANTENNAMODEL OXIDE1 ;
      ANTENNAGATEAREA 0.666 LAYER met1 ;
      ANTENNAMAXAREACAR 0.31524 LAYER met1 ;
      ANTENNAMAXSIDEAREACAR 0.31982 LAYER met1 ;
    PORT
      LAYER met1 ;
        RECT 0.79 1.29 1.05 2.53 ;
        RECT 0.805 1.285 1.035 2.53 ;
    END
  END A
  PIN B
    DIRECTION INPUT ;
    USE SIGNAL ;
    ANTENNAMODEL OXIDE1 ;
      ANTENNAGATEAREA 0.666 LAYER met1 ;
      ANTENNAMAXAREACAR 0.376502 LAYER met1 ;
      ANTENNAMAXSIDEAREACAR 0.391892 LAYER met1 ;
    PORT
      LAYER met1 ;
        RECT 1.25 1.76 1.51 3 ;
        RECT 1.265 1.755 1.495 3 ;
    END
  END B
  PIN VDD
    DIRECTION INPUT ;
    USE POWER ;
    SHAPE ABUTMENT ;
    NETEXPR "VDD VDD!" ;
    PORT
      LAYER met1 ;
        RECT 0 3.94 3.22 4.34 ;
    END
  END VDD
  PIN VSS
    DIRECTION INPUT ;
    USE GROUND ;
    SHAPE ABUTMENT ;
    NETEXPR "VSS VSS!" ;
    PORT
      LAYER met1 ;
        RECT 0 -0.2 3.22 0.2 ;
    END
  END VSS
  PIN Y
    DIRECTION OUTPUT ;
    USE SIGNAL ;
    ANTENNADIFFAREA 1.0304 LAYER met1 ;
    PORT
      LAYER met1 ;
        RECT 1.035 3.18 2.125 3.47 ;
        RECT 1.71 2.46 2.125 3.47 ;
        RECT 1.71 0.845 2.125 1.135 ;
        RECT 1.71 0.845 1.97 3.47 ;
    END
  END Y
  OBS
    LAYER met1 ;
      RECT 0.575 0.395 2.555 0.625 ;
      RECT 0.575 0.425 2.585 0.595 ;
  END
  PROPERTY CatenaDesignType "deviceLevel" ;
END NAND2X2_HS

MACRO NAND2X4_HS
  CLASS CORE ;
  ORIGIN 0 0 ;
  FOREIGN NAND2X4_HS 0 0 ;
  SIZE 5.06 BY 4.14 ;
  SYMMETRY X Y ;
  SITE CoreSite ;
  PIN A
    DIRECTION INPUT ;
    USE SIGNAL ;
    ANTENNAMODEL OXIDE1 ;
      ANTENNAGATEAREA 1.332 LAYER met1 ;
      ANTENNAMAXAREACAR 0.216967 LAYER met1 ;
      ANTENNAMAXSIDEAREACAR 0.204204 LAYER met1 ;
    PORT
      LAYER met1 ;
        RECT 1.25 1.36 1.51 2.6 ;
    END
  END A
  PIN B
    DIRECTION INPUT ;
    USE SIGNAL ;
    ANTENNAMODEL OXIDE1 ;
      ANTENNAGATEAREA 1.332 LAYER met1 ;
      ANTENNAMAXAREACAR 0.216967 LAYER met1 ;
      ANTENNAMAXSIDEAREACAR 0.204204 LAYER met1 ;
    PORT
      LAYER met1 ;
        RECT 3.09 1.44 3.35 2.68 ;
    END
  END B
  PIN VDD
    DIRECTION INPUT ;
    USE POWER ;
    SHAPE ABUTMENT ;
    NETEXPR "VDD VDD!" ;
    PORT
      LAYER met1 ;
        RECT 0 3.94 5.06 4.34 ;
    END
  END VDD
  PIN VSS
    DIRECTION INPUT ;
    USE GROUND ;
    SHAPE ABUTMENT ;
    NETEXPR "VSS VSS!" ;
    PORT
      LAYER met1 ;
        RECT 0 -0.2 5.06 0.2 ;
    END
  END VSS
  PIN Y
    DIRECTION OUTPUT ;
    USE SIGNAL ;
    ANTENNADIFFAREA 2.0608 LAYER met1 ;
    PORT
      LAYER met1 ;
        RECT 1.035 3.24 3.875 3.53 ;
        RECT 3.55 1.07 3.875 3.53 ;
        RECT 2.725 1.07 3.875 1.3 ;
    END
  END Y
  OBS
    LAYER met1 ;
      RECT 0.605 0.615 4.305 0.905 ;
  END
END NAND2X4_HS

MACRO NAND3X1_HS
  CLASS CORE ;
  ORIGIN 0 0 ;
  FOREIGN NAND3X1_HS 0 0 ;
  SIZE 2.76 BY 4.14 ;
  SYMMETRY X Y ;
  SITE CoreSite ;
  PIN A
    DIRECTION INPUT ;
    USE SIGNAL ;
    ANTENNAMODEL OXIDE1 ;
      ANTENNAGATEAREA 0.333 LAYER met1 ;
      ANTENNAMAXAREACAR 0.35991 LAYER met1 ;
      ANTENNAMAXSIDEAREACAR 0.423423 LAYER met1 ;
    PORT
      LAYER met1 ;
        RECT 0.79 1.165 1.05 2.405 ;
    END
  END A
  PIN B
    DIRECTION INPUT ;
    USE SIGNAL ;
    ANTENNAMODEL OXIDE1 ;
      ANTENNAGATEAREA 0.333 LAYER met1 ;
      ANTENNAMAXAREACAR 0.262913 LAYER met1 ;
      ANTENNAMAXSIDEAREACAR 0.309309 LAYER met1 ;
    PORT
      LAYER met1 ;
        RECT 1.25 1.685 1.51 2.925 ;
    END
  END B
  PIN C
    DIRECTION INPUT ;
    USE SIGNAL ;
    ANTENNAMODEL OXIDE1 ;
      ANTENNAGATEAREA 0.333 LAYER met1 ;
      ANTENNAMAXAREACAR 0.395646 LAYER met1 ;
      ANTENNAMAXSIDEAREACAR 0.465465 LAYER met1 ;
    PORT
      LAYER met1 ;
        RECT 1.71 1.47 1.97 2.71 ;
        RECT 1.725 1.285 1.955 2.71 ;
    END
  END C
  PIN VDD
    DIRECTION INPUT ;
    USE POWER ;
    SHAPE ABUTMENT ;
    NETEXPR "VDD VDD!" ;
    PORT
      LAYER met1 ;
        RECT 0 3.94 2.76 4.34 ;
    END
  END VDD
  PIN VSS
    DIRECTION INPUT ;
    USE GROUND ;
    SHAPE ABUTMENT ;
    NETEXPR "VSS VSS!" ;
    PORT
      LAYER met1 ;
        RECT 0 -0.2 2.76 0.2 ;
    END
  END VSS
  PIN Y
    DIRECTION OUTPUT ;
    USE SIGNAL ;
    ANTENNADIFFAREA 0.9971 LAYER met1 ;
    PORT
      LAYER met1 ;
        RECT 1.035 3.16 2.43 3.45 ;
        RECT 2.17 0.61 2.43 3.45 ;
        RECT 1.995 0.61 2.43 0.9 ;
        RECT 1.895 0.415 2.125 0.705 ;
    END
  END Y
  PROPERTY CatenaDesignType "deviceLevel" ;
END NAND3X1_HS

MACRO NAND3X2_HS
  CLASS CORE ;
  ORIGIN 0 0 ;
  FOREIGN NAND3X2_HS 0 0 ;
  SIZE 4.6 BY 4.14 ;
  SYMMETRY X Y ;
  SITE CoreSite ;
  PIN A
    DIRECTION INPUT ;
    USE SIGNAL ;
    ANTENNAMODEL OXIDE1 ;
      ANTENNAGATEAREA 0.666 LAYER met1 ;
      ANTENNAMAXAREACAR 0.336937 LAYER met1 ;
      ANTENNAMAXSIDEAREACAR 0.345345 LAYER met1 ;
    PORT
      LAYER met1 ;
        RECT 0.79 1.65 1.05 2.89 ;
    END
  END A
  PIN B
    DIRECTION INPUT ;
    USE SIGNAL ;
    ANTENNAMODEL OXIDE1 ;
      ANTENNAGATEAREA 0.666 LAYER met1 ;
      ANTENNAMAXAREACAR 0.321622 LAYER met1 ;
      ANTENNAMAXSIDEAREACAR 0.327327 LAYER met1 ;
    PORT
      LAYER met1 ;
        RECT 1.71 1.65 1.97 2.89 ;
    END
  END B
  PIN C
    DIRECTION INPUT ;
    USE SIGNAL ;
    ANTENNAMODEL OXIDE1 ;
      ANTENNAGATEAREA 0.666 LAYER met1 ;
      ANTENNAMAXAREACAR 0.363739 LAYER met1 ;
      ANTENNAMAXSIDEAREACAR 0.376877 LAYER met1 ;
    PORT
      LAYER met1 ;
        RECT 2.63 1.53 2.89 2.77 ;
        RECT 2.645 1.52 2.875 2.77 ;
    END
  END C
  PIN VDD
    DIRECTION INPUT ;
    USE POWER ;
    SHAPE ABUTMENT ;
    NETEXPR "VDD VDD!" ;
    PORT
      LAYER met1 ;
        RECT 0 3.94 4.6 4.34 ;
    END
  END VDD
  PIN VSS
    DIRECTION INPUT ;
    USE GROUND ;
    SHAPE ABUTMENT ;
    NETEXPR "VSS VSS!" ;
    PORT
      LAYER met1 ;
        RECT 0 -0.2 4.6 0.2 ;
    END
  END VSS
  PIN Y
    DIRECTION OUTPUT ;
    USE SIGNAL ;
    ANTENNADIFFAREA 1.4392 LAYER met1 ;
    PORT
      LAYER met1 ;
        RECT 1.005 3.27 3.505 3.5 ;
        RECT 3.09 2.49 3.505 3.5 ;
        RECT 3.09 0.83 3.505 1.12 ;
        RECT 3.09 0.83 3.35 3.5 ;
    END
  END Y
  OBS
    LAYER met1 ;
      RECT 1.865 0.445 3.965 0.675 ;
      RECT 0.575 0.83 2.585 1.06 ;
  END
  PROPERTY CatenaDesignType "deviceLevel" ;
END NAND3X2_HS

MACRO NAND3X4_HS
  CLASS CORE ;
  ORIGIN 0 0 ;
  FOREIGN NAND3X4_HS 0 0 ;
  SIZE 6.9 BY 4.14 ;
  SYMMETRY X Y ;
  SITE CoreSite ;
  PIN A
    DIRECTION INPUT ;
    USE SIGNAL ;
    ANTENNAMODEL OXIDE1 ;
      ANTENNAGATEAREA 1.332 LAYER met1 ;
      ANTENNAMAXAREACAR 0.216967 LAYER met1 ;
      ANTENNAMAXSIDEAREACAR 0.204204 LAYER met1 ;
    PORT
      LAYER met1 ;
        RECT 1.25 1.48 1.51 2.72 ;
    END
  END A
  PIN B
    DIRECTION INPUT ;
    USE SIGNAL ;
    ANTENNAMODEL OXIDE1 ;
      ANTENNAGATEAREA 1.332 LAYER met1 ;
      ANTENNAMAXAREACAR 0.216967 LAYER met1 ;
      ANTENNAMAXSIDEAREACAR 0.204204 LAYER met1 ;
    PORT
      LAYER met1 ;
        RECT 3.09 1.44 3.35 2.68 ;
    END
  END B
  PIN C
    DIRECTION INPUT ;
    USE SIGNAL ;
    ANTENNAMODEL OXIDE1 ;
      ANTENNAGATEAREA 1.332 LAYER met1 ;
      ANTENNAMAXAREACAR 0.216967 LAYER met1 ;
      ANTENNAMAXSIDEAREACAR 0.204204 LAYER met1 ;
    PORT
      LAYER met1 ;
        RECT 5.39 1.44 5.65 2.68 ;
    END
  END C
  PIN VDD
    DIRECTION INPUT ;
    USE POWER ;
    SHAPE ABUTMENT ;
    NETEXPR "VDD VDD!" ;
    PORT
      LAYER met1 ;
        RECT 0 3.94 6.9 4.34 ;
    END
  END VDD
  PIN VSS
    DIRECTION INPUT ;
    USE GROUND ;
    SHAPE ABUTMENT ;
    NETEXPR "VSS VSS!" ;
    PORT
      LAYER met1 ;
        RECT 0 -0.2 6.9 0.2 ;
    END
  END VSS
  PIN Y
    DIRECTION OUTPUT ;
    USE SIGNAL ;
    ANTENNADIFFAREA 3.0684 LAYER met1 ;
    PORT
      LAYER met1 ;
        RECT 1.035 3.24 6.57 3.53 ;
        RECT 6.31 0.65 6.57 3.53 ;
        RECT 4.535 1.07 6.57 1.3 ;
        RECT 6.285 0.65 6.57 1.3 ;
        RECT 4.535 1.07 4.765 3.53 ;
    END
  END Y
  OBS
    LAYER met1 ;
      RECT 0.605 1.07 4.305 1.3 ;
      RECT 2.325 0.65 2.555 1.3 ;
      RECT 1.465 0.65 1.695 1.3 ;
      RECT 0.605 0.65 0.835 1.3 ;
      RECT 2.725 0.64 6.115 0.87 ;
  END
END NAND3X4_HS

MACRO NAND4X1_HS
  CLASS CORE ;
  ORIGIN 0 0 ;
  FOREIGN NAND4X1_HS 0 0 ;
  SIZE 3.22 BY 4.14 ;
  SYMMETRY X Y ;
  SITE CoreSite ;
  PIN A
    DIRECTION INPUT ;
    USE SIGNAL ;
    ANTENNAMODEL OXIDE1 ;
      ANTENNAGATEAREA 0.333 LAYER met1 ;
      ANTENNAMAXAREACAR 0.37012 LAYER met1 ;
      ANTENNAMAXSIDEAREACAR 0.435435 LAYER met1 ;
    PORT
      LAYER met1 ;
        RECT 0.79 1.49 1.05 2.73 ;
    END
  END A
  PIN B
    DIRECTION INPUT ;
    USE SIGNAL ;
    ANTENNAMODEL OXIDE1 ;
      ANTENNAGATEAREA 0.333 LAYER met1 ;
      ANTENNAMAXAREACAR 0.372673 LAYER met1 ;
      ANTENNAMAXSIDEAREACAR 0.438438 LAYER met1 ;
    PORT
      LAYER met1 ;
        RECT 1.25 0.97 1.51 2.21 ;
    END
  END B
  PIN C
    DIRECTION INPUT ;
    USE SIGNAL ;
    ANTENNAMODEL OXIDE1 ;
      ANTENNAGATEAREA 0.333 LAYER met1 ;
      ANTENNAMAXAREACAR 0.387988 LAYER met1 ;
      ANTENNAMAXSIDEAREACAR 0.456456 LAYER met1 ;
    PORT
      LAYER met1 ;
        RECT 1.71 1.49 1.97 2.73 ;
    END
  END C
  PIN D
    DIRECTION INPUT ;
    USE SIGNAL ;
    ANTENNAMODEL OXIDE1 ;
      ANTENNAGATEAREA 0.333 LAYER met1 ;
      ANTENNAMAXAREACAR 0.403303 LAYER met1 ;
      ANTENNAMAXSIDEAREACAR 0.474474 LAYER met1 ;
    PORT
      LAYER met1 ;
        RECT 2.17 0.97 2.43 2.21 ;
    END
  END D
  PIN VDD
    DIRECTION INPUT ;
    USE POWER ;
    SHAPE ABUTMENT ;
    NETEXPR "VDD VDD!" ;
    PORT
      LAYER met1 ;
        RECT 0 3.94 3.22 4.34 ;
    END
  END VDD
  PIN VSS
    DIRECTION INPUT ;
    USE GROUND ;
    SHAPE ABUTMENT ;
    NETEXPR "VSS VSS!" ;
    PORT
      LAYER met1 ;
        RECT 0 -0.2 3.22 0.2 ;
    END
  END VSS
  PIN Y
    DIRECTION OUTPUT ;
    USE SIGNAL ;
    ANTENNADIFFAREA 1.019 LAYER met1 ;
    PORT
      LAYER met1 ;
        RECT 1.035 3.035 2.89 3.325 ;
        RECT 2.63 0.415 2.89 3.325 ;
        RECT 2.325 0.415 2.89 0.705 ;
        RECT 1.895 3.035 2.125 3.335 ;
    END
  END Y
  PROPERTY CatenaDesignType "deviceLevel" ;
END NAND4X1_HS

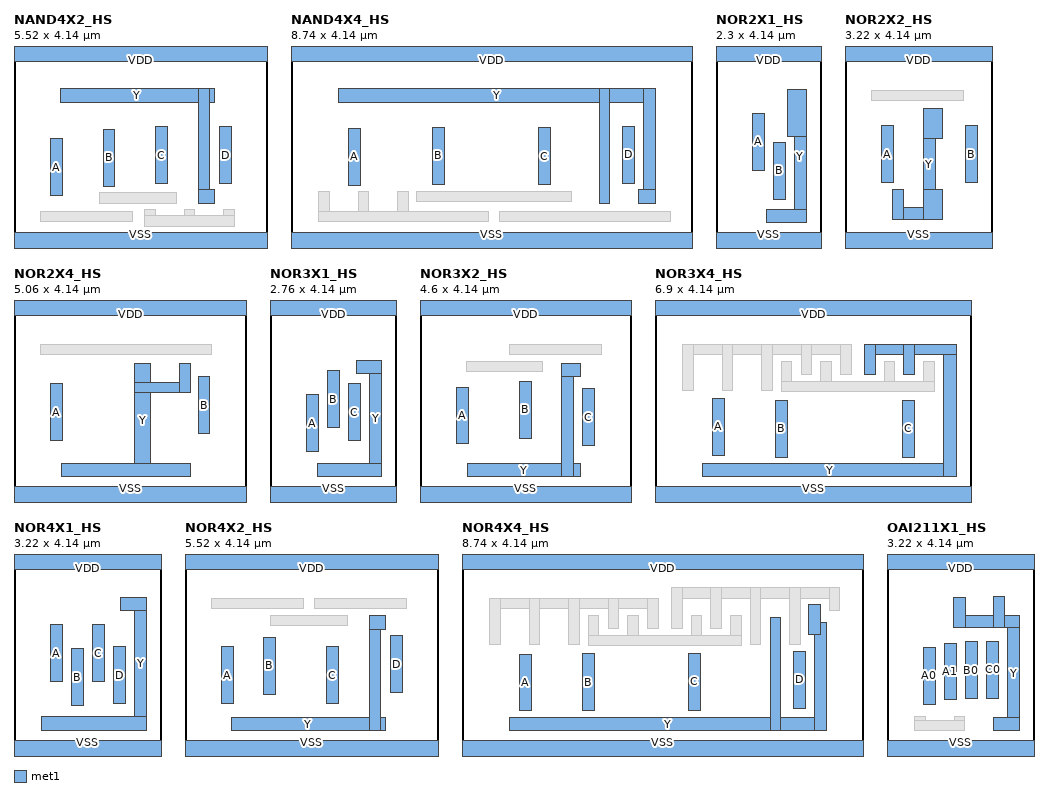
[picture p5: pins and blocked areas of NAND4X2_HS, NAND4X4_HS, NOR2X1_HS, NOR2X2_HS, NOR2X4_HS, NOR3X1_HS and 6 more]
MACRO NAND4X2_HS
  CLASS CORE ;
  ORIGIN 0 0 ;
  FOREIGN NAND4X2_HS 0 0 ;
  SIZE 5.52 BY 4.14 ;
  SYMMETRY X Y ;
  SITE CoreSite ;
  PIN A
    DIRECTION INPUT ;
    USE SIGNAL ;
    ANTENNAMODEL OXIDE1 ;
      ANTENNAGATEAREA 0.666 LAYER met1 ;
      ANTENNAMAXAREACAR 0.274399 LAYER met1 ;
      ANTENNAMAXSIDEAREACAR 0.271772 LAYER met1 ;
    PORT
      LAYER met1 ;
        RECT 0.79 1.01 1.05 2.25 ;
    END
  END A
  PIN B
    DIRECTION INPUT ;
    USE SIGNAL ;
    ANTENNAMODEL OXIDE1 ;
      ANTENNAGATEAREA 0.666 LAYER met1 ;
      ANTENNAMAXAREACAR 0.26036 LAYER met1 ;
      ANTENNAMAXSIDEAREACAR 0.255255 LAYER met1 ;
    PORT
      LAYER met1 ;
        RECT 1.94 1.22 2.2 2.46 ;
    END
  END B
  PIN C
    DIRECTION INPUT ;
    USE SIGNAL ;
    ANTENNAMODEL OXIDE1 ;
      ANTENNAGATEAREA 0.666 LAYER met1 ;
      ANTENNAMAXAREACAR 0.26036 LAYER met1 ;
      ANTENNAMAXSIDEAREACAR 0.255255 LAYER met1 ;
    PORT
      LAYER met1 ;
        RECT 3.09 1.275 3.35 2.515 ;
    END
  END C
  PIN D
    DIRECTION INPUT ;
    USE SIGNAL ;
    ANTENNAMODEL OXIDE1 ;
      ANTENNAGATEAREA 0.666 LAYER met1 ;
      ANTENNAMAXAREACAR 0.28461 LAYER met1 ;
      ANTENNAMAXSIDEAREACAR 0.334835 LAYER met1 ;
    PORT
      LAYER met1 ;
        RECT 4.47 1.275 4.73 2.515 ;
    END
  END D
  PIN VDD
    DIRECTION INPUT ;
    USE POWER ;
    SHAPE ABUTMENT ;
    NETEXPR "VDD VDD!" ;
    PORT
      LAYER met1 ;
        RECT 0 3.94 5.52 4.34 ;
    END
  END VDD
  PIN VSS
    DIRECTION INPUT ;
    USE GROUND ;
    SHAPE ABUTMENT ;
    NETEXPR "VSS VSS!" ;
    PORT
      LAYER met1 ;
        RECT 0 -0.2 5.52 0.2 ;
    END
  END VSS
  PIN Y
    DIRECTION OUTPUT ;
    USE SIGNAL ;
    ANTENNADIFFAREA 1.848 LAYER met1 ;
    PORT
      LAYER met1 ;
        RECT 1.005 3.045 4.365 3.335 ;
        RECT 4.01 0.845 4.365 1.135 ;
        RECT 4.01 0.845 4.27 3.335 ;
    END
  END Y
  OBS
    LAYER met1 ;
      RECT 4.565 0.34 4.795 0.705 ;
      RECT 3.705 0.34 3.935 0.705 ;
      RECT 2.845 0.34 3.075 0.705 ;
      RECT 2.845 0.34 4.795 0.57 ;
      RECT 1.865 0.845 3.535 1.075 ;
      RECT 0.575 0.445 2.585 0.675 ;
  END
  PROPERTY CatenaDesignType "deviceLevel" ;
END NAND4X2_HS

MACRO NAND4X4_HS
  CLASS CORE ;
  ORIGIN 0 0 ;
  FOREIGN NAND4X4_HS 0 0 ;
  SIZE 8.74 BY 4.14 ;
  SYMMETRY X Y ;
  SITE CoreSite ;
  PIN A
    DIRECTION INPUT ;
    USE SIGNAL ;
    ANTENNAMODEL OXIDE1 ;
      ANTENNAGATEAREA 1.332 LAYER met1 ;
      ANTENNAMAXAREACAR 0.216967 LAYER met1 ;
      ANTENNAMAXSIDEAREACAR 0.204204 LAYER met1 ;
    PORT
      LAYER met1 ;
        RECT 1.25 1.235 1.51 2.475 ;
    END
  END A
  PIN B
    DIRECTION INPUT ;
    USE SIGNAL ;
    ANTENNAMODEL OXIDE1 ;
      ANTENNAGATEAREA 1.332 LAYER met1 ;
      ANTENNAMAXAREACAR 0.216967 LAYER met1 ;
      ANTENNAMAXSIDEAREACAR 0.204204 LAYER met1 ;
    PORT
      LAYER met1 ;
        RECT 3.09 1.255 3.35 2.495 ;
    END
  END B
  PIN C
    DIRECTION INPUT ;
    USE SIGNAL ;
    ANTENNAMODEL OXIDE1 ;
      ANTENNAGATEAREA 1.332 LAYER met1 ;
      ANTENNAMAXAREACAR 0.216967 LAYER met1 ;
      ANTENNAMAXSIDEAREACAR 0.204204 LAYER met1 ;
    PORT
      LAYER met1 ;
        RECT 5.39 1.245 5.65 2.485 ;
    END
  END C
  PIN D
    DIRECTION INPUT ;
    USE SIGNAL ;
    ANTENNAMODEL OXIDE1 ;
      ANTENNAGATEAREA 1.332 LAYER met1 ;
      ANTENNAMAXAREACAR 0.216967 LAYER met1 ;
      ANTENNAMAXSIDEAREACAR 0.204204 LAYER met1 ;
    PORT
      LAYER met1 ;
        RECT 7.23 1.28 7.49 2.52 ;
    END
  END D
  PIN VDD
    DIRECTION INPUT ;
    USE POWER ;
    SHAPE ABUTMENT ;
    NETEXPR "VDD VDD!" ;
    PORT
      LAYER met1 ;
        RECT 0 3.94 8.74 4.34 ;
    END
  END VDD
  PIN VSS
    DIRECTION INPUT ;
    USE GROUND ;
    SHAPE ABUTMENT ;
    NETEXPR "VSS VSS!" ;
    PORT
      LAYER met1 ;
        RECT 0 -0.2 8.74 0.2 ;
    END
  END VSS
  PIN Y
    DIRECTION OUTPUT ;
    USE SIGNAL ;
    ANTENNADIFFAREA 3.696 LAYER met1 ;
    PORT
      LAYER met1 ;
        RECT 1.035 3.045 7.95 3.335 ;
        RECT 7.69 0.845 7.95 3.335 ;
        RECT 7.575 0.845 7.95 1.135 ;
        RECT 6.715 0.845 6.945 3.335 ;
    END
  END Y
  OBS
    LAYER met1 ;
      RECT 2.325 0.445 2.555 1.095 ;
      RECT 1.465 0.445 1.695 1.095 ;
      RECT 0.605 0.445 0.835 1.095 ;
      RECT 0.605 0.445 4.305 0.675 ;
      RECT 4.535 0.445 8.265 0.675 ;
      RECT 2.725 0.875 6.115 1.105 ;
  END
END NAND4X4_HS

MACRO NOR2X1_HS
  CLASS CORE ;
  ORIGIN 0 0 ;
  FOREIGN NOR2X1_HS 0 0 ;
  SIZE 2.3 BY 4.14 ;
  SYMMETRY X Y ;
  SITE CoreSite ;
  PIN A
    DIRECTION INPUT ;
    USE SIGNAL ;
    ANTENNAMODEL OXIDE1 ;
      ANTENNAGATEAREA 0.333 LAYER met1 ;
      ANTENNAMAXAREACAR 0.283333 LAYER met1 ;
      ANTENNAMAXSIDEAREACAR 0.333333 LAYER met1 ;
    PORT
      LAYER met1 ;
        RECT 0.79 1.565 1.05 2.805 ;
    END
  END A
  PIN B
    DIRECTION INPUT ;
    USE SIGNAL ;
    ANTENNAMODEL OXIDE1 ;
      ANTENNAGATEAREA 0.333 LAYER met1 ;
      ANTENNAMAXAREACAR 0.293544 LAYER met1 ;
      ANTENNAMAXSIDEAREACAR 0.345345 LAYER met1 ;
    PORT
      LAYER met1 ;
        RECT 1.25 0.93 1.51 2.17 ;
    END
  END B
  PIN VDD
    DIRECTION INPUT ;
    USE POWER ;
    SHAPE ABUTMENT ;
    NETEXPR "VDD VDD!" ;
    PORT
      LAYER met1 ;
        RECT 0 3.94 2.3 4.34 ;
    END
  END VDD
  PIN VSS
    DIRECTION INPUT ;
    USE GROUND ;
    SHAPE ABUTMENT ;
    NETEXPR "VSS VSS!" ;
    PORT
      LAYER met1 ;
        RECT 0 -0.2 2.3 0.2 ;
    END
  END VSS
  PIN Y
    DIRECTION OUTPUT ;
    USE SIGNAL ;
    ANTENNADIFFAREA 0.6885 LAYER met1 ;
    PORT
      LAYER met1 ;
        RECT 1.565 2.305 1.97 3.315 ;
        RECT 1.71 0.425 1.97 3.315 ;
        RECT 1.095 0.425 1.97 0.715 ;
    END
  END Y
  PROPERTY CatenaDesignType "deviceLevel" ;
END NOR2X1_HS

MACRO NOR2X2_HS
  CLASS CORE ;
  ORIGIN 0 0 ;
  FOREIGN NOR2X2_HS 0 0 ;
  SIZE 3.22 BY 4.14 ;
  SYMMETRY X Y ;
  SITE CoreSite ;
  PIN A
    DIRECTION INPUT ;
    USE SIGNAL ;
    ANTENNAMODEL OXIDE1 ;
      ANTENNAGATEAREA 0.666 LAYER met1 ;
      ANTENNAMAXAREACAR 0.274399 LAYER met1 ;
      ANTENNAMAXSIDEAREACAR 0.271772 LAYER met1 ;
    PORT
      LAYER met1 ;
        RECT 0.79 1.295 1.05 2.535 ;
    END
  END A
  PIN B
    DIRECTION INPUT ;
    USE SIGNAL ;
    ANTENNAMODEL OXIDE1 ;
      ANTENNAGATEAREA 0.666 LAYER met1 ;
      ANTENNAMAXAREACAR 0.407132 LAYER met1 ;
      ANTENNAMAXSIDEAREACAR 0.427928 LAYER met1 ;
    PORT
      LAYER met1 ;
        RECT 2.63 1.295 2.89 2.535 ;
    END
  END B
  PIN VDD
    DIRECTION INPUT ;
    USE POWER ;
    SHAPE ABUTMENT ;
    NETEXPR "VDD VDD!" ;
    PORT
      LAYER met1 ;
        RECT 0 3.94 3.22 4.34 ;
    END
  END VDD
  PIN VSS
    DIRECTION INPUT ;
    USE GROUND ;
    SHAPE ABUTMENT ;
    NETEXPR "VSS VSS!" ;
    PORT
      LAYER met1 ;
        RECT 0 -0.2 3.22 0.2 ;
    END
  END VSS
  PIN Y
    DIRECTION OUTPUT ;
    USE SIGNAL ;
    ANTENNADIFFAREA 0.8344 LAYER met1 ;
    PORT
      LAYER met1 ;
        RECT 1.71 2.25 2.125 2.9 ;
        RECT 1.71 0.485 2.125 1.135 ;
        RECT 1.71 0.485 1.97 2.9 ;
        RECT 1.035 0.485 2.125 0.745 ;
        RECT 1.035 0.485 1.265 1.135 ;
    END
  END Y
  OBS
    LAYER met1 ;
      RECT 0.57 3.075 2.585 3.305 ;
  END
  PROPERTY CatenaDesignType "deviceLevel" ;
END NOR2X2_HS

MACRO NOR2X4_HS
  CLASS CORE ;
  ORIGIN 0 0 ;
  FOREIGN NOR2X4_HS 0 0 ;
  SIZE 5.06 BY 4.14 ;
  SYMMETRY X Y ;
  SITE CoreSite ;
  PIN A
    DIRECTION INPUT ;
    USE SIGNAL ;
    ANTENNAMODEL OXIDE1 ;
      ANTENNAGATEAREA 1.332 LAYER met1 ;
      ANTENNAMAXAREACAR 0.292905 LAYER met1 ;
      ANTENNAMAXSIDEAREACAR 0.268018 LAYER met1 ;
    PORT
      LAYER met1 ;
        RECT 0.79 1.21 1.05 2.45 ;
    END
  END A
  PIN B
    DIRECTION INPUT ;
    USE SIGNAL ;
    ANTENNAMODEL OXIDE1 ;
      ANTENNAGATEAREA 1.332 LAYER met1 ;
      ANTENNAMAXAREACAR 0.315878 LAYER met1 ;
      ANTENNAMAXSIDEAREACAR 0.295045 LAYER met1 ;
    PORT
      LAYER met1 ;
        RECT 4.01 1.36 4.27 2.6 ;
    END
  END B
  PIN VDD
    DIRECTION INPUT ;
    USE POWER ;
    SHAPE ABUTMENT ;
    NETEXPR "VDD VDD!" ;
    PORT
      LAYER met1 ;
        RECT 0 3.94 5.06 4.34 ;
    END
  END VDD
  PIN VSS
    DIRECTION INPUT ;
    USE GROUND ;
    SHAPE ABUTMENT ;
    NETEXPR "VSS VSS!" ;
    PORT
      LAYER met1 ;
        RECT 0 -0.2 5.06 0.2 ;
    END
  END VSS
  PIN Y
    DIRECTION OUTPUT ;
    USE SIGNAL ;
    ANTENNADIFFAREA 1.6688 LAYER met1 ;
    PORT
      LAYER met1 ;
        RECT 3.615 2.245 3.845 2.895 ;
        RECT 1.035 0.415 3.845 0.705 ;
        RECT 2.63 2.245 3.845 2.475 ;
        RECT 2.63 0.415 2.985 2.895 ;
    END
  END Y
  OBS
    LAYER met1 ;
      RECT 0.575 3.075 4.305 3.305 ;
  END
  PROPERTY CatenaDesignType "deviceLevel" ;
END NOR2X4_HS

MACRO NOR3X1_HS
  CLASS CORE ;
  ORIGIN 0 0 ;
  FOREIGN NOR3X1_HS 0 0 ;
  SIZE 2.76 BY 4.14 ;
  SYMMETRY X Y ;
  SITE CoreSite ;
  PIN A
    DIRECTION INPUT ;
    USE SIGNAL ;
    ANTENNAMODEL OXIDE1 ;
      ANTENNAGATEAREA 0.333 LAYER met1 ;
      ANTENNAMAXAREACAR 0.37012 LAYER met1 ;
      ANTENNAMAXSIDEAREACAR 0.435435 LAYER met1 ;
    PORT
      LAYER met1 ;
        RECT 0.79 0.97 1.05 2.21 ;
    END
  END A
  PIN B
    DIRECTION INPUT ;
    USE SIGNAL ;
    ANTENNAMODEL OXIDE1 ;
      ANTENNAGATEAREA 0.333 LAYER met1 ;
      ANTENNAMAXAREACAR 0.372673 LAYER met1 ;
      ANTENNAMAXSIDEAREACAR 0.438438 LAYER met1 ;
    PORT
      LAYER met1 ;
        RECT 1.25 1.49 1.51 2.73 ;
    END
  END B
  PIN C
    DIRECTION INPUT ;
    USE SIGNAL ;
    ANTENNAMODEL OXIDE1 ;
      ANTENNAGATEAREA 0.333 LAYER met1 ;
      ANTENNAMAXAREACAR 0.387988 LAYER met1 ;
      ANTENNAMAXSIDEAREACAR 0.456456 LAYER met1 ;
    PORT
      LAYER met1 ;
        RECT 1.71 1.205 1.97 2.445 ;
    END
  END C
  PIN VDD
    DIRECTION INPUT ;
    USE POWER ;
    SHAPE ABUTMENT ;
    NETEXPR "VDD VDD!" ;
    PORT
      LAYER met1 ;
        RECT 0 3.94 2.76 4.34 ;
    END
  END VDD
  PIN VSS
    DIRECTION INPUT ;
    USE GROUND ;
    SHAPE ABUTMENT ;
    NETEXPR "VSS VSS!" ;
    PORT
      LAYER met1 ;
        RECT 0 -0.2 2.76 0.2 ;
    END
  END VSS
  PIN Y
    DIRECTION OUTPUT ;
    USE SIGNAL ;
    ANTENNADIFFAREA 0.8011 LAYER met1 ;
    PORT
      LAYER met1 ;
        RECT 1.895 2.67 2.43 2.96 ;
        RECT 2.17 0.415 2.43 2.96 ;
        RECT 1.035 0.415 2.43 0.705 ;
    END
  END Y
  PROPERTY CatenaDesignType "deviceLevel" ;
END NOR3X1_HS

MACRO NOR3X2_HS
  CLASS CORE ;
  ORIGIN 0 0 ;
  FOREIGN NOR3X2_HS 0 0 ;
  SIZE 4.6 BY 4.14 ;
  SYMMETRY X Y ;
  SITE CoreSite ;
  PIN A
    DIRECTION INPUT ;
    USE SIGNAL ;
    ANTENNAMODEL OXIDE1 ;
      ANTENNAGATEAREA 0.666 LAYER met1 ;
      ANTENNAMAXAREACAR 0.336937 LAYER met1 ;
      ANTENNAMAXSIDEAREACAR 0.345345 LAYER met1 ;
    PORT
      LAYER met1 ;
        RECT 0.79 1.135 1.05 2.375 ;
    END
  END A
  PIN B
    DIRECTION INPUT ;
    USE SIGNAL ;
    ANTENNAMODEL OXIDE1 ;
      ANTENNAGATEAREA 0.666 LAYER met1 ;
      ANTENNAMAXAREACAR 0.336937 LAYER met1 ;
      ANTENNAMAXSIDEAREACAR 0.345345 LAYER met1 ;
    PORT
      LAYER met1 ;
        RECT 2.17 1.26 2.43 2.5 ;
    END
  END B
  PIN C
    DIRECTION INPUT ;
    USE SIGNAL ;
    ANTENNAMODEL OXIDE1 ;
      ANTENNAGATEAREA 0.666 LAYER met1 ;
      ANTENNAMAXAREACAR 0.276952 LAYER met1 ;
      ANTENNAMAXSIDEAREACAR 0.274775 LAYER met1 ;
    PORT
      LAYER met1 ;
        RECT 3.55 1.1 3.81 2.34 ;
    END
  END C
  PIN VDD
    DIRECTION INPUT ;
    USE POWER ;
    SHAPE ABUTMENT ;
    NETEXPR "VDD VDD!" ;
    PORT
      LAYER met1 ;
        RECT 0 3.94 4.6 4.34 ;
    END
  END VDD
  PIN VSS
    DIRECTION INPUT ;
    USE GROUND ;
    SHAPE ABUTMENT ;
    NETEXPR "VSS VSS!" ;
    PORT
      LAYER met1 ;
        RECT 0 -0.2 4.6 0.2 ;
    END
  END VSS
  PIN Y
    DIRECTION OUTPUT ;
    USE SIGNAL ;
    ANTENNADIFFAREA 1.0472 LAYER met1 ;
    PORT
      LAYER met1 ;
        RECT 3.09 2.605 3.505 2.895 ;
        RECT 1.035 0.415 3.505 0.705 ;
        RECT 3.09 0.415 3.35 2.895 ;
    END
  END Y
  OBS
    LAYER met1 ;
      RECT 1.955 3.075 3.965 3.305 ;
      RECT 1.005 2.705 2.675 2.935 ;
  END
  PROPERTY CatenaDesignType "deviceLevel" ;
END NOR3X2_HS

MACRO NOR3X4_HS
  CLASS CORE ;
  ORIGIN 0 0 ;
  FOREIGN NOR3X4_HS 0 0 ;
  SIZE 6.9 BY 4.14 ;
  SYMMETRY X Y ;
  SITE CoreSite ;
  PIN A
    DIRECTION INPUT ;
    USE SIGNAL ;
    ANTENNAMODEL OXIDE1 ;
      ANTENNAGATEAREA 1.332 LAYER met1 ;
      ANTENNAMAXAREACAR 0.216967 LAYER met1 ;
      ANTENNAMAXSIDEAREACAR 0.204204 LAYER met1 ;
    PORT
      LAYER met1 ;
        RECT 1.25 0.89 1.51 2.13 ;
    END
  END A
  PIN B
    DIRECTION INPUT ;
    USE SIGNAL ;
    ANTENNAMODEL OXIDE1 ;
      ANTENNAGATEAREA 1.332 LAYER met1 ;
      ANTENNAMAXAREACAR 0.230368 LAYER met1 ;
      ANTENNAMAXSIDEAREACAR 0.21997 LAYER met1 ;
    PORT
      LAYER met1 ;
        RECT 2.635 0.845 2.895 2.085 ;
    END
  END B
  PIN C
    DIRECTION INPUT ;
    USE SIGNAL ;
    ANTENNAMODEL OXIDE1 ;
      ANTENNAGATEAREA 1.332 LAYER met1 ;
      ANTENNAMAXAREACAR 0.216967 LAYER met1 ;
      ANTENNAMAXSIDEAREACAR 0.204204 LAYER met1 ;
    PORT
      LAYER met1 ;
        RECT 5.39 0.845 5.65 2.085 ;
    END
  END C
  PIN VDD
    DIRECTION INPUT ;
    USE POWER ;
    SHAPE ABUTMENT ;
    NETEXPR "VDD VDD!" ;
    PORT
      LAYER met1 ;
        RECT 0 3.94 6.9 4.34 ;
    END
  END VDD
  PIN VSS
    DIRECTION INPUT ;
    USE GROUND ;
    SHAPE ABUTMENT ;
    NETEXPR "VSS VSS!" ;
    PORT
      LAYER met1 ;
        RECT 0 -0.2 6.9 0.2 ;
    END
  END VSS
  PIN Y
    DIRECTION OUTPUT ;
    USE SIGNAL ;
    ANTENNADIFFAREA 2.4594 LAYER met1 ;
    PORT
      LAYER met1 ;
        RECT 4.565 3.075 6.57 3.305 ;
        RECT 6.285 0.415 6.57 3.305 ;
        RECT 1.035 0.415 6.57 0.705 ;
        RECT 5.425 2.655 5.655 3.305 ;
        RECT 4.565 2.655 4.795 3.305 ;
    END
  END Y
  OBS
    LAYER met1 ;
      RECT 5.855 2.275 6.085 2.925 ;
      RECT 4.995 2.275 5.225 2.925 ;
      RECT 3.615 2.275 3.845 2.925 ;
      RECT 2.755 2.275 2.985 2.925 ;
      RECT 2.755 2.275 6.085 2.505 ;
      RECT 0.605 3.075 4.275 3.305 ;
      RECT 4.045 2.655 4.275 3.305 ;
      RECT 3.185 2.655 3.415 3.305 ;
      RECT 2.325 2.295 2.555 3.305 ;
      RECT 1.465 2.295 1.695 3.305 ;
      RECT 0.605 2.295 0.835 3.305 ;
  END
END NOR3X4_HS

MACRO NOR4X1_HS
  CLASS CORE ;
  ORIGIN 0 0 ;
  FOREIGN NOR4X1_HS 0 0 ;
  SIZE 3.22 BY 4.14 ;
  SYMMETRY X Y ;
  SITE CoreSite ;
  PIN A
    DIRECTION INPUT ;
    USE SIGNAL ;
    ANTENNAMODEL OXIDE1 ;
      ANTENNAGATEAREA 0.333 LAYER met1 ;
      ANTENNAMAXAREACAR 0.37012 LAYER met1 ;
      ANTENNAMAXSIDEAREACAR 0.435435 LAYER met1 ;
    PORT
      LAYER met1 ;
        RECT 0.79 1.49 1.05 2.73 ;
    END
  END A
  PIN B
    DIRECTION INPUT ;
    USE SIGNAL ;
    ANTENNAMODEL OXIDE1 ;
      ANTENNAGATEAREA 0.333 LAYER met1 ;
      ANTENNAMAXAREACAR 0.372673 LAYER met1 ;
      ANTENNAMAXSIDEAREACAR 0.438438 LAYER met1 ;
    PORT
      LAYER met1 ;
        RECT 1.25 0.97 1.51 2.21 ;
    END
  END B
  PIN C
    DIRECTION INPUT ;
    USE SIGNAL ;
    ANTENNAMODEL OXIDE1 ;
      ANTENNAGATEAREA 0.333 LAYER met1 ;
      ANTENNAMAXAREACAR 0.387988 LAYER met1 ;
      ANTENNAMAXSIDEAREACAR 0.456456 LAYER met1 ;
    PORT
      LAYER met1 ;
        RECT 1.71 1.49 1.97 2.73 ;
    END
  END C
  PIN D
    DIRECTION INPUT ;
    USE SIGNAL ;
    ANTENNAMODEL OXIDE1 ;
      ANTENNAGATEAREA 0.333 LAYER met1 ;
      ANTENNAMAXAREACAR 0.403303 LAYER met1 ;
      ANTENNAMAXSIDEAREACAR 0.474474 LAYER met1 ;
    PORT
      LAYER met1 ;
        RECT 2.17 1.01 2.43 2.25 ;
    END
  END D
  PIN VDD
    DIRECTION INPUT ;
    USE POWER ;
    SHAPE ABUTMENT ;
    NETEXPR "VDD VDD!" ;
    PORT
      LAYER met1 ;
        RECT 0 3.94 3.22 4.34 ;
    END
  END VDD
  PIN VSS
    DIRECTION INPUT ;
    USE GROUND ;
    SHAPE ABUTMENT ;
    NETEXPR "VSS VSS!" ;
    PORT
      LAYER met1 ;
        RECT 0 -0.2 3.22 0.2 ;
    END
  END VSS
  PIN Y
    DIRECTION OUTPUT ;
    USE SIGNAL ;
    ANTENNADIFFAREA 1.0025 LAYER met1 ;
    PORT
      LAYER met1 ;
        RECT 2.325 3.04 2.89 3.33 ;
        RECT 2.63 0.43 2.89 3.33 ;
        RECT 0.605 0.43 2.89 0.72 ;
    END
  END Y
  PROPERTY CatenaDesignType "deviceLevel" ;
END NOR4X1_HS

MACRO NOR4X2_HS
  CLASS CORE ;
  ORIGIN 0 0 ;
  FOREIGN NOR4X2_HS 0 0 ;
  SIZE 5.52 BY 4.14 ;
  SYMMETRY X Y ;
  SITE CoreSite ;
  PIN A
    DIRECTION INPUT ;
    USE SIGNAL ;
    ANTENNAMODEL OXIDE1 ;
      ANTENNAGATEAREA 0.666 LAYER met1 ;
      ANTENNAMAXAREACAR 0.274399 LAYER met1 ;
      ANTENNAMAXSIDEAREACAR 0.271772 LAYER met1 ;
    PORT
      LAYER met1 ;
        RECT 0.79 1.01 1.05 2.25 ;
    END
  END A
  PIN B
    DIRECTION INPUT ;
    USE SIGNAL ;
    ANTENNAMODEL OXIDE1 ;
      ANTENNAGATEAREA 0.666 LAYER met1 ;
      ANTENNAMAXAREACAR 0.26036 LAYER met1 ;
      ANTENNAMAXSIDEAREACAR 0.255255 LAYER met1 ;
    PORT
      LAYER met1 ;
        RECT 1.71 1.22 1.97 2.46 ;
    END
  END B
  PIN C
    DIRECTION INPUT ;
    USE SIGNAL ;
    ANTENNAMODEL OXIDE1 ;
      ANTENNAGATEAREA 0.666 LAYER met1 ;
      ANTENNAMAXAREACAR 0.26036 LAYER met1 ;
      ANTENNAMAXSIDEAREACAR 0.255255 LAYER met1 ;
    PORT
      LAYER met1 ;
        RECT 3.09 1.01 3.35 2.25 ;
    END
  END C
  PIN D
    DIRECTION INPUT ;
    USE SIGNAL ;
    ANTENNAMODEL OXIDE1 ;
      ANTENNAGATEAREA 0.666 LAYER met1 ;
      ANTENNAMAXAREACAR 0.328003 LAYER met1 ;
      ANTENNAMAXSIDEAREACAR 0.334835 LAYER met1 ;
    PORT
      LAYER met1 ;
        RECT 4.47 1.245 4.73 2.485 ;
    END
  END D
  PIN VDD
    DIRECTION INPUT ;
    USE POWER ;
    SHAPE ABUTMENT ;
    NETEXPR "VDD VDD!" ;
    PORT
      LAYER met1 ;
        RECT 0 3.94 5.52 4.34 ;
    END
  END VDD
  PIN VSS
    DIRECTION INPUT ;
    USE GROUND ;
    SHAPE ABUTMENT ;
    NETEXPR "VSS VSS!" ;
    PORT
      LAYER met1 ;
        RECT 0 -0.2 5.52 0.2 ;
    END
  END VSS
  PIN Y
    DIRECTION OUTPUT ;
    USE SIGNAL ;
    ANTENNADIFFAREA 1.26 LAYER met1 ;
    PORT
      LAYER met1 ;
        RECT 4.01 2.635 4.365 2.925 ;
        RECT 1.005 0.415 4.365 0.705 ;
        RECT 4.01 0.415 4.27 2.925 ;
    END
  END Y
  OBS
    LAYER met1 ;
      RECT 2.815 3.075 4.825 3.305 ;
      RECT 1.865 2.705 3.535 2.935 ;
      RECT 0.575 3.075 2.585 3.305 ;
  END
  PROPERTY CatenaDesignType "deviceLevel" ;
END NOR4X2_HS

MACRO NOR4X4_HS
  CLASS CORE ;
  ORIGIN 0 0 ;
  FOREIGN NOR4X4_HS 0 0 ;
  SIZE 8.74 BY 4.14 ;
  SYMMETRY X Y ;
  SITE CoreSite ;
  PIN A
    DIRECTION INPUT ;
    USE SIGNAL ;
    ANTENNAMODEL OXIDE1 ;
      ANTENNAGATEAREA 1.332 LAYER met1 ;
      ANTENNAMAXAREACAR 0.216967 LAYER met1 ;
      ANTENNAMAXSIDEAREACAR 0.204204 LAYER met1 ;
    PORT
      LAYER met1 ;
        RECT 1.25 0.85 1.51 2.09 ;
    END
  END A
  PIN B
    DIRECTION INPUT ;
    USE SIGNAL ;
    ANTENNAMODEL OXIDE1 ;
      ANTENNAGATEAREA 1.332 LAYER met1 ;
      ANTENNAMAXAREACAR 0.230368 LAYER met1 ;
      ANTENNAMAXSIDEAREACAR 0.21997 LAYER met1 ;
    PORT
      LAYER met1 ;
        RECT 2.635 0.855 2.895 2.095 ;
    END
  END B
  PIN C
    DIRECTION INPUT ;
    USE SIGNAL ;
    ANTENNAMODEL OXIDE1 ;
      ANTENNAGATEAREA 1.332 LAYER met1 ;
      ANTENNAMAXAREACAR 0.223348 LAYER met1 ;
      ANTENNAMAXSIDEAREACAR 0.211712 LAYER met1 ;
    PORT
      LAYER met1 ;
        RECT 4.93 0.87 5.19 2.11 ;
    END
  END C
  PIN D
    DIRECTION INPUT ;
    USE SIGNAL ;
    ANTENNAMODEL OXIDE1 ;
      ANTENNAGATEAREA 1.332 LAYER met1 ;
      ANTENNAMAXAREACAR 0.216967 LAYER met1 ;
      ANTENNAMAXSIDEAREACAR 0.204204 LAYER met1 ;
    PORT
      LAYER met1 ;
        RECT 7.23 0.91 7.49 2.15 ;
    END
  END D
  PIN VDD
    DIRECTION INPUT ;
    USE POWER ;
    SHAPE ABUTMENT ;
    NETEXPR "VDD VDD!" ;
    PORT
      LAYER met1 ;
        RECT 0 3.94 8.74 4.34 ;
    END
  END VDD
  PIN VSS
    DIRECTION INPUT ;
    USE GROUND ;
    SHAPE ABUTMENT ;
    NETEXPR "VSS VSS!" ;
    PORT
      LAYER met1 ;
        RECT 0 -0.2 8.74 0.2 ;
    END
  END VSS
  PIN Y
    DIRECTION OUTPUT ;
    USE SIGNAL ;
    ANTENNADIFFAREA 2.52 LAYER met1 ;
    PORT
      LAYER met1 ;
        RECT 7.69 0.415 7.95 2.775 ;
        RECT 7.56 2.515 7.82 3.165 ;
        RECT 1.035 0.415 7.95 0.705 ;
        RECT 6.715 0.415 6.945 2.895 ;
    END
  END Y
  OBS
    LAYER met1 ;
      RECT 4.565 3.305 8.235 3.535 ;
      RECT 8.005 3.045 8.235 3.535 ;
      RECT 7.145 2.295 7.375 3.535 ;
      RECT 6.285 2.295 6.515 3.535 ;
      RECT 5.425 2.655 5.655 3.535 ;
      RECT 4.565 2.655 4.795 3.535 ;
      RECT 5.855 2.275 6.085 2.925 ;
      RECT 4.995 2.275 5.225 2.925 ;
      RECT 3.615 2.275 3.845 2.925 ;
      RECT 2.755 2.275 2.985 2.925 ;
      RECT 2.755 2.275 6.085 2.505 ;
      RECT 0.605 3.075 4.275 3.305 ;
      RECT 4.045 2.655 4.275 3.305 ;
      RECT 3.185 2.655 3.415 3.305 ;
      RECT 2.325 2.295 2.555 3.305 ;
      RECT 1.465 2.295 1.695 3.305 ;
      RECT 0.605 2.295 0.835 3.305 ;
  END
END NOR4X4_HS

MACRO OAI211X1_HS
  CLASS CORE ;
  ORIGIN 0 0 ;
  FOREIGN OAI211X1_HS 0 0 ;
  SIZE 3.22 BY 4.14 ;
  SYMMETRY X Y ;
  SITE CoreSite ;
  PIN A0
    DIRECTION INPUT ;
    USE SIGNAL ;
    ANTENNAMODEL OXIDE1 ;
      ANTENNAGATEAREA 0.333 LAYER met1 ;
      ANTENNAMAXAREACAR 0.262913 LAYER met1 ;
      ANTENNAMAXSIDEAREACAR 0.309309 LAYER met1 ;
    PORT
      LAYER met1 ;
        RECT 0.79 0.995 1.05 2.235 ;
    END
  END A0
  PIN A1
    DIRECTION INPUT ;
    USE SIGNAL ;
    ANTENNAMODEL OXIDE1 ;
      ANTENNAGATEAREA 0.333 LAYER met1 ;
      ANTENNAMAXAREACAR 0.290991 LAYER met1 ;
      ANTENNAMAXSIDEAREACAR 0.342342 LAYER met1 ;
    PORT
      LAYER met1 ;
        RECT 1.25 1.09 1.51 2.33 ;
    END
  END A1
  PIN B0
    DIRECTION INPUT ;
    USE SIGNAL ;
    ANTENNAMODEL OXIDE1 ;
      ANTENNAGATEAREA 0.333 LAYER met1 ;
      ANTENNAMAXAREACAR 0.306306 LAYER met1 ;
      ANTENNAMAXSIDEAREACAR 0.36036 LAYER met1 ;
    PORT
      LAYER met1 ;
        RECT 1.71 1.115 1.97 2.355 ;
    END
  END B0
  PIN C0
    DIRECTION INPUT ;
    USE SIGNAL ;
    ANTENNAMODEL OXIDE1 ;
      ANTENNAGATEAREA 0.333 LAYER met1 ;
      ANTENNAMAXAREACAR 0.303754 LAYER met1 ;
      ANTENNAMAXSIDEAREACAR 0.357357 LAYER met1 ;
    PORT
      LAYER met1 ;
        RECT 2.17 1.125 2.43 2.365 ;
    END
  END C0
  PIN VDD
    DIRECTION INPUT ;
    USE POWER ;
    SHAPE ABUTMENT ;
    NETEXPR "VDD VDD!" ;
    PORT
      LAYER met1 ;
        RECT 0 3.94 3.22 4.34 ;
    END
  END VDD
  PIN VSS
    DIRECTION INPUT ;
    USE GROUND ;
    SHAPE ABUTMENT ;
    NETEXPR "VSS VSS!" ;
    PORT
      LAYER met1 ;
        RECT 0 -0.2 3.22 0.2 ;
    END
  END VSS
  PIN Y
    DIRECTION OUTPUT ;
    USE SIGNAL ;
    ANTENNADIFFAREA 0.9971 LAYER met1 ;
    PORT
      LAYER met1 ;
        RECT 1.45 2.67 2.89 2.93 ;
        RECT 2.63 0.415 2.89 2.93 ;
        RECT 2.31 0.415 2.89 0.71 ;
        RECT 2.325 2.67 2.555 3.335 ;
        RECT 1.45 2.67 1.71 3.32 ;
    END
  END Y
  OBS
    LAYER met1 ;
      RECT 1.465 0.415 1.695 0.74 ;
      RECT 0.605 0.415 0.835 0.74 ;
      RECT 0.605 0.415 1.695 0.645 ;
  END
  PROPERTY CatenaDesignType "deviceLevel" ;
END OAI211X1_HS

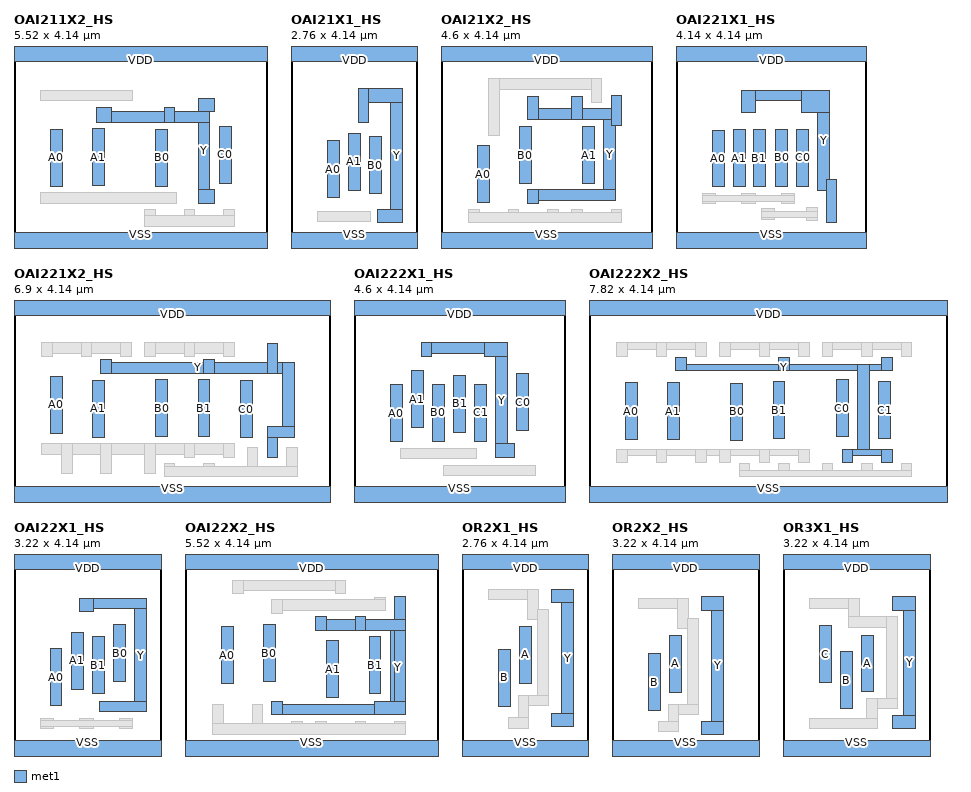
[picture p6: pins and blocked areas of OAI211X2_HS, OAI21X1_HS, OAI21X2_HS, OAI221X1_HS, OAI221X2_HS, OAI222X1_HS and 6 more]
MACRO OAI211X2_HS
  CLASS CORE ;
  ORIGIN 0 0 ;
  FOREIGN OAI211X2_HS 0 0 ;
  SIZE 5.52 BY 4.14 ;
  SYMMETRY X Y ;
  SITE CoreSite ;
  PIN A0
    DIRECTION INPUT ;
    USE SIGNAL ;
    ANTENNAMODEL OXIDE1 ;
      ANTENNAGATEAREA 0.666 LAYER met1 ;
      ANTENNAMAXAREACAR 0.274399 LAYER met1 ;
      ANTENNAMAXSIDEAREACAR 0.271772 LAYER met1 ;
    PORT
      LAYER met1 ;
        RECT 0.79 1.22 1.05 2.46 ;
    END
  END A0
  PIN A1
    DIRECTION INPUT ;
    USE SIGNAL ;
    ANTENNAMODEL OXIDE1 ;
      ANTENNAGATEAREA 0.666 LAYER met1 ;
      ANTENNAMAXAREACAR 0.26036 LAYER met1 ;
      ANTENNAMAXSIDEAREACAR 0.255255 LAYER met1 ;
    PORT
      LAYER met1 ;
        RECT 1.71 1.225 1.97 2.465 ;
    END
  END A1
  PIN B0
    DIRECTION INPUT ;
    USE SIGNAL ;
    ANTENNAMODEL OXIDE1 ;
      ANTENNAGATEAREA 0.666 LAYER met1 ;
      ANTENNAMAXAREACAR 0.26036 LAYER met1 ;
      ANTENNAMAXSIDEAREACAR 0.255255 LAYER met1 ;
    PORT
      LAYER met1 ;
        RECT 3.09 1.215 3.35 2.455 ;
    END
  END B0
  PIN C0
    DIRECTION INPUT ;
    USE SIGNAL ;
    ANTENNAMODEL OXIDE1 ;
      ANTENNAGATEAREA 0.666 LAYER met1 ;
      ANTENNAMAXAREACAR 0.328003 LAYER met1 ;
      ANTENNAMAXSIDEAREACAR 0.334835 LAYER met1 ;
    PORT
      LAYER met1 ;
        RECT 4.47 1.285 4.73 2.525 ;
    END
  END C0
  PIN VDD
    DIRECTION INPUT ;
    USE POWER ;
    SHAPE ABUTMENT ;
    NETEXPR "VDD VDD!" ;
    PORT
      LAYER met1 ;
        RECT 0 3.94 5.52 4.34 ;
    END
  END VDD
  PIN VSS
    DIRECTION INPUT ;
    USE GROUND ;
    SHAPE ABUTMENT ;
    NETEXPR "VSS VSS!" ;
    PORT
      LAYER met1 ;
        RECT 0 -0.2 5.52 0.2 ;
    END
  END VSS
  PIN Y
    DIRECTION OUTPUT ;
    USE SIGNAL ;
    ANTENNADIFFAREA 1.4392 LAYER met1 ;
    PORT
      LAYER met1 ;
        RECT 4.01 2.84 4.365 3.13 ;
        RECT 4.01 0.845 4.365 1.135 ;
        RECT 1.8 2.61 4.27 2.84 ;
        RECT 4.01 0.845 4.27 3.13 ;
        RECT 3.275 2.61 3.505 2.935 ;
        RECT 1.8 2.61 2.125 2.935 ;
    END
  END Y
  OBS
    LAYER met1 ;
      RECT 4.565 0.34 4.795 0.705 ;
      RECT 3.705 0.34 3.935 0.705 ;
      RECT 2.845 0.34 3.075 0.705 ;
      RECT 2.845 0.34 4.795 0.57 ;
      RECT 0.575 0.845 3.535 1.075 ;
      RECT 0.575 3.075 2.585 3.305 ;
  END
  PROPERTY CatenaDesignType "deviceLevel" ;
END OAI211X2_HS

MACRO OAI21X1_HS
  CLASS CORE ;
  ORIGIN 0 0 ;
  FOREIGN OAI21X1_HS 0 0 ;
  SIZE 2.76 BY 4.14 ;
  SYMMETRY X Y ;
  SITE CoreSite ;
  PIN A0
    DIRECTION INPUT ;
    USE SIGNAL ;
    ANTENNAMODEL OXIDE1 ;
      ANTENNAGATEAREA 0.333 LAYER met1 ;
      ANTENNAMAXAREACAR 0.37012 LAYER met1 ;
      ANTENNAMAXSIDEAREACAR 0.435435 LAYER met1 ;
    PORT
      LAYER met1 ;
        RECT 0.79 0.97 1.05 2.21 ;
    END
  END A0
  PIN A1
    DIRECTION INPUT ;
    USE SIGNAL ;
    ANTENNAMODEL OXIDE1 ;
      ANTENNAGATEAREA 0.333 LAYER met1 ;
      ANTENNAMAXAREACAR 0.37012 LAYER met1 ;
      ANTENNAMAXSIDEAREACAR 0.435435 LAYER met1 ;
    PORT
      LAYER met1 ;
        RECT 1.25 1.13 1.51 2.37 ;
    END
  END A1
  PIN B0
    DIRECTION INPUT ;
    USE SIGNAL ;
    ANTENNAMODEL OXIDE1 ;
      ANTENNAGATEAREA 0.333 LAYER met1 ;
      ANTENNAMAXAREACAR 0.387988 LAYER met1 ;
      ANTENNAMAXSIDEAREACAR 0.456456 LAYER met1 ;
    PORT
      LAYER met1 ;
        RECT 1.71 1.05 1.97 2.29 ;
    END
  END B0
  PIN VDD
    DIRECTION INPUT ;
    USE POWER ;
    SHAPE ABUTMENT ;
    NETEXPR "VDD VDD!" ;
    PORT
      LAYER met1 ;
        RECT 0 3.94 2.76 4.34 ;
    END
  END VDD
  PIN VSS
    DIRECTION INPUT ;
    USE GROUND ;
    SHAPE ABUTMENT ;
    NETEXPR "VSS VSS!" ;
    PORT
      LAYER met1 ;
        RECT 0 -0.2 2.76 0.2 ;
    END
  END VSS
  PIN Y
    DIRECTION OUTPUT ;
    USE SIGNAL ;
    ANTENNADIFFAREA 0.6102 LAYER met1 ;
    PORT
      LAYER met1 ;
        RECT 1.465 3.045 2.43 3.335 ;
        RECT 2.17 0.415 2.43 3.335 ;
        RECT 1.895 0.415 2.43 0.705 ;
        RECT 1.465 2.6 1.695 3.335 ;
    END
  END Y
  OBS
    LAYER met1 ;
      RECT 0.575 0.445 1.725 0.675 ;
  END
  PROPERTY CatenaDesignType "deviceLevel" ;
END OAI21X1_HS

MACRO OAI21X2_HS
  CLASS CORE ;
  ORIGIN 0 0 ;
  FOREIGN OAI21X2_HS 0 0 ;
  SIZE 4.6 BY 4.14 ;
  SYMMETRY X Y ;
  SITE CoreSite ;
  PIN A0
    DIRECTION INPUT ;
    USE SIGNAL ;
    ANTENNAMODEL OXIDE1 ;
      ANTENNAGATEAREA 0.666 LAYER met1 ;
      ANTENNAMAXAREACAR 0.274399 LAYER met1 ;
      ANTENNAMAXSIDEAREACAR 0.271772 LAYER met1 ;
    PORT
      LAYER met1 ;
        RECT 0.79 0.86 1.05 2.1 ;
    END
  END A0
  PIN A1
    DIRECTION INPUT ;
    USE SIGNAL ;
    ANTENNAMODEL OXIDE1 ;
      ANTENNAGATEAREA 0.666 LAYER met1 ;
      ANTENNAMAXAREACAR 0.26036 LAYER met1 ;
      ANTENNAMAXSIDEAREACAR 0.255255 LAYER met1 ;
    PORT
      LAYER met1 ;
        RECT 3.09 1.275 3.35 2.515 ;
    END
  END A1
  PIN B0
    DIRECTION INPUT ;
    USE SIGNAL ;
    ANTENNAMODEL OXIDE1 ;
      ANTENNAGATEAREA 0.666 LAYER met1 ;
      ANTENNAMAXAREACAR 0.26036 LAYER met1 ;
      ANTENNAMAXSIDEAREACAR 0.255255 LAYER met1 ;
    PORT
      LAYER met1 ;
        RECT 1.71 1.275 1.97 2.515 ;
    END
  END B0
  PIN VDD
    DIRECTION INPUT ;
    USE POWER ;
    SHAPE ABUTMENT ;
    NETEXPR "VDD VDD!" ;
    PORT
      LAYER met1 ;
        RECT 0 3.94 4.6 4.34 ;
    END
  END VDD
  PIN VSS
    DIRECTION INPUT ;
    USE GROUND ;
    SHAPE ABUTMENT ;
    NETEXPR "VSS VSS!" ;
    PORT
      LAYER met1 ;
        RECT 0 -0.2 4.6 0.2 ;
    END
  END VSS
  PIN Y
    DIRECTION OUTPUT ;
    USE SIGNAL ;
    ANTENNADIFFAREA 1.3954 LAYER met1 ;
    PORT
      LAYER met1 ;
        RECT 3.705 2.535 3.935 3.185 ;
        RECT 3.55 0.905 3.81 2.905 ;
        RECT 1.895 2.675 3.935 2.905 ;
        RECT 1.895 0.905 3.81 1.135 ;
        RECT 2.845 2.675 3.075 3.17 ;
        RECT 1.895 2.675 2.125 3.17 ;
        RECT 1.895 0.845 2.125 1.135 ;
    END
  END Y
  OBS
    LAYER met1 ;
      RECT 3.705 0.415 3.935 0.705 ;
      RECT 2.845 0.415 3.075 0.705 ;
      RECT 2.325 0.415 2.555 0.705 ;
      RECT 1.465 0.415 1.695 0.705 ;
      RECT 0.605 0.415 0.835 0.705 ;
      RECT 0.605 0.415 3.935 0.645 ;
      RECT 1.035 3.325 3.505 3.555 ;
      RECT 3.275 3.045 3.505 3.555 ;
      RECT 1.035 2.325 1.265 3.555 ;
  END
  PROPERTY CatenaDesignType "deviceLevel" ;
END OAI21X2_HS

MACRO OAI221X1_HS
  CLASS CORE ;
  ORIGIN 0 0 ;
  FOREIGN OAI221X1_HS 0 0 ;
  SIZE 4.14 BY 4.14 ;
  SYMMETRY X Y ;
  SITE CoreSite ;
  PIN A0
    DIRECTION INPUT ;
    USE SIGNAL ;
    ANTENNAMODEL OXIDE1 ;
      ANTENNAGATEAREA 0.333 LAYER met1 ;
      ANTENNAMAXAREACAR 0.298649 LAYER met1 ;
      ANTENNAMAXSIDEAREACAR 0.351351 LAYER met1 ;
    PORT
      LAYER met1 ;
        RECT 0.79 1.2 1.05 2.44 ;
    END
  END A0
  PIN A1
    DIRECTION INPUT ;
    USE SIGNAL ;
    ANTENNAMODEL OXIDE1 ;
      ANTENNAGATEAREA 0.333 LAYER met1 ;
      ANTENNAMAXAREACAR 0.311411 LAYER met1 ;
      ANTENNAMAXSIDEAREACAR 0.366366 LAYER met1 ;
    PORT
      LAYER met1 ;
        RECT 1.25 1.205 1.51 2.445 ;
    END
  END A1
  PIN B0
    DIRECTION INPUT ;
    USE SIGNAL ;
    ANTENNAMODEL OXIDE1 ;
      ANTENNAGATEAREA 0.333 LAYER met1 ;
      ANTENNAMAXAREACAR 0.316517 LAYER met1 ;
      ANTENNAMAXSIDEAREACAR 0.372372 LAYER met1 ;
    PORT
      LAYER met1 ;
        RECT 2.17 1.22 2.43 2.46 ;
    END
  END B0
  PIN B1
    DIRECTION INPUT ;
    USE SIGNAL ;
    ANTENNAMODEL OXIDE1 ;
      ANTENNAGATEAREA 0.333 LAYER met1 ;
      ANTENNAMAXAREACAR 0.268018 LAYER met1 ;
      ANTENNAMAXSIDEAREACAR 0.315315 LAYER met1 ;
    PORT
      LAYER met1 ;
        RECT 1.685 1.21 1.945 2.45 ;
    END
  END B1
  PIN C0
    DIRECTION INPUT ;
    USE SIGNAL ;
    ANTENNAMODEL OXIDE1 ;
      ANTENNAGATEAREA 0.333 LAYER met1 ;
      ANTENNAMAXAREACAR 0.313964 LAYER met1 ;
      ANTENNAMAXSIDEAREACAR 0.369369 LAYER met1 ;
    PORT
      LAYER met1 ;
        RECT 2.63 1.22 2.89 2.46 ;
    END
  END C0
  PIN VDD
    DIRECTION INPUT ;
    USE POWER ;
    SHAPE ABUTMENT ;
    NETEXPR "VDD VDD!" ;
    PORT
      LAYER met1 ;
        RECT 0 3.94 4.14 4.34 ;
    END
  END VDD
  PIN VSS
    DIRECTION INPUT ;
    USE GROUND ;
    SHAPE ABUTMENT ;
    NETEXPR "VSS VSS!" ;
    PORT
      LAYER met1 ;
        RECT 0 -0.2 4.14 0.2 ;
    END
  END VSS
  PIN Y
    DIRECTION OUTPUT ;
    USE SIGNAL ;
    ANTENNADIFFAREA 0.9971 LAYER met1 ;
    PORT
      LAYER met1 ;
        RECT 3.275 0.415 3.505 1.36 ;
        RECT 1.435 3.075 3.35 3.305 ;
        RECT 2.725 2.83 3.35 3.305 ;
        RECT 3.09 1.13 3.35 3.305 ;
        RECT 1.435 2.83 1.725 3.305 ;
    END
  END Y
  OBS
    LAYER met1 ;
      RECT 2.845 0.46 3.075 0.75 ;
      RECT 1.865 0.49 2.155 0.72 ;
      RECT 1.865 0.535 3.075 0.675 ;
      RECT 2.295 0.83 2.585 1.06 ;
      RECT 1.435 0.83 1.725 1.06 ;
      RECT 0.575 0.83 0.865 1.06 ;
      RECT 0.575 0.875 2.585 1.015 ;
  END
  PROPERTY CatenaDesignType "deviceLevel" ;
END OAI221X1_HS

MACRO OAI221X2_HS
  CLASS CORE ;
  ORIGIN 0 0 ;
  FOREIGN OAI221X2_HS 0 0 ;
  SIZE 6.9 BY 4.14 ;
  SYMMETRY X Y ;
  SITE CoreSite ;
  PIN A0
    DIRECTION INPUT ;
    USE SIGNAL ;
    ANTENNAMODEL OXIDE1 ;
      ANTENNAGATEAREA 0.666 LAYER met1 ;
      ANTENNAMAXAREACAR 0.274399 LAYER met1 ;
      ANTENNAMAXSIDEAREACAR 0.271772 LAYER met1 ;
    PORT
      LAYER met1 ;
        RECT 0.79 1.37 1.05 2.61 ;
    END
  END A0
  PIN A1
    DIRECTION INPUT ;
    USE SIGNAL ;
    ANTENNAMODEL OXIDE1 ;
      ANTENNAGATEAREA 0.666 LAYER met1 ;
      ANTENNAMAXAREACAR 0.26036 LAYER met1 ;
      ANTENNAMAXSIDEAREACAR 0.255255 LAYER met1 ;
    PORT
      LAYER met1 ;
        RECT 1.71 1.285 1.97 2.525 ;
    END
  END A1
  PIN B0
    DIRECTION INPUT ;
    USE SIGNAL ;
    ANTENNAMODEL OXIDE1 ;
      ANTENNAGATEAREA 0.666 LAYER met1 ;
      ANTENNAMAXAREACAR 0.26036 LAYER met1 ;
      ANTENNAMAXSIDEAREACAR 0.255255 LAYER met1 ;
    PORT
      LAYER met1 ;
        RECT 3.09 1.29 3.35 2.53 ;
    END
  END B0
  PIN B1
    DIRECTION INPUT ;
    USE SIGNAL ;
    ANTENNAMODEL OXIDE1 ;
      ANTENNAGATEAREA 0.666 LAYER met1 ;
      ANTENNAMAXAREACAR 0.26036 LAYER met1 ;
      ANTENNAMAXSIDEAREACAR 0.255255 LAYER met1 ;
    PORT
      LAYER met1 ;
        RECT 4.01 1.29 4.27 2.53 ;
    END
  END B1
  PIN C0
    DIRECTION INPUT ;
    USE SIGNAL ;
    ANTENNAMODEL OXIDE1 ;
      ANTENNAGATEAREA 0.666 LAYER met1 ;
      ANTENNAMAXAREACAR 0.361186 LAYER met1 ;
      ANTENNAMAXSIDEAREACAR 0.373874 LAYER met1 ;
    PORT
      LAYER met1 ;
        RECT 4.93 1.27 5.19 2.51 ;
    END
  END C0
  PIN VDD
    DIRECTION INPUT ;
    USE POWER ;
    SHAPE ABUTMENT ;
    NETEXPR "VDD VDD!" ;
    PORT
      LAYER met1 ;
        RECT 0 3.94 6.9 4.34 ;
    END
  END VDD
  PIN VSS
    DIRECTION INPUT ;
    USE GROUND ;
    SHAPE ABUTMENT ;
    NETEXPR "VSS VSS!" ;
    PORT
      LAYER met1 ;
        RECT 0 -0.2 6.9 0.2 ;
    END
  END VSS
  PIN Y
    DIRECTION OUTPUT ;
    USE SIGNAL ;
    ANTENNADIFFAREA 1.4392 LAYER met1 ;
    PORT
      LAYER met1 ;
        RECT 1.895 2.675 6.11 2.905 ;
        RECT 5.85 1.285 6.11 2.905 ;
        RECT 5.515 1.285 6.11 1.515 ;
        RECT 5.515 2.675 5.745 3.325 ;
        RECT 5.515 0.845 5.745 1.515 ;
        RECT 4.135 2.675 4.365 2.965 ;
        RECT 1.895 2.675 2.125 2.965 ;
    END
  END Y
  OBS
    LAYER met1 ;
      RECT 5.945 0.415 6.175 1.065 ;
      RECT 5.085 0.415 5.315 1.065 ;
      RECT 4.135 0.415 4.365 0.705 ;
      RECT 3.275 0.415 3.505 0.705 ;
      RECT 3.275 0.415 6.175 0.645 ;
      RECT 0.605 0.905 4.795 1.135 ;
      RECT 4.565 0.845 4.795 1.135 ;
      RECT 3.705 0.845 3.935 1.135 ;
      RECT 2.845 0.485 3.075 1.135 ;
      RECT 1.895 0.485 2.125 1.135 ;
      RECT 1.035 0.485 1.265 1.135 ;
      RECT 2.845 3.105 4.795 3.335 ;
      RECT 4.565 3.045 4.795 3.335 ;
      RECT 3.705 3.045 3.935 3.335 ;
      RECT 2.845 3.045 3.075 3.335 ;
      RECT 0.605 3.105 2.555 3.335 ;
      RECT 2.325 3.045 2.555 3.335 ;
      RECT 1.465 3.035 1.695 3.335 ;
      RECT 0.605 3.035 0.835 3.335 ;
  END
  PROPERTY CatenaDesignType "deviceLevel" ;
END OAI221X2_HS

MACRO OAI222X1_HS
  CLASS CORE ;
  ORIGIN 0 0 ;
  FOREIGN OAI222X1_HS 0 0 ;
  SIZE 4.6 BY 4.14 ;
  SYMMETRY X Y ;
  SITE CoreSite ;
  PIN A0
    DIRECTION INPUT ;
    USE SIGNAL ;
    ANTENNAMODEL OXIDE1 ;
      ANTENNAGATEAREA 0.333 LAYER met1 ;
      ANTENNAMAXAREACAR 0.357357 LAYER met1 ;
      ANTENNAMAXSIDEAREACAR 0.42042 LAYER met1 ;
    PORT
      LAYER met1 ;
        RECT 0.79 1.185 1.05 2.425 ;
    END
  END A0
  PIN A1
    DIRECTION INPUT ;
    USE SIGNAL ;
    ANTENNAMODEL OXIDE1 ;
      ANTENNAGATEAREA 0.333 LAYER met1 ;
      ANTENNAMAXAREACAR 0.357357 LAYER met1 ;
      ANTENNAMAXSIDEAREACAR 0.42042 LAYER met1 ;
    PORT
      LAYER met1 ;
        RECT 1.25 1.49 1.51 2.73 ;
    END
  END A1
  PIN B0
    DIRECTION INPUT ;
    USE SIGNAL ;
    ANTENNAMODEL OXIDE1 ;
      ANTENNAGATEAREA 0.333 LAYER met1 ;
      ANTENNAMAXAREACAR 0.467117 LAYER met1 ;
      ANTENNAMAXSIDEAREACAR 0.54955 LAYER met1 ;
    PORT
      LAYER met1 ;
        RECT 1.71 1.195 1.97 2.435 ;
    END
  END B0
  PIN B1
    DIRECTION INPUT ;
    USE SIGNAL ;
    ANTENNAMODEL OXIDE1 ;
      ANTENNAGATEAREA 0.333 LAYER met1 ;
      ANTENNAMAXAREACAR 0.487538 LAYER met1 ;
      ANTENNAMAXSIDEAREACAR 0.573574 LAYER met1 ;
    PORT
      LAYER met1 ;
        RECT 2.17 1.385 2.43 2.625 ;
    END
  END B1
  PIN C0
    DIRECTION INPUT ;
    USE SIGNAL ;
    ANTENNAMODEL OXIDE1 ;
      ANTENNAGATEAREA 0.333 LAYER met1 ;
      ANTENNAMAXAREACAR 0.344595 LAYER met1 ;
      ANTENNAMAXSIDEAREACAR 0.405405 LAYER met1 ;
    PORT
      LAYER met1 ;
        RECT 3.55 1.425 3.81 2.665 ;
    END
  END C0
  PIN C1
    DIRECTION INPUT ;
    USE SIGNAL ;
    ANTENNAMODEL OXIDE1 ;
      ANTENNAGATEAREA 0.333 LAYER met1 ;
      ANTENNAMAXAREACAR 0.472222 LAYER met1 ;
      ANTENNAMAXSIDEAREACAR 0.555556 LAYER met1 ;
    PORT
      LAYER met1 ;
        RECT 2.63 1.19 2.89 2.43 ;
    END
  END C1
  PIN VDD
    DIRECTION INPUT ;
    USE POWER ;
    SHAPE ABUTMENT ;
    NETEXPR "VDD VDD!" ;
    PORT
      LAYER met1 ;
        RECT 0 3.94 4.6 4.34 ;
    END
  END VDD
  PIN VSS
    DIRECTION INPUT ;
    USE GROUND ;
    SHAPE ABUTMENT ;
    NETEXPR "VSS VSS!" ;
    PORT
      LAYER met1 ;
        RECT 0 -0.2 4.6 0.2 ;
    END
  END VSS
  PIN Y
    DIRECTION OUTPUT ;
    USE SIGNAL ;
    ANTENNADIFFAREA 1.0085 LAYER met1 ;
    PORT
      LAYER met1 ;
        RECT 3.09 0.845 3.505 1.135 ;
        RECT 1.465 3.105 3.35 3.335 ;
        RECT 3.09 0.845 3.35 3.335 ;
        RECT 2.845 3.045 3.35 3.335 ;
        RECT 1.465 3.045 1.695 3.335 ;
    END
  END Y
  OBS
    LAYER met1 ;
      RECT 1.955 0.445 3.965 0.675 ;
      RECT 1.005 0.815 2.675 1.045 ;
  END
  PROPERTY CatenaDesignType "deviceLevel" ;
END OAI222X1_HS

MACRO OAI222X2_HS
  CLASS CORE ;
  ORIGIN 0 0 ;
  FOREIGN OAI222X2_HS 0 0 ;
  SIZE 7.82 BY 4.14 ;
  SYMMETRY X Y ;
  SITE CoreSite ;
  PIN A0
    DIRECTION INPUT ;
    USE SIGNAL ;
    ANTENNAMODEL OXIDE1 ;
      ANTENNAGATEAREA 0.666 LAYER met1 ;
      ANTENNAMAXAREACAR 0.28461 LAYER met1 ;
      ANTENNAMAXSIDEAREACAR 0.283784 LAYER met1 ;
    PORT
      LAYER met1 ;
        RECT 0.79 1.225 1.05 2.465 ;
    END
  END A0
  PIN A1
    DIRECTION INPUT ;
    USE SIGNAL ;
    ANTENNAMODEL OXIDE1 ;
      ANTENNAGATEAREA 0.666 LAYER met1 ;
      ANTENNAMAXAREACAR 0.280781 LAYER met1 ;
      ANTENNAMAXSIDEAREACAR 0.279279 LAYER met1 ;
    PORT
      LAYER met1 ;
        RECT 1.71 1.23 1.97 2.47 ;
    END
  END A1
  PIN B0
    DIRECTION INPUT ;
    USE SIGNAL ;
    ANTENNAMODEL OXIDE1 ;
      ANTENNAGATEAREA 0.666 LAYER met1 ;
      ANTENNAMAXAREACAR 0.280781 LAYER met1 ;
      ANTENNAMAXSIDEAREACAR 0.279279 LAYER met1 ;
    PORT
      LAYER met1 ;
        RECT 3.09 1.215 3.35 2.455 ;
    END
  END B0
  PIN B1
    DIRECTION INPUT ;
    USE SIGNAL ;
    ANTENNAMODEL OXIDE1 ;
      ANTENNAGATEAREA 0.666 LAYER met1 ;
      ANTENNAMAXAREACAR 0.280781 LAYER met1 ;
      ANTENNAMAXSIDEAREACAR 0.279279 LAYER met1 ;
    PORT
      LAYER met1 ;
        RECT 4.01 1.245 4.27 2.485 ;
    END
  END B1
  PIN C0
    DIRECTION INPUT ;
    USE SIGNAL ;
    ANTENNAMODEL OXIDE1 ;
      ANTENNAGATEAREA 0.666 LAYER met1 ;
      ANTENNAMAXAREACAR 0.280781 LAYER met1 ;
      ANTENNAMAXSIDEAREACAR 0.279279 LAYER met1 ;
    PORT
      LAYER met1 ;
        RECT 5.39 1.29 5.65 2.53 ;
    END
  END C0
  PIN C1
    DIRECTION INPUT ;
    USE SIGNAL ;
    ANTENNAMODEL OXIDE1 ;
      ANTENNAGATEAREA 0.666 LAYER met1 ;
      ANTENNAMAXAREACAR 0.280781 LAYER met1 ;
      ANTENNAMAXSIDEAREACAR 0.279279 LAYER met1 ;
    PORT
      LAYER met1 ;
        RECT 6.31 1.245 6.57 2.485 ;
    END
  END C1
  PIN VDD
    DIRECTION INPUT ;
    USE POWER ;
    SHAPE ABUTMENT ;
    NETEXPR "VDD VDD!" ;
    PORT
      LAYER met1 ;
        RECT 0 3.94 7.82 4.34 ;
    END
  END VDD
  PIN VSS
    DIRECTION INPUT ;
    USE GROUND ;
    SHAPE ABUTMENT ;
    NETEXPR "VSS VSS!" ;
    PORT
      LAYER met1 ;
        RECT 0 -0.2 7.82 0.2 ;
    END
  END VSS
  PIN Y
    DIRECTION OUTPUT ;
    USE SIGNAL ;
    ANTENNADIFFAREA 1.652 LAYER met1 ;
    PORT
      LAYER met1 ;
        RECT 6.375 2.735 6.605 3.025 ;
        RECT 5.515 0.875 6.605 1.015 ;
        RECT 6.375 0.725 6.605 1.015 ;
        RECT 1.895 2.735 6.605 2.875 ;
        RECT 5.85 0.875 6.11 2.875 ;
        RECT 5.515 0.725 5.745 1.015 ;
        RECT 4.135 2.735 4.365 3.025 ;
        RECT 1.895 2.735 2.125 3.025 ;
    END
  END Y
  OBS
    LAYER met1 ;
      RECT 6.805 0.415 7.035 0.705 ;
      RECT 5.945 0.415 6.175 0.705 ;
      RECT 5.085 0.415 5.315 0.705 ;
      RECT 4.135 0.415 4.365 0.705 ;
      RECT 3.275 0.415 3.505 0.705 ;
      RECT 3.275 0.415 7.035 0.555 ;
      RECT 5.085 3.195 7.035 3.335 ;
      RECT 6.805 3.045 7.035 3.335 ;
      RECT 5.945 3.045 6.175 3.335 ;
      RECT 5.085 3.045 5.315 3.335 ;
      RECT 0.605 0.875 4.795 1.015 ;
      RECT 4.565 0.725 4.795 1.015 ;
      RECT 3.705 0.725 3.935 1.015 ;
      RECT 2.845 0.725 3.075 1.015 ;
      RECT 2.325 0.725 2.555 1.015 ;
      RECT 1.465 0.725 1.695 1.015 ;
      RECT 0.605 0.725 0.835 1.015 ;
      RECT 2.845 3.195 4.795 3.335 ;
      RECT 4.565 3.045 4.795 3.335 ;
      RECT 3.705 3.045 3.935 3.335 ;
      RECT 2.845 3.045 3.075 3.335 ;
      RECT 0.605 3.195 2.555 3.335 ;
      RECT 2.325 3.045 2.555 3.335 ;
      RECT 1.465 3.045 1.695 3.335 ;
      RECT 0.605 3.045 0.835 3.335 ;
  END
  PROPERTY CatenaDesignType "deviceLevel" ;
END OAI222X2_HS

MACRO OAI22X1_HS
  CLASS CORE ;
  ORIGIN 0 0 ;
  FOREIGN OAI22X1_HS 0 0 ;
  SIZE 3.22 BY 4.14 ;
  SYMMETRY X Y ;
  SITE CoreSite ;
  PIN A0
    DIRECTION INPUT ;
    USE SIGNAL ;
    ANTENNAMODEL OXIDE1 ;
      ANTENNAGATEAREA 0.333 LAYER met1 ;
      ANTENNAMAXAREACAR 0.275676 LAYER met1 ;
      ANTENNAMAXSIDEAREACAR 0.324324 LAYER met1 ;
    PORT
      LAYER met1 ;
        RECT 0.785 0.97 1.045 2.21 ;
    END
  END A0
  PIN A1
    DIRECTION INPUT ;
    USE SIGNAL ;
    ANTENNAMODEL OXIDE1 ;
      ANTENNAGATEAREA 0.333 LAYER met1 ;
      ANTENNAMAXAREACAR 0.275676 LAYER met1 ;
      ANTENNAMAXSIDEAREACAR 0.324324 LAYER met1 ;
    PORT
      LAYER met1 ;
        RECT 1.25 1.325 1.51 2.565 ;
    END
  END A1
  PIN B0
    DIRECTION INPUT ;
    USE SIGNAL ;
    ANTENNAMODEL OXIDE1 ;
      ANTENNAGATEAREA 0.333 LAYER met1 ;
      ANTENNAMAXAREACAR 0.296096 LAYER met1 ;
      ANTENNAMAXSIDEAREACAR 0.348348 LAYER met1 ;
    PORT
      LAYER met1 ;
        RECT 2.17 1.49 2.43 2.73 ;
    END
  END B0
  PIN B1
    DIRECTION INPUT ;
    USE SIGNAL ;
    ANTENNAMODEL OXIDE1 ;
      ANTENNAGATEAREA 0.333 LAYER met1 ;
      ANTENNAMAXAREACAR 0.288438 LAYER met1 ;
      ANTENNAMAXSIDEAREACAR 0.339339 LAYER met1 ;
    PORT
      LAYER met1 ;
        RECT 1.71 1.225 1.97 2.465 ;
    END
  END B1
  PIN VDD
    DIRECTION INPUT ;
    USE POWER ;
    SHAPE ABUTMENT ;
    NETEXPR "VDD VDD!" ;
    PORT
      LAYER met1 ;
        RECT 0 3.94 3.22 4.34 ;
    END
  END VDD
  PIN VSS
    DIRECTION INPUT ;
    USE GROUND ;
    SHAPE ABUTMENT ;
    NETEXPR "VSS VSS!" ;
    PORT
      LAYER met1 ;
        RECT 0 -0.2 3.22 0.2 ;
    END
  END VSS
  PIN Y
    DIRECTION OUTPUT ;
    USE SIGNAL ;
    ANTENNADIFFAREA 0.6216 LAYER met1 ;
    PORT
      LAYER met1 ;
        RECT 1.435 3.075 2.89 3.305 ;
        RECT 2.63 0.83 2.89 3.305 ;
        RECT 1.865 0.83 2.89 1.06 ;
        RECT 1.435 3.01 1.725 3.305 ;
    END
  END Y
  OBS
    LAYER met1 ;
      RECT 2.295 0.46 2.585 0.69 ;
      RECT 1.435 0.46 1.725 0.69 ;
      RECT 0.575 0.46 0.865 0.69 ;
      RECT 0.575 0.505 2.585 0.645 ;
  END
  PROPERTY CatenaDesignType "deviceLevel" ;
END OAI22X1_HS

MACRO OAI22X2_HS
  CLASS CORE ;
  ORIGIN 0 0 ;
  FOREIGN OAI22X2_HS 0 0 ;
  SIZE 5.52 BY 4.14 ;
  SYMMETRY X Y ;
  SITE CoreSite ;
  PIN A0
    DIRECTION INPUT ;
    USE SIGNAL ;
    ANTENNAMODEL OXIDE1 ;
      ANTENNAGATEAREA 0.666 LAYER met1 ;
      ANTENNAMAXAREACAR 0.274399 LAYER met1 ;
      ANTENNAMAXSIDEAREACAR 0.271772 LAYER met1 ;
    PORT
      LAYER met1 ;
        RECT 0.79 1.445 1.05 2.685 ;
    END
  END A0
  PIN A1
    DIRECTION INPUT ;
    USE SIGNAL ;
    ANTENNAMODEL OXIDE1 ;
      ANTENNAGATEAREA 0.666 LAYER met1 ;
      ANTENNAMAXAREACAR 0.26036 LAYER met1 ;
      ANTENNAMAXSIDEAREACAR 0.255255 LAYER met1 ;
    PORT
      LAYER met1 ;
        RECT 3.09 1.14 3.35 2.38 ;
    END
  END A1
  PIN B0
    DIRECTION INPUT ;
    USE SIGNAL ;
    ANTENNAMODEL OXIDE1 ;
      ANTENNAGATEAREA 0.666 LAYER met1 ;
      ANTENNAMAXAREACAR 0.307432 LAYER met1 ;
      ANTENNAMAXSIDEAREACAR 0.283784 LAYER met1 ;
    PORT
      LAYER met1 ;
        RECT 1.71 1.485 1.97 2.725 ;
    END
  END B0
  PIN B1
    DIRECTION INPUT ;
    USE SIGNAL ;
    ANTENNAMODEL OXIDE1 ;
      ANTENNAGATEAREA 0.666 LAYER met1 ;
      ANTENNAMAXAREACAR 0.26036 LAYER met1 ;
      ANTENNAMAXSIDEAREACAR 0.255255 LAYER met1 ;
    PORT
      LAYER met1 ;
        RECT 4.01 1.225 4.27 2.465 ;
    END
  END B1
  PIN VDD
    DIRECTION INPUT ;
    USE POWER ;
    SHAPE ABUTMENT ;
    NETEXPR "VDD VDD!" ;
    PORT
      LAYER met1 ;
        RECT 0 3.94 5.52 4.34 ;
    END
  END VDD
  PIN VSS
    DIRECTION INPUT ;
    USE GROUND ;
    SHAPE ABUTMENT ;
    NETEXPR "VSS VSS!" ;
    PORT
      LAYER met1 ;
        RECT 0 -0.2 5.52 0.2 ;
    END
  END VSS
  PIN Y
    DIRECTION OUTPUT ;
    USE SIGNAL ;
    ANTENNADIFFAREA 1.6082 LAYER met1 ;
    PORT
      LAYER met1 ;
        RECT 4.565 0.77 4.795 3.35 ;
        RECT 2.845 2.61 4.795 2.84 ;
        RECT 4.47 0.77 4.795 2.84 ;
        RECT 4.135 0.77 4.795 1.06 ;
        RECT 1.895 0.77 4.795 1 ;
        RECT 3.705 2.61 3.935 2.9 ;
        RECT 2.845 2.61 3.075 2.9 ;
        RECT 1.895 0.77 2.125 1.06 ;
    END
  END Y
  OBS
    LAYER met1 ;
      RECT 1.465 0.34 1.695 0.99 ;
      RECT 0.605 0.34 0.835 0.99 ;
      RECT 4.565 0.34 4.795 0.63 ;
      RECT 3.705 0.34 3.935 0.63 ;
      RECT 2.845 0.34 3.075 0.63 ;
      RECT 2.325 0.34 2.555 0.63 ;
      RECT 0.605 0.34 4.795 0.57 ;
      RECT 4.135 3.04 4.365 3.33 ;
      RECT 1.895 3.04 4.365 3.27 ;
      RECT 1.895 2.98 2.125 3.27 ;
      RECT 1.035 3.47 3.505 3.7 ;
      RECT 3.275 3.41 3.505 3.7 ;
      RECT 1.035 3.41 1.265 3.7 ;
  END
  PROPERTY CatenaDesignType "deviceLevel" ;
END OAI22X2_HS

MACRO OR2X1_HS
  CLASS CORE ;
  ORIGIN 0 0 ;
  FOREIGN OR2X1_HS 0 0 ;
  SIZE 2.76 BY 4.14 ;
  SYMMETRY X Y ;
  SITE CoreSite ;
  PIN A
    DIRECTION INPUT ;
    USE SIGNAL ;
    ANTENNAMODEL OXIDE1 ;
      ANTENNAGATEAREA 0.18075 LAYER met1 ;
      ANTENNAMAXAREACAR 0.681881 LAYER met1 ;
      ANTENNAMAXSIDEAREACAR 0.802213 LAYER met1 ;
    PORT
      LAYER met1 ;
        RECT 1.25 1.455 1.51 2.695 ;
    END
  END A
  PIN B
    DIRECTION INPUT ;
    USE SIGNAL ;
    ANTENNAMODEL OXIDE1 ;
      ANTENNAGATEAREA 0.18075 LAYER met1 ;
      ANTENNAMAXAREACAR 0.517289 LAYER met1 ;
      ANTENNAMAXSIDEAREACAR 0.608575 LAYER met1 ;
    PORT
      LAYER met1 ;
        RECT 0.79 0.95 1.05 2.19 ;
    END
  END B
  PIN VDD
    DIRECTION INPUT ;
    USE POWER ;
    SHAPE ABUTMENT ;
    NETEXPR "VDD VDD!" ;
    PORT
      LAYER met1 ;
        RECT 0 3.94 2.76 4.34 ;
    END
  END VDD
  PIN VSS
    DIRECTION INPUT ;
    USE GROUND ;
    SHAPE ABUTMENT ;
    NETEXPR "VSS VSS!" ;
    PORT
      LAYER met1 ;
        RECT 0 -0.2 2.76 0.2 ;
    END
  END VSS
  PIN Y
    DIRECTION OUTPUT ;
    USE SIGNAL ;
    ANTENNADIFFAREA 0.5883 LAYER met1 ;
    PORT
      LAYER met1 ;
        RECT 1.955 3.21 2.43 3.5 ;
        RECT 2.17 0.505 2.43 3.5 ;
        RECT 1.955 0.505 2.43 0.795 ;
    END
  END Y
  OBS
    LAYER met1 ;
      RECT 0.575 3.27 1.66 3.5 ;
      RECT 1.43 2.84 1.66 3.5 ;
      RECT 1.65 0.965 1.88 3.07 ;
      RECT 1.225 0.965 1.88 1.195 ;
      RECT 1.225 0.475 1.455 1.195 ;
      RECT 1.005 0.475 1.455 0.705 ;
  END
  PROPERTY CatenaDesignType "deviceLevel" ;
END OR2X1_HS

MACRO OR2X2_HS
  CLASS CORE ;
  ORIGIN 0 0 ;
  FOREIGN OR2X2_HS 0 0 ;
  SIZE 3.22 BY 4.14 ;
  SYMMETRY X Y ;
  SITE CoreSite ;
  PIN A
    DIRECTION INPUT ;
    USE SIGNAL ;
    ANTENNAMODEL OXIDE1 ;
      ANTENNAGATEAREA 0.18075 LAYER met1 ;
      ANTENNAMAXAREACAR 0.521992 LAYER met1 ;
      ANTENNAMAXSIDEAREACAR 0.614108 LAYER met1 ;
    PORT
      LAYER met1 ;
        RECT 1.25 1.26 1.51 2.5 ;
    END
  END A
  PIN B
    DIRECTION INPUT ;
    USE SIGNAL ;
    ANTENNAMODEL OXIDE1 ;
      ANTENNAGATEAREA 0.18075 LAYER met1 ;
      ANTENNAMAXAREACAR 0.521992 LAYER met1 ;
      ANTENNAMAXSIDEAREACAR 0.614108 LAYER met1 ;
    PORT
      LAYER met1 ;
        RECT 0.79 0.855 1.05 2.095 ;
    END
  END B
  PIN VDD
    DIRECTION INPUT ;
    USE POWER ;
    SHAPE ABUTMENT ;
    NETEXPR "VDD VDD!" ;
    PORT
      LAYER met1 ;
        RECT 0 3.94 3.22 4.34 ;
    END
  END VDD
  PIN VSS
    DIRECTION INPUT ;
    USE GROUND ;
    SHAPE ABUTMENT ;
    NETEXPR "VSS VSS!" ;
    PORT
      LAYER met1 ;
        RECT 0 -0.2 3.22 0.2 ;
    END
  END VSS
  PIN Y
    DIRECTION OUTPUT ;
    USE SIGNAL ;
    ANTENNADIFFAREA 0.6216 LAYER met1 ;
    PORT
      LAYER met1 ;
        RECT 1.955 3.045 2.43 3.335 ;
        RECT 2.17 0.34 2.43 3.335 ;
        RECT 1.955 0.34 2.43 0.63 ;
    END
  END Y
  OBS
    LAYER met1 ;
      RECT 0.575 3.075 1.66 3.305 ;
      RECT 1.43 2.645 1.66 3.305 ;
      RECT 1.65 0.77 1.88 2.875 ;
      RECT 1.225 0.77 1.88 1 ;
      RECT 1.225 0.395 1.455 1 ;
      RECT 1.005 0.395 1.455 0.625 ;
  END
  PROPERTY CatenaDesignType "deviceLevel" ;
END OR2X2_HS

MACRO OR3X1_HS
  CLASS CORE ;
  ORIGIN 0 0 ;
  FOREIGN OR3X1_HS 0 0 ;
  SIZE 3.22 BY 4.14 ;
  SYMMETRY X Y ;
  SITE CoreSite ;
  PIN A
    DIRECTION INPUT ;
    USE SIGNAL ;
    ANTENNAMODEL OXIDE1 ;
      ANTENNAGATEAREA 0.18075 LAYER met1 ;
      ANTENNAMAXAREACAR 0.512586 LAYER met1 ;
      ANTENNAMAXSIDEAREACAR 0.603043 LAYER met1 ;
    PORT
      LAYER met1 ;
        RECT 1.71 1.265 1.97 2.505 ;
    END
  END A
  PIN B
    DIRECTION INPUT ;
    USE SIGNAL ;
    ANTENNAMODEL OXIDE1 ;
      ANTENNAGATEAREA 0.18075 LAYER met1 ;
      ANTENNAMAXAREACAR 0.550207 LAYER met1 ;
      ANTENNAMAXSIDEAREACAR 0.647303 LAYER met1 ;
    PORT
      LAYER met1 ;
        RECT 1.25 0.905 1.51 2.145 ;
    END
  END B
  PIN C
    DIRECTION INPUT ;
    USE SIGNAL ;
    ANTENNAMODEL OXIDE1 ;
      ANTENNAGATEAREA 0.18075 LAYER met1 ;
      ANTENNAMAXAREACAR 0.686584 LAYER met1 ;
      ANTENNAMAXSIDEAREACAR 0.807746 LAYER met1 ;
    PORT
      LAYER met1 ;
        RECT 0.79 1.47 1.05 2.71 ;
    END
  END C
  PIN VDD
    DIRECTION INPUT ;
    USE POWER ;
    SHAPE ABUTMENT ;
    NETEXPR "VDD VDD!" ;
    PORT
      LAYER met1 ;
        RECT 0 3.94 3.22 4.34 ;
    END
  END VDD
  PIN VSS
    DIRECTION INPUT ;
    USE GROUND ;
    SHAPE ABUTMENT ;
    NETEXPR "VSS VSS!" ;
    PORT
      LAYER met1 ;
        RECT 0 -0.2 3.22 0.2 ;
    END
  END VSS
  PIN Y
    DIRECTION OUTPUT ;
    USE SIGNAL ;
    ANTENNADIFFAREA 0.5883 LAYER met1 ;
    PORT
      LAYER met1 ;
        RECT 2.385 3.045 2.89 3.335 ;
        RECT 2.63 0.465 2.89 3.335 ;
        RECT 2.385 0.465 2.89 0.755 ;
    END
  END Y
  OBS
    LAYER met1 ;
      RECT 0.575 3.075 1.66 3.305 ;
      RECT 1.43 2.675 1.66 3.305 ;
      RECT 1.43 2.675 2.49 2.905 ;
      RECT 2.26 0.895 2.49 2.905 ;
      RECT 1.82 0.895 2.49 1.125 ;
      RECT 1.82 0.465 2.05 1.125 ;
      RECT 0.575 0.465 2.05 0.695 ;
  END
  PROPERTY CatenaDesignType "deviceLevel" ;
END OR3X1_HS

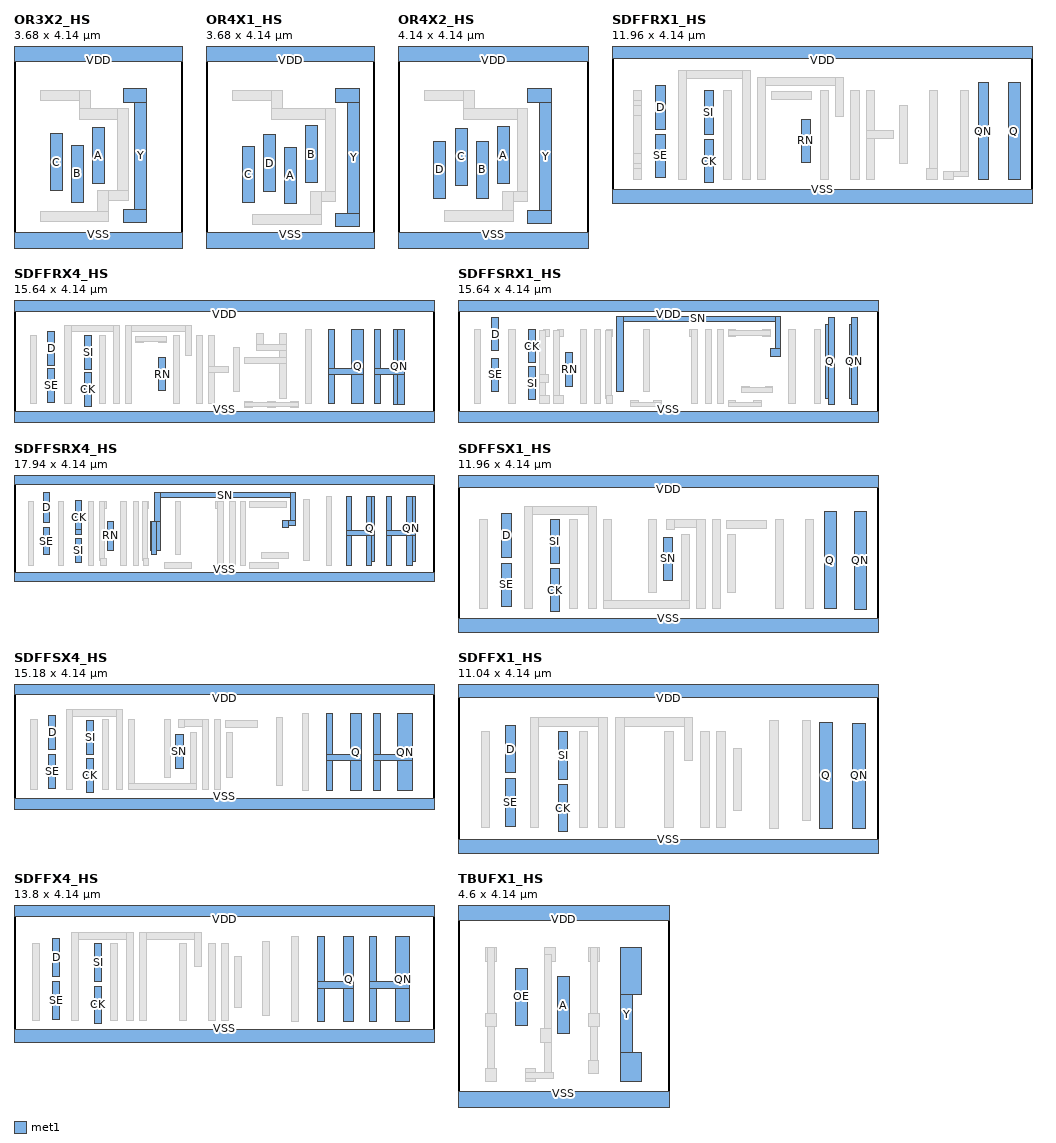
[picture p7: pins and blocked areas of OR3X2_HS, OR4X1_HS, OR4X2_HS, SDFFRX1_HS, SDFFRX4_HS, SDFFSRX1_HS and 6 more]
MACRO OR3X2_HS
  CLASS CORE ;
  ORIGIN 0 0 ;
  FOREIGN OR3X2_HS 0 0 ;
  SIZE 3.68 BY 4.14 ;
  SYMMETRY X Y ;
  SITE CoreSite ;
  PIN A
    DIRECTION INPUT ;
    USE SIGNAL ;
    ANTENNAMODEL OXIDE1 ;
      ANTENNAGATEAREA 0.18075 LAYER met1 ;
      ANTENNAMAXAREACAR 0.672476 LAYER met1 ;
      ANTENNAMAXSIDEAREACAR 0.791148 LAYER met1 ;
    PORT
      LAYER met1 ;
        RECT 1.71 1.265 1.97 2.505 ;
    END
  END A
  PIN B
    DIRECTION INPUT ;
    USE SIGNAL ;
    ANTENNAMODEL OXIDE1 ;
      ANTENNAGATEAREA 0.18075 LAYER met1 ;
      ANTENNAMAXAREACAR 0.550207 LAYER met1 ;
      ANTENNAMAXSIDEAREACAR 0.647303 LAYER met1 ;
    PORT
      LAYER met1 ;
        RECT 1.25 0.865 1.51 2.105 ;
    END
  END B
  PIN C
    DIRECTION INPUT ;
    USE SIGNAL ;
    ANTENNAMODEL OXIDE1 ;
      ANTENNAGATEAREA 0.18075 LAYER met1 ;
      ANTENNAMAXAREACAR 0.686584 LAYER met1 ;
      ANTENNAMAXSIDEAREACAR 0.807746 LAYER met1 ;
    PORT
      LAYER met1 ;
        RECT 0.79 1.115 1.05 2.355 ;
    END
  END C
  PIN VDD
    DIRECTION INPUT ;
    USE POWER ;
    SHAPE ABUTMENT ;
    NETEXPR "VDD VDD!" ;
    PORT
      LAYER met1 ;
        RECT 0 3.94 3.68 4.34 ;
    END
  END VDD
  PIN VSS
    DIRECTION INPUT ;
    USE GROUND ;
    SHAPE ABUTMENT ;
    NETEXPR "VSS VSS!" ;
    PORT
      LAYER met1 ;
        RECT 0 -0.2 3.68 0.2 ;
    END
  END VSS
  PIN Y
    DIRECTION OUTPUT ;
    USE SIGNAL ;
    ANTENNADIFFAREA 0.6216 LAYER met1 ;
    PORT
      LAYER met1 ;
        RECT 2.385 3.045 2.89 3.335 ;
        RECT 2.63 0.425 2.89 3.335 ;
        RECT 2.385 0.425 2.89 0.715 ;
    END
  END Y
  OBS
    LAYER met1 ;
      RECT 0.575 3.075 1.66 3.305 ;
      RECT 1.43 2.675 1.66 3.305 ;
      RECT 1.43 2.675 2.49 2.905 ;
      RECT 2.26 0.895 2.49 2.905 ;
      RECT 1.82 0.895 2.49 1.125 ;
      RECT 1.82 0.445 2.05 1.125 ;
      RECT 0.575 0.445 2.05 0.675 ;
  END
  PROPERTY CatenaDesignType "deviceLevel" ;
END OR3X2_HS

MACRO OR4X1_HS
  CLASS CORE ;
  ORIGIN 0 0 ;
  FOREIGN OR4X1_HS 0 0 ;
  SIZE 3.68 BY 4.14 ;
  SYMMETRY X Y ;
  SITE CoreSite ;
  PIN A
    DIRECTION INPUT ;
    USE SIGNAL ;
    ANTENNAMODEL OXIDE1 ;
      ANTENNAGATEAREA 0.18075 LAYER met1 ;
      ANTENNAMAXAREACAR 0.559613 LAYER met1 ;
      ANTENNAMAXSIDEAREACAR 0.658368 LAYER met1 ;
    PORT
      LAYER met1 ;
        RECT 1.71 0.83 1.97 2.07 ;
    END
  END A
  PIN B
    DIRECTION INPUT ;
    USE SIGNAL ;
    ANTENNAMODEL OXIDE1 ;
      ANTENNAGATEAREA 0.18075 LAYER met1 ;
      ANTENNAMAXAREACAR 2.085145 LAYER met1 ;
      ANTENNAMAXSIDEAREACAR 2.107884 LAYER met1 ;
    PORT
      LAYER met1 ;
        RECT 2.17 1.29 2.43 2.53 ;
    END
  END B
  PIN C
    DIRECTION INPUT ;
    USE SIGNAL ;
    ANTENNAMODEL OXIDE1 ;
      ANTENNAGATEAREA 0.18075 LAYER met1 ;
      ANTENNAMAXAREACAR 0.470263 LAYER met1 ;
      ANTENNAMAXSIDEAREACAR 0.55325 LAYER met1 ;
    PORT
      LAYER met1 ;
        RECT 0.79 0.85 1.05 2.09 ;
    END
  END C
  PIN D
    DIRECTION INPUT ;
    USE SIGNAL ;
    ANTENNAMODEL OXIDE1 ;
      ANTENNAGATEAREA 0.18075 LAYER met1 ;
      ANTENNAMAXAREACAR 2.028714 LAYER met1 ;
      ANTENNAMAXSIDEAREACAR 2.041494 LAYER met1 ;
    PORT
      LAYER met1 ;
        RECT 1.25 1.095 1.51 2.335 ;
    END
  END D
  PIN VDD
    DIRECTION INPUT ;
    USE POWER ;
    SHAPE ABUTMENT ;
    NETEXPR "VDD VDD!" ;
    PORT
      LAYER met1 ;
        RECT 0 3.94 3.68 4.34 ;
    END
  END VDD
  PIN VSS
    DIRECTION INPUT ;
    USE GROUND ;
    SHAPE ABUTMENT ;
    NETEXPR "VSS VSS!" ;
    PORT
      LAYER met1 ;
        RECT 0 -0.2 3.68 0.2 ;
    END
  END VSS
  PIN Y
    DIRECTION OUTPUT ;
    USE SIGNAL ;
    ANTENNADIFFAREA 0.5883 LAYER met1 ;
    PORT
      LAYER met1 ;
        RECT 2.815 3.045 3.35 3.335 ;
        RECT 3.09 0.34 3.35 3.335 ;
        RECT 2.815 0.34 3.35 0.63 ;
    END
  END Y
  OBS
    LAYER met1 ;
      RECT 0.575 3.075 1.66 3.305 ;
      RECT 1.43 2.675 1.66 3.305 ;
      RECT 1.43 2.675 2.83 2.905 ;
      RECT 2.6 0.875 2.83 2.905 ;
      RECT 2.28 0.875 2.83 1.105 ;
      RECT 2.28 0.38 2.51 1.105 ;
      RECT 1.005 0.38 2.51 0.61 ;
  END
  PROPERTY CatenaDesignType "deviceLevel" ;
END OR4X1_HS

MACRO OR4X2_HS
  CLASS CORE ;
  ORIGIN 0 0 ;
  FOREIGN OR4X2_HS 0 0 ;
  SIZE 4.14 BY 4.14 ;
  SYMMETRY X Y ;
  SITE CoreSite ;
  PIN A
    DIRECTION INPUT ;
    USE SIGNAL ;
    ANTENNAMODEL OXIDE1 ;
      ANTENNAGATEAREA 0.18075 LAYER met1 ;
      ANTENNAMAXAREACAR 0.569018 LAYER met1 ;
      ANTENNAMAXSIDEAREACAR 0.669433 LAYER met1 ;
    PORT
      LAYER met1 ;
        RECT 2.17 1.275 2.43 2.515 ;
    END
  END A
  PIN B
    DIRECTION INPUT ;
    USE SIGNAL ;
    ANTENNAMODEL OXIDE1 ;
      ANTENNAGATEAREA 0.18075 LAYER met1 ;
      ANTENNAMAXAREACAR 0.5361 LAYER met1 ;
      ANTENNAMAXSIDEAREACAR 0.630705 LAYER met1 ;
    PORT
      LAYER met1 ;
        RECT 1.71 0.95 1.97 2.19 ;
    END
  END B
  PIN C
    DIRECTION INPUT ;
    USE SIGNAL ;
    ANTENNAMODEL OXIDE1 ;
      ANTENNAGATEAREA 0.18075 LAYER met1 ;
      ANTENNAMAXAREACAR 0.507884 LAYER met1 ;
      ANTENNAMAXSIDEAREACAR 0.59751 LAYER met1 ;
    PORT
      LAYER met1 ;
        RECT 1.25 1.24 1.51 2.48 ;
    END
  END C
  PIN D
    DIRECTION INPUT ;
    USE SIGNAL ;
    ANTENNAMODEL OXIDE1 ;
      ANTENNAGATEAREA 0.18075 LAYER met1 ;
      ANTENNAMAXAREACAR 0.503181 LAYER met1 ;
      ANTENNAMAXSIDEAREACAR 0.591978 LAYER met1 ;
    PORT
      LAYER met1 ;
        RECT 0.78 0.95 1.04 2.19 ;
    END
  END D
  PIN VDD
    DIRECTION INPUT ;
    USE POWER ;
    SHAPE ABUTMENT ;
    NETEXPR "VDD VDD!" ;
    PORT
      LAYER met1 ;
        RECT 0 3.94 4.14 4.34 ;
    END
  END VDD
  PIN VSS
    DIRECTION INPUT ;
    USE GROUND ;
    SHAPE ABUTMENT ;
    NETEXPR "VSS VSS!" ;
    PORT
      LAYER met1 ;
        RECT 0 -0.2 4.14 0.2 ;
    END
  END VSS
  PIN Y
    DIRECTION OUTPUT ;
    USE SIGNAL ;
    ANTENNADIFFAREA 0.6216 LAYER met1 ;
    PORT
      LAYER met1 ;
        RECT 2.815 3.045 3.35 3.335 ;
        RECT 3.09 0.395 3.35 3.335 ;
        RECT 2.815 0.395 3.35 0.685 ;
    END
  END Y
  OBS
    LAYER met1 ;
      RECT 0.575 3.075 1.66 3.305 ;
      RECT 1.43 2.675 1.66 3.305 ;
      RECT 1.43 2.675 2.83 2.905 ;
      RECT 2.6 0.875 2.83 2.905 ;
      RECT 2.28 0.875 2.83 1.105 ;
      RECT 2.28 0.45 2.51 1.105 ;
      RECT 1.005 0.45 2.51 0.68 ;
  END
  PROPERTY CatenaDesignType "deviceLevel" ;
END OR4X2_HS

MACRO SDFFRX1_HS
  CLASS CORE ;
  ORIGIN 0 0 ;
  FOREIGN SDFFRX1_HS 0 0 ;
  SIZE 11.96 BY 4.14 ;
  SYMMETRY X Y ;
  SITE CoreSite ;
  PIN CK
    DIRECTION INPUT ;
    USE SIGNAL ;
    ANTENNAMODEL OXIDE1 ;
      ANTENNAGATEAREA 0.18075 LAYER met1 ;
      ANTENNAMAXAREACAR 0.775934 LAYER met1 ;
      ANTENNAMAXSIDEAREACAR 0.912863 LAYER met1 ;
    PORT
      LAYER met1 ;
        RECT 2.63 0.4 2.89 1.64 ;
    END
  END CK
  PIN D
    DIRECTION INPUT ;
    USE SIGNAL ;
    ANTENNAMODEL OXIDE1 ;
      ANTENNAGATEAREA 0.18075 LAYER met1 ;
      ANTENNAMAXAREACAR 0.489073 LAYER met1 ;
      ANTENNAMAXSIDEAREACAR 0.57538 LAYER met1 ;
    PORT
      LAYER met1 ;
        RECT 1.25 1.93 1.51 3.17 ;
    END
  END D
  PIN Q
    DIRECTION OUTPUT ;
    USE SIGNAL ;
    ANTENNADIFFAREA 0.5883 LAYER met1 ;
    PORT
      LAYER met1 ;
        RECT 11.285 0.49 11.63 3.26 ;
    END
  END Q
  PIN QN
    DIRECTION OUTPUT ;
    USE SIGNAL ;
    ANTENNADIFFAREA 0.5883 LAYER met1 ;
    PORT
      LAYER met1 ;
        RECT 10.425 0.485 10.71 3.255 ;
    END
  END QN
  PIN RN
    DIRECTION INPUT ;
    USE SIGNAL ;
    ANTENNAMODEL OXIDE1 ;
      ANTENNAGATEAREA 0.3615 LAYER met1 ;
      ANTENNAMAXAREACAR 1.772891 LAYER met1 ;
      ANTENNAMAXSIDEAREACAR 1.991701 LAYER met1 ;
    PORT
      LAYER met1 ;
        RECT 5.39 0.975 5.65 2.215 ;
    END
  END RN
  PIN SE
    DIRECTION INPUT ;
    USE SIGNAL ;
    ANTENNAMODEL OXIDE1 ;
      ANTENNAGATEAREA 0.3615 LAYER met1 ;
      ANTENNAMAXAREACAR 0.942877 LAYER met1 ;
      ANTENNAMAXSIDEAREACAR 1.015214 LAYER met1 ;
    PORT
      LAYER met1 ;
        RECT 1.25 0.55 1.51 1.79 ;
    END
  END SE
  PIN SI
    DIRECTION INPUT ;
    USE SIGNAL ;
    ANTENNAMODEL OXIDE1 ;
      ANTENNAGATEAREA 0.18075 LAYER met1 ;
      ANTENNAMAXAREACAR 0.771231 LAYER met1 ;
      ANTENNAMAXSIDEAREACAR 0.907331 LAYER met1 ;
    PORT
      LAYER met1 ;
        RECT 2.63 1.78 2.89 3.02 ;
    END
  END SI
  PIN VDD
    DIRECTION INPUT ;
    USE POWER ;
    SHAPE ABUTMENT ;
    NETEXPR "VDD VDD!" ;
    PORT
      LAYER met1 ;
        RECT 0 3.94 11.96 4.34 ;
    END
  END VDD
  PIN VSS
    DIRECTION INPUT ;
    USE GROUND ;
    SHAPE ABUTMENT ;
    NETEXPR "VSS VSS!" ;
    PORT
      LAYER met1 ;
        RECT 0 -0.2 11.96 0.2 ;
    END
  END VSS
  OBS
    LAYER met1 ;
      RECT 9.91 0.57 10.14 3.04 ;
      RECT 9.445 0.57 10.14 0.74 ;
      RECT 9.445 0.51 9.735 0.74 ;
      RECT 9.045 0.51 9.275 3.04 ;
      RECT 8.955 0.51 9.275 0.8 ;
      RECT 7.235 0.51 7.465 3.04 ;
      RECT 7.235 1.66 8.005 1.89 ;
      RECT 4.135 3.18 6.605 3.41 ;
      RECT 6.375 2.28 6.605 3.41 ;
      RECT 4.135 0.51 4.365 3.41 ;
      RECT 1.895 3.375 3.935 3.605 ;
      RECT 3.705 0.51 3.935 3.605 ;
      RECT 1.895 0.51 2.125 3.605 ;
      RECT 0.61 0.515 0.84 3.045 ;
      RECT 0.605 2.75 0.84 3.04 ;
      RECT 0.605 2.31 0.84 2.6 ;
      RECT 0.605 0.95 0.84 1.24 ;
      RECT 0.605 0.51 0.835 0.8 ;
      RECT 8.175 0.95 8.405 2.6 ;
      RECT 6.805 0.51 7.035 3.04 ;
      RECT 5.945 0.51 6.175 3.04 ;
      RECT 4.535 2.78 5.685 3.01 ;
      RECT 3.185 0.51 3.415 3.04 ;
  END
  PROPERTY CatenaDesignType "deviceLevel" ;
END SDFFRX1_HS

MACRO SDFFRX4_HS
  CLASS CORE ;
  ORIGIN 0 0 ;
  FOREIGN SDFFRX4_HS 0 0 ;
  SIZE 15.64 BY 4.14 ;
  SYMMETRY X Y ;
  SITE CoreSite ;
  PIN CK
    DIRECTION INPUT ;
    USE SIGNAL ;
    ANTENNAMODEL OXIDE1 ;
      ANTENNAGATEAREA 0.18075 LAYER met1 ;
      ANTENNAMAXAREACAR 0.775934 LAYER met1 ;
      ANTENNAMAXSIDEAREACAR 0.912863 LAYER met1 ;
    PORT
      LAYER met1 ;
        RECT 2.63 0.4 2.89 1.64 ;
    END
  END CK
  PIN D
    DIRECTION INPUT ;
    USE SIGNAL ;
    ANTENNAMODEL OXIDE1 ;
      ANTENNAGATEAREA 0.18075 LAYER met1 ;
      ANTENNAMAXAREACAR 0.672476 LAYER met1 ;
      ANTENNAMAXSIDEAREACAR 0.791148 LAYER met1 ;
    PORT
      LAYER met1 ;
        RECT 1.25 1.935 1.51 3.175 ;
    END
  END D
  PIN Q
    DIRECTION OUTPUT ;
    USE SIGNAL ;
    ANTENNADIFFAREA 1.2432 LAYER met1 ;
    PORT
      LAYER met1 ;
        RECT 12.575 0.485 13.01 3.255 ;
        RECT 11.715 1.575 13.01 1.805 ;
        RECT 11.715 0.485 11.945 3.255 ;
    END
  END Q
  PIN QN
    DIRECTION OUTPUT ;
    USE SIGNAL ;
    ANTENNADIFFAREA 1.2432 LAYER met1 ;
    PORT
      LAYER met1 ;
        RECT 14.295 0.48 14.525 3.255 ;
        RECT 14.13 0.48 14.525 3.25 ;
        RECT 13.435 1.575 14.525 1.805 ;
        RECT 13.435 0.485 13.665 3.255 ;
    END
  END QN
  PIN RN
    DIRECTION INPUT ;
    USE SIGNAL ;
    ANTENNAMODEL OXIDE1 ;
      ANTENNAGATEAREA 0.69675 LAYER met1 ;
      ANTENNAMAXAREACAR 1.218806 LAYER met1 ;
      ANTENNAMAXSIDEAREACAR 1.294582 LAYER met1 ;
    PORT
      LAYER met1 ;
        RECT 5.39 0.975 5.65 2.215 ;
    END
  END RN
  PIN SE
    DIRECTION INPUT ;
    USE SIGNAL ;
    ANTENNAMODEL OXIDE1 ;
      ANTENNAGATEAREA 0.3615 LAYER met1 ;
      ANTENNAMAXAREACAR 0.942877 LAYER met1 ;
      ANTENNAMAXSIDEAREACAR 1.015214 LAYER met1 ;
    PORT
      LAYER met1 ;
        RECT 1.25 0.55 1.51 1.79 ;
    END
  END SE
  PIN SI
    DIRECTION INPUT ;
    USE SIGNAL ;
    ANTENNAMODEL OXIDE1 ;
      ANTENNAGATEAREA 0.18075 LAYER met1 ;
      ANTENNAMAXAREACAR 0.771231 LAYER met1 ;
      ANTENNAMAXSIDEAREACAR 0.907331 LAYER met1 ;
    PORT
      LAYER met1 ;
        RECT 2.63 1.78 2.89 3.02 ;
    END
  END SI
  PIN VDD
    DIRECTION INPUT ;
    USE POWER ;
    SHAPE ABUTMENT ;
    NETEXPR "VDD VDD!" ;
    PORT
      LAYER met1 ;
        RECT 0 3.94 15.64 4.34 ;
    END
  END VDD
  PIN VSS
    DIRECTION INPUT ;
    USE GROUND ;
    SHAPE ABUTMENT ;
    NETEXPR "VSS VSS!" ;
    PORT
      LAYER met1 ;
        RECT 0 -0.2 15.64 0.2 ;
    END
  END VSS
  OBS
    LAYER met1 ;
      RECT 10.305 0.345 10.595 0.575 ;
      RECT 9.445 0.345 9.735 0.575 ;
      RECT 8.585 0.345 8.875 0.575 ;
      RECT 8.585 0.375 10.595 0.545 ;
      RECT 9.905 0.685 10.135 3.12 ;
      RECT 9.045 2.47 9.275 3.12 ;
      RECT 9.045 2.47 10.135 2.7 ;
      RECT 8.575 2 10.135 2.23 ;
      RECT 7.235 0.51 7.465 3.04 ;
      RECT 7.235 1.66 8.005 1.89 ;
      RECT 4.135 3.18 6.605 3.41 ;
      RECT 6.375 2.28 6.605 3.41 ;
      RECT 4.135 0.51 4.365 3.41 ;
      RECT 5.395 2.78 5.685 3.01 ;
      RECT 4.535 2.78 4.825 3.01 ;
      RECT 4.535 2.81 5.685 2.98 ;
      RECT 1.895 3.18 3.935 3.41 ;
      RECT 3.705 0.51 3.935 3.41 ;
      RECT 1.895 0.51 2.125 3.41 ;
      RECT 10.855 0.485 11.085 3.255 ;
      RECT 8.175 0.95 8.405 2.6 ;
      RECT 6.805 0.51 7.035 3.04 ;
      RECT 5.945 0.51 6.175 3.04 ;
      RECT 3.185 0.51 3.415 3.04 ;
      RECT 0.605 0.51 0.835 3.04 ;
  END
  PROPERTY CatenaDesignType "deviceLevel" ;
END SDFFRX4_HS

MACRO SDFFSRX1_HS
  CLASS CORE ;
  ORIGIN 0 0 ;
  FOREIGN SDFFSRX1_HS 0 0 ;
  SIZE 15.64 BY 4.14 ;
  SYMMETRY X Y ;
  SITE CoreSite ;
  PIN CK
    DIRECTION INPUT ;
    USE SIGNAL ;
    ANTENNAMODEL OXIDE1 ;
      ANTENNAGATEAREA 0.18075 LAYER met1 ;
      ANTENNAMAXAREACAR 0.84177 LAYER met1 ;
      ANTENNAMAXSIDEAREACAR 0.990318 LAYER met1 ;
    PORT
      LAYER met1 ;
        RECT 2.63 2.02 2.89 3.26 ;
    END
  END CK
  PIN D
    DIRECTION INPUT ;
    USE SIGNAL ;
    ANTENNAMODEL OXIDE1 ;
      ANTENNAGATEAREA 0.18075 LAYER met1 ;
      ANTENNAMAXAREACAR 0.672476 LAYER met1 ;
      ANTENNAMAXSIDEAREACAR 0.791148 LAYER met1 ;
    PORT
      LAYER met1 ;
        RECT 1.25 2.46 1.51 3.7 ;
    END
  END D
  PIN Q
    DIRECTION OUTPUT ;
    USE SIGNAL ;
    ANTENNADIFFAREA 0.5883 LAYER met1 ;
    PORT
      LAYER met1 ;
        RECT 13.69 0.68 14.035 3.45 ;
        RECT 13.795 0.45 14.025 3.71 ;
    END
  END Q
  PIN QN
    DIRECTION OUTPUT ;
    USE SIGNAL ;
    ANTENNADIFFAREA 0.5883 LAYER met1 ;
    PORT
      LAYER met1 ;
        RECT 14.655 0.45 14.885 3.71 ;
        RECT 14.59 0.675 14.885 3.45 ;
    END
  END QN
  PIN RN
    DIRECTION INPUT ;
    USE SIGNAL ;
    ANTENNAMODEL OXIDE1 ;
      ANTENNAGATEAREA 0.18075 LAYER met1 ;
      ANTENNAMAXAREACAR 0.775934 LAYER met1 ;
      ANTENNAMAXSIDEAREACAR 0.912863 LAYER met1 ;
    PORT
      LAYER met1 ;
        RECT 4.01 1.145 4.27 2.385 ;
    END
  END RN
  PIN SE
    DIRECTION INPUT ;
    USE SIGNAL ;
    ANTENNAMODEL OXIDE1 ;
      ANTENNAGATEAREA 0.3615 LAYER met1 ;
      ANTENNAMAXAREACAR 0.874689 LAYER met1 ;
      ANTENNAMAXSIDEAREACAR 0.934993 LAYER met1 ;
    PORT
      LAYER met1 ;
        RECT 1.25 0.945 1.51 2.185 ;
    END
  END SE
  PIN SI
    DIRECTION INPUT ;
    USE SIGNAL ;
    ANTENNAMODEL OXIDE1 ;
      ANTENNAGATEAREA 0.18075 LAYER met1 ;
      ANTENNAMAXAREACAR 0.578423 LAYER met1 ;
      ANTENNAMAXSIDEAREACAR 0.680498 LAYER met1 ;
    PORT
      LAYER met1 ;
        RECT 2.63 0.635 2.89 1.875 ;
    END
  END SI
  PIN SN
    DIRECTION INPUT ;
    USE SIGNAL ;
    ANTENNAMODEL OXIDE1 ;
      ANTENNAGATEAREA 0.3615 LAYER met1 ;
      ANTENNAMAXAREACAR 0.799447 LAYER met1 ;
      ANTENNAMAXSIDEAREACAR 0.940526 LAYER met1 ;
    PORT
      LAYER met1 ;
        RECT 5.885 3.55 12.005 3.75 ;
        RECT 11.805 2.245 12.005 3.75 ;
        RECT 11.62 2.245 12.005 2.535 ;
        RECT 5.885 0.94 6.145 3.75 ;
    END
  END SN
  PIN VDD
    DIRECTION INPUT ;
    USE POWER ;
    SHAPE ABUTMENT ;
    NETEXPR "VDD VDD!" ;
    PORT
      LAYER met1 ;
        RECT 0 3.94 15.64 4.34 ;
    END
  END VDD
  PIN VSS
    DIRECTION INPUT ;
    USE GROUND ;
    SHAPE ABUTMENT ;
    NETEXPR "VSS VSS!" ;
    PORT
      LAYER met1 ;
        RECT 0 -0.2 15.64 0.2 ;
    END
  END VSS
  OBS
    LAYER met1 ;
      RECT 11.435 0.9 11.725 1.13 ;
      RECT 10.575 0.9 10.865 1.13 ;
      RECT 10.575 0.93 11.725 1.1 ;
      RECT 11.345 3.015 11.635 3.245 ;
      RECT 10.055 3.015 10.345 3.245 ;
      RECT 10.055 3.045 11.635 3.215 ;
      RECT 11.005 0.375 11.295 0.605 ;
      RECT 10.055 0.375 10.345 0.605 ;
      RECT 10.055 0.375 11.295 0.545 ;
      RECT 8.615 2.985 8.935 3.275 ;
      RECT 8.705 0.51 8.935 3.275 ;
      RECT 7.295 0.375 7.585 0.605 ;
      RECT 6.435 0.375 6.725 0.605 ;
      RECT 6.435 0.375 7.585 0.545 ;
      RECT 5.515 2.985 5.745 3.275 ;
      RECT 5.48 0.705 5.71 3.235 ;
      RECT 5.515 0.51 5.745 0.8 ;
      RECT 3.705 2.985 3.935 3.275 ;
      RECT 3.555 0.51 3.785 3.235 ;
      RECT 3.555 0.51 3.935 0.8 ;
      RECT 3.185 2.985 3.415 3.275 ;
      RECT 3.03 0.51 3.26 3.235 ;
      RECT 3.03 1.29 3.375 1.58 ;
      RECT 3.03 0.51 3.415 0.8 ;
      RECT 13.275 0.51 13.505 3.275 ;
      RECT 12.325 0.51 12.555 3.275 ;
      RECT 9.655 0.51 9.885 3.275 ;
      RECT 9.225 0.51 9.455 3.275 ;
      RECT 6.895 0.95 7.125 3.275 ;
      RECT 5.085 0.51 5.315 3.275 ;
      RECT 4.565 0.51 4.795 3.275 ;
      RECT 1.895 0.51 2.125 3.275 ;
      RECT 0.605 0.51 0.835 3.275 ;
  END
  PROPERTY CatenaDesignType "deviceLevel" ;
  PROPERTY oaTaper "virtuosoDefaultSetup" ;
END SDFFSRX1_HS

MACRO SDFFSRX4_HS
  CLASS CORE ;
  ORIGIN 0 0 ;
  FOREIGN SDFFSRX4_HS 0 0 ;
  SIZE 17.94 BY 4.14 ;
  SYMMETRY X Y ;
  SITE CoreSite ;
  PIN CK
    DIRECTION INPUT ;
    USE SIGNAL ;
    ANTENNAMODEL OXIDE1 ;
      ANTENNAGATEAREA 0.18075 LAYER met1 ;
      ANTENNAMAXAREACAR 0.84177 LAYER met1 ;
      ANTENNAMAXSIDEAREACAR 0.990318 LAYER met1 ;
    PORT
      LAYER met1 ;
        RECT 2.63 2.02 2.89 3.26 ;
        RECT 2.645 1.83 2.875 3.26 ;
    END
  END CK
  PIN D
    DIRECTION INPUT ;
    USE SIGNAL ;
    ANTENNAMODEL OXIDE1 ;
      ANTENNAGATEAREA 0.18075 LAYER met1 ;
      ANTENNAMAXAREACAR 0.503181 LAYER met1 ;
      ANTENNAMAXSIDEAREACAR 0.591978 LAYER met1 ;
    PORT
      LAYER met1 ;
        RECT 1.25 2.36 1.51 3.6 ;
        RECT 1.265 2.31 1.495 3.6 ;
    END
  END D
  PIN Q
    DIRECTION OUTPUT ;
    USE SIGNAL ;
    ANTENNADIFFAREA 1.2432 LAYER met1 ;
    PORT
      LAYER met1 ;
        RECT 15.05 0.68 15.395 3.45 ;
        RECT 15.055 0.485 15.285 3.45 ;
        RECT 14.195 1.77 15.395 2 ;
        RECT 14.195 0.485 14.425 3.45 ;
    END
  END Q
  PIN QN
    DIRECTION OUTPUT ;
    USE SIGNAL ;
    ANTENNADIFFAREA 1.2432 LAYER met1 ;
    PORT
      LAYER met1 ;
        RECT 16.775 0.68 17.15 3.455 ;
        RECT 16.775 0.485 17.005 3.455 ;
        RECT 15.915 1.77 17.15 2 ;
        RECT 15.915 0.485 16.145 3.45 ;
    END
  END QN
  PIN RN
    DIRECTION INPUT ;
    USE SIGNAL ;
    ANTENNAMODEL OXIDE1 ;
      ANTENNAGATEAREA 0.18075 LAYER met1 ;
      ANTENNAMAXAREACAR 0.775934 LAYER met1 ;
      ANTENNAMAXSIDEAREACAR 0.912863 LAYER met1 ;
    PORT
      LAYER met1 ;
        RECT 4.01 1.145 4.27 2.385 ;
    END
  END RN
  PIN SE
    DIRECTION INPUT ;
    USE SIGNAL ;
    ANTENNAMODEL OXIDE1 ;
      ANTENNAGATEAREA 0.3615 LAYER met1 ;
      ANTENNAMAXAREACAR 0.884094 LAYER met1 ;
      ANTENNAMAXSIDEAREACAR 0.946058 LAYER met1 ;
    PORT
      LAYER met1 ;
        RECT 1.25 0.945 1.51 2.1 ;
    END
  END SE
  PIN SI
    DIRECTION INPUT ;
    USE SIGNAL ;
    ANTENNAMODEL OXIDE1 ;
      ANTENNAGATEAREA 0.18075 LAYER met1 ;
      ANTENNAMAXAREACAR 0.578423 LAYER met1 ;
      ANTENNAMAXSIDEAREACAR 0.680498 LAYER met1 ;
    PORT
      LAYER met1 ;
        RECT 2.63 0.635 2.89 1.64 ;
    END
  END SI
  PIN SN
    DIRECTION INPUT ;
    USE SIGNAL ;
    ANTENNAMODEL OXIDE1 ;
      ANTENNAGATEAREA 0.3615 LAYER met1 ;
      ANTENNAMAXAREACAR 0.818257 LAYER met1 ;
      ANTENNAMAXSIDEAREACAR 0.962656 LAYER met1 ;
    PORT
      LAYER met1 ;
        RECT 6.02 3.39 12.005 3.59 ;
        RECT 11.805 2.21 12.005 3.59 ;
        RECT 11.485 2.21 12.005 2.41 ;
        RECT 11.485 2.12 11.715 2.41 ;
        RECT 6.02 1.145 6.25 3.59 ;
        RECT 5.865 0.95 6.095 2.385 ;
        RECT 5.85 1.145 6.25 2.385 ;
    END
  END SN
  PIN VDD
    DIRECTION INPUT ;
    USE POWER ;
    SHAPE ABUTMENT ;
    NETEXPR "VDD VDD!" ;
    PORT
      LAYER met1 ;
        RECT 0 3.94 17.94 4.34 ;
    END
  END VDD
  PIN VSS
    DIRECTION INPUT ;
    USE GROUND ;
    SHAPE ABUTMENT ;
    NETEXPR "VSS VSS!" ;
    PORT
      LAYER met1 ;
        RECT 0 -0.2 17.94 0.2 ;
    END
  END VSS
  OBS
    LAYER met1 ;
      RECT 8.615 2.945 8.935 3.235 ;
      RECT 8.705 0.51 8.935 3.235 ;
      RECT 5.48 2.945 5.745 3.235 ;
      RECT 5.48 0.705 5.71 3.235 ;
      RECT 5.515 0.51 5.745 0.8 ;
      RECT 3.64 2.945 3.935 3.235 ;
      RECT 3.64 0.705 3.87 3.235 ;
      RECT 3.705 0.51 3.935 0.8 ;
      RECT 13.335 0.485 13.565 3.45 ;
      RECT 12.385 0.685 12.615 3.315 ;
      RECT 10.575 0.8 11.725 1.03 ;
      RECT 10.055 2.975 11.635 3.205 ;
      RECT 10.055 0.375 11.295 0.605 ;
      RECT 9.655 0.51 9.885 3.235 ;
      RECT 9.225 0.51 9.455 3.235 ;
      RECT 6.435 0.375 7.585 0.605 ;
      RECT 6.895 0.95 7.125 3.235 ;
      RECT 5.085 0.51 5.315 3.235 ;
      RECT 4.565 0.51 4.795 3.235 ;
      RECT 3.185 0.51 3.415 3.235 ;
      RECT 1.895 0.51 2.125 3.235 ;
      RECT 0.605 0.51 0.835 3.235 ;
  END
  PROPERTY CatenaDesignType "deviceLevel" ;
END SDFFSRX4_HS

MACRO SDFFSX1_HS
  CLASS CORE ;
  ORIGIN 0 0 ;
  FOREIGN SDFFSX1_HS 0 0 ;
  SIZE 11.96 BY 4.14 ;
  SYMMETRY X Y ;
  SITE CoreSite ;
  PIN CK
    DIRECTION INPUT ;
    USE SIGNAL ;
    ANTENNAMODEL OXIDE1 ;
      ANTENNAGATEAREA 0.18075 LAYER met1 ;
      ANTENNAMAXAREACAR 0.775934 LAYER met1 ;
      ANTENNAMAXSIDEAREACAR 0.912863 LAYER met1 ;
    PORT
      LAYER met1 ;
        RECT 2.63 0.4 2.89 1.64 ;
    END
  END CK
  PIN D
    DIRECTION INPUT ;
    USE SIGNAL ;
    ANTENNAMODEL OXIDE1 ;
      ANTENNAGATEAREA 0.18075 LAYER met1 ;
      ANTENNAMAXAREACAR 0.672476 LAYER met1 ;
      ANTENNAMAXSIDEAREACAR 0.791148 LAYER met1 ;
    PORT
      LAYER met1 ;
        RECT 1.25 1.955 1.51 3.195 ;
    END
  END D
  PIN Q
    DIRECTION OUTPUT ;
    USE SIGNAL ;
    ANTENNADIFFAREA 0.5883 LAYER met1 ;
    PORT
      LAYER met1 ;
        RECT 10.425 0.485 10.77 3.255 ;
    END
  END Q
  PIN QN
    DIRECTION OUTPUT ;
    USE SIGNAL ;
    ANTENNADIFFAREA 0.5883 LAYER met1 ;
    PORT
      LAYER met1 ;
        RECT 11.285 0.48 11.63 3.255 ;
    END
  END QN
  PIN SE
    DIRECTION INPUT ;
    USE SIGNAL ;
    ANTENNAMODEL OXIDE1 ;
      ANTENNAGATEAREA 0.3615 LAYER met1 ;
      ANTENNAMAXAREACAR 0.942877 LAYER met1 ;
      ANTENNAMAXSIDEAREACAR 1.015214 LAYER met1 ;
    PORT
      LAYER met1 ;
        RECT 1.25 0.55 1.51 1.79 ;
    END
  END SE
  PIN SI
    DIRECTION INPUT ;
    USE SIGNAL ;
    ANTENNAMODEL OXIDE1 ;
      ANTENNAGATEAREA 0.18075 LAYER met1 ;
      ANTENNAMAXAREACAR 0.771231 LAYER met1 ;
      ANTENNAMAXSIDEAREACAR 0.907331 LAYER met1 ;
    PORT
      LAYER met1 ;
        RECT 2.63 1.785 2.89 3.025 ;
    END
  END SI
  PIN SN
    DIRECTION INPUT ;
    USE SIGNAL ;
    ANTENNAMODEL OXIDE1 ;
      ANTENNAGATEAREA 0.3615 LAYER met1 ;
      ANTENNAMAXAREACAR 1.493084 LAYER met1 ;
      ANTENNAMAXSIDEAREACAR 1.662517 LAYER met1 ;
    PORT
      LAYER met1 ;
        RECT 5.85 1.29 6.11 2.53 ;
    END
  END SN
  PIN VDD
    DIRECTION INPUT ;
    USE POWER ;
    SHAPE ABUTMENT ;
    NETEXPR "VDD VDD!" ;
    PORT
      LAYER met1 ;
        RECT 0 3.94 11.96 4.34 ;
    END
  END VDD
  PIN VSS
    DIRECTION INPUT ;
    USE GROUND ;
    SHAPE ABUTMENT ;
    NETEXPR "VSS VSS!" ;
    PORT
      LAYER met1 ;
        RECT 0 -0.2 11.96 0.2 ;
    END
  END VSS
  OBS
    LAYER met1 ;
      RECT 5.945 2.81 7.035 3.04 ;
      RECT 6.805 0.51 7.035 3.04 ;
      RECT 5.945 2.75 6.175 3.04 ;
      RECT 4.135 0.51 4.365 3.04 ;
      RECT 6.375 0.51 6.605 2.6 ;
      RECT 4.135 0.51 6.605 0.74 ;
      RECT 1.895 3.18 3.935 3.41 ;
      RECT 3.705 0.51 3.935 3.41 ;
      RECT 1.895 0.51 2.125 3.41 ;
      RECT 9.905 0.51 10.135 3.04 ;
      RECT 9.045 0.51 9.275 3.04 ;
      RECT 7.635 2.78 8.785 3.01 ;
      RECT 7.665 0.95 7.895 2.6 ;
      RECT 7.235 0.51 7.465 3.04 ;
      RECT 5.425 0.95 5.655 3.04 ;
      RECT 3.185 0.51 3.415 3.04 ;
      RECT 0.605 0.51 0.835 3.04 ;
  END
  PROPERTY CatenaDesignType "deviceLevel" ;
END SDFFSX1_HS

MACRO SDFFSX4_HS
  CLASS CORE ;
  ORIGIN 0 0 ;
  FOREIGN SDFFSX4_HS 0 0 ;
  SIZE 15.18 BY 4.14 ;
  SYMMETRY X Y ;
  SITE CoreSite ;
  PIN CK
    DIRECTION INPUT ;
    USE SIGNAL ;
    ANTENNAMODEL OXIDE1 ;
      ANTENNAGATEAREA 0.18075 LAYER met1 ;
      ANTENNAMAXAREACAR 0.775934 LAYER met1 ;
      ANTENNAMAXSIDEAREACAR 0.912863 LAYER met1 ;
    PORT
      LAYER met1 ;
        RECT 2.63 0.4 2.89 1.64 ;
    END
  END CK
  PIN D
    DIRECTION INPUT ;
    USE SIGNAL ;
    ANTENNAMODEL OXIDE1 ;
      ANTENNAGATEAREA 0.18075 LAYER met1 ;
      ANTENNAMAXAREACAR 0.672476 LAYER met1 ;
      ANTENNAMAXSIDEAREACAR 0.791148 LAYER met1 ;
    PORT
      LAYER met1 ;
        RECT 1.25 1.955 1.51 3.195 ;
    END
  END D
  PIN Q
    DIRECTION OUTPUT ;
    USE SIGNAL ;
    ANTENNADIFFAREA 1.2432 LAYER met1 ;
    PORT
      LAYER met1 ;
        RECT 12.145 0.485 12.55 3.255 ;
        RECT 11.285 1.575 12.55 1.805 ;
        RECT 11.285 0.485 11.515 3.255 ;
    END
  END Q
  PIN QN
    DIRECTION OUTPUT ;
    USE SIGNAL ;
    ANTENNADIFFAREA 1.2432 LAYER met1 ;
    PORT
      LAYER met1 ;
        RECT 13.865 0.48 14.39 3.255 ;
        RECT 13.005 1.575 14.39 1.805 ;
        RECT 13.005 0.485 13.235 3.255 ;
    END
  END QN
  PIN SE
    DIRECTION INPUT ;
    USE SIGNAL ;
    ANTENNAMODEL OXIDE1 ;
      ANTENNAGATEAREA 0.3615 LAYER met1 ;
      ANTENNAMAXAREACAR 0.942877 LAYER met1 ;
      ANTENNAMAXSIDEAREACAR 1.015214 LAYER met1 ;
    PORT
      LAYER met1 ;
        RECT 1.25 0.55 1.51 1.79 ;
    END
  END SE
  PIN SI
    DIRECTION INPUT ;
    USE SIGNAL ;
    ANTENNAMODEL OXIDE1 ;
      ANTENNAGATEAREA 0.18075 LAYER met1 ;
      ANTENNAMAXAREACAR 0.771231 LAYER met1 ;
      ANTENNAMAXSIDEAREACAR 0.907331 LAYER met1 ;
    PORT
      LAYER met1 ;
        RECT 2.63 1.785 2.89 3.025 ;
    END
  END SI
  PIN SN
    DIRECTION INPUT ;
    USE SIGNAL ;
    ANTENNAMODEL OXIDE1 ;
      ANTENNAGATEAREA 0.3615 LAYER met1 ;
      ANTENNAMAXAREACAR 1.493084 LAYER met1 ;
      ANTENNAMAXSIDEAREACAR 1.662517 LAYER met1 ;
    PORT
      LAYER met1 ;
        RECT 5.85 1.29 6.11 2.53 ;
    END
  END SN
  PIN VDD
    DIRECTION INPUT ;
    USE POWER ;
    SHAPE ABUTMENT ;
    NETEXPR "VDD VDD!" ;
    PORT
      LAYER met1 ;
        RECT 0 3.94 15.18 4.34 ;
    END
  END VDD
  PIN VSS
    DIRECTION INPUT ;
    USE GROUND ;
    SHAPE ABUTMENT ;
    NETEXPR "VSS VSS!" ;
    PORT
      LAYER met1 ;
        RECT 0 -0.2 15.18 0.2 ;
    END
  END VSS
  OBS
    LAYER met1 ;
      RECT 5.945 2.81 7.035 3.04 ;
      RECT 6.805 0.51 7.035 3.04 ;
      RECT 5.945 2.75 6.175 3.04 ;
      RECT 4.135 0.51 4.365 3.04 ;
      RECT 6.375 0.51 6.605 2.6 ;
      RECT 4.135 0.51 6.605 0.74 ;
      RECT 1.895 3.18 3.935 3.41 ;
      RECT 3.705 0.51 3.935 3.41 ;
      RECT 1.895 0.51 2.125 3.41 ;
      RECT 10.425 0.485 10.655 3.255 ;
      RECT 9.475 0.685 9.705 3.12 ;
      RECT 7.635 2.78 8.785 3.01 ;
      RECT 7.665 0.95 7.895 2.6 ;
      RECT 7.235 0.51 7.465 3.04 ;
      RECT 5.425 0.95 5.655 3.04 ;
      RECT 3.185 0.51 3.415 3.04 ;
      RECT 0.605 0.51 0.835 3.04 ;
  END
  PROPERTY CatenaDesignType "deviceLevel" ;
END SDFFSX4_HS

MACRO SDFFX1_HS
  CLASS CORE ;
  ORIGIN 0 0 ;
  FOREIGN SDFFX1_HS 0 0 ;
  SIZE 11.04 BY 4.14 ;
  SYMMETRY X Y ;
  SITE CoreSite ;
  PIN CK
    DIRECTION INPUT ;
    USE SIGNAL ;
    ANTENNAMODEL OXIDE1 ;
      ANTENNAGATEAREA 0.18075 LAYER met1 ;
      ANTENNAMAXAREACAR 0.775934 LAYER met1 ;
      ANTENNAMAXSIDEAREACAR 0.912863 LAYER met1 ;
    PORT
      LAYER met1 ;
        RECT 2.63 0.4 2.89 1.64 ;
    END
  END CK
  PIN D
    DIRECTION INPUT ;
    USE SIGNAL ;
    ANTENNAMODEL OXIDE1 ;
      ANTENNAGATEAREA 0.18075 LAYER met1 ;
      ANTENNAMAXAREACAR 0.672476 LAYER met1 ;
      ANTENNAMAXSIDEAREACAR 0.791148 LAYER met1 ;
    PORT
      LAYER met1 ;
        RECT 1.25 1.955 1.51 3.195 ;
    END
  END D
  PIN Q
    DIRECTION OUTPUT ;
    USE SIGNAL ;
    ANTENNADIFFAREA 0.5883 LAYER met1 ;
    PORT
      LAYER met1 ;
        RECT 9.505 0.485 9.85 3.26 ;
    END
  END Q
  PIN QN
    DIRECTION OUTPUT ;
    USE SIGNAL ;
    ANTENNADIFFAREA 0.5883 LAYER met1 ;
    PORT
      LAYER met1 ;
        RECT 10.365 0.48 10.71 3.255 ;
    END
  END QN
  PIN SE
    DIRECTION INPUT ;
    USE SIGNAL ;
    ANTENNAMODEL OXIDE1 ;
      ANTENNAGATEAREA 0.3615 LAYER met1 ;
      ANTENNAMAXAREACAR 0.924066 LAYER met1 ;
      ANTENNAMAXSIDEAREACAR 0.993084 LAYER met1 ;
    PORT
      LAYER met1 ;
        RECT 1.25 0.55 1.51 1.79 ;
    END
  END SE
  PIN SI
    DIRECTION INPUT ;
    USE SIGNAL ;
    ANTENNAMODEL OXIDE1 ;
      ANTENNAGATEAREA 0.18075 LAYER met1 ;
      ANTENNAMAXAREACAR 0.771231 LAYER met1 ;
      ANTENNAMAXSIDEAREACAR 0.907331 LAYER met1 ;
    PORT
      LAYER met1 ;
        RECT 2.63 1.785 2.89 3.025 ;
    END
  END SI
  PIN VDD
    DIRECTION INPUT ;
    USE POWER ;
    SHAPE ABUTMENT ;
    NETEXPR "VDD VDD!" ;
    PORT
      LAYER met1 ;
        RECT 0 3.94 11.04 4.34 ;
    END
  END VDD
  PIN VSS
    DIRECTION INPUT ;
    USE GROUND ;
    SHAPE ABUTMENT ;
    NETEXPR "VSS VSS!" ;
    PORT
      LAYER met1 ;
        RECT 0 -0.2 11.04 0.2 ;
    END
  END VSS
  OBS
    LAYER met1 ;
      RECT 4.135 3.18 6.175 3.41 ;
      RECT 5.945 2.28 6.175 3.41 ;
      RECT 4.135 0.51 4.365 3.41 ;
      RECT 1.895 3.18 3.935 3.41 ;
      RECT 3.705 0.51 3.935 3.41 ;
      RECT 1.895 0.51 2.125 3.41 ;
      RECT 9.045 0.685 9.275 3.335 ;
      RECT 8.185 0.485 8.415 3.335 ;
      RECT 7.235 0.95 7.465 2.6 ;
      RECT 6.805 0.51 7.035 3.04 ;
      RECT 6.375 0.51 6.605 3.04 ;
      RECT 5.425 0.51 5.655 3.04 ;
      RECT 3.185 0.51 3.415 3.04 ;
      RECT 0.605 0.51 0.835 3.04 ;
  END
  PROPERTY CatenaDesignType "deviceLevel" ;
END SDFFX1_HS

MACRO SDFFX4_HS
  CLASS CORE ;
  ORIGIN 0 0 ;
  FOREIGN SDFFX4_HS 0 0 ;
  SIZE 13.8 BY 4.14 ;
  SYMMETRY X Y ;
  SITE CoreSite ;
  PIN CK
    DIRECTION INPUT ;
    USE SIGNAL ;
    ANTENNAMODEL OXIDE1 ;
      ANTENNAGATEAREA 0.18075 LAYER met1 ;
      ANTENNAMAXAREACAR 0.775934 LAYER met1 ;
      ANTENNAMAXSIDEAREACAR 0.912863 LAYER met1 ;
    PORT
      LAYER met1 ;
        RECT 2.63 0.4 2.89 1.64 ;
    END
  END CK
  PIN D
    DIRECTION INPUT ;
    USE SIGNAL ;
    ANTENNAMODEL OXIDE1 ;
      ANTENNAGATEAREA 0.18075 LAYER met1 ;
      ANTENNAMAXAREACAR 0.672476 LAYER met1 ;
      ANTENNAMAXSIDEAREACAR 0.791148 LAYER met1 ;
    PORT
      LAYER met1 ;
        RECT 1.25 1.955 1.51 3.195 ;
    END
  END D
  PIN Q
    DIRECTION OUTPUT ;
    USE SIGNAL ;
    ANTENNADIFFAREA 1.2432 LAYER met1 ;
    PORT
      LAYER met1 ;
        RECT 10.825 0.48 11.17 3.255 ;
        RECT 9.965 1.575 11.17 1.805 ;
        RECT 9.965 0.485 10.195 3.255 ;
    END
  END Q
  PIN QN
    DIRECTION OUTPUT ;
    USE SIGNAL ;
    ANTENNADIFFAREA 1.2432 LAYER met1 ;
    PORT
      LAYER met1 ;
        RECT 12.545 0.48 13.01 3.255 ;
        RECT 11.685 1.575 13.01 1.805 ;
        RECT 11.685 0.485 11.915 3.255 ;
    END
  END QN
  PIN SE
    DIRECTION INPUT ;
    USE SIGNAL ;
    ANTENNAMODEL OXIDE1 ;
      ANTENNAGATEAREA 0.3615 LAYER met1 ;
      ANTENNAMAXAREACAR 0.942877 LAYER met1 ;
      ANTENNAMAXSIDEAREACAR 1.015214 LAYER met1 ;
    PORT
      LAYER met1 ;
        RECT 1.25 0.55 1.51 1.79 ;
    END
  END SE
  PIN SI
    DIRECTION INPUT ;
    USE SIGNAL ;
    ANTENNAMODEL OXIDE1 ;
      ANTENNAGATEAREA 0.18075 LAYER met1 ;
      ANTENNAMAXAREACAR 0.771231 LAYER met1 ;
      ANTENNAMAXSIDEAREACAR 0.907331 LAYER met1 ;
    PORT
      LAYER met1 ;
        RECT 2.63 1.785 2.89 3.025 ;
    END
  END SI
  PIN VDD
    DIRECTION INPUT ;
    USE POWER ;
    SHAPE ABUTMENT ;
    NETEXPR "VDD VDD!" ;
    PORT
      LAYER met1 ;
        RECT 0 3.94 13.8 4.34 ;
    END
  END VDD
  PIN VSS
    DIRECTION INPUT ;
    USE GROUND ;
    SHAPE ABUTMENT ;
    NETEXPR "VSS VSS!" ;
    PORT
      LAYER met1 ;
        RECT 0 -0.2 13.8 0.2 ;
    END
  END VSS
  OBS
    LAYER met1 ;
      RECT 4.135 3.18 6.175 3.41 ;
      RECT 5.945 2.28 6.175 3.41 ;
      RECT 4.135 0.51 4.365 3.41 ;
      RECT 1.895 3.18 3.935 3.41 ;
      RECT 3.705 0.51 3.935 3.41 ;
      RECT 1.895 0.51 2.125 3.41 ;
      RECT 9.105 0.485 9.335 3.255 ;
      RECT 8.155 0.685 8.385 3.12 ;
      RECT 7.235 0.95 7.465 2.6 ;
      RECT 6.805 0.51 7.035 3.04 ;
      RECT 6.375 0.51 6.605 3.04 ;
      RECT 5.425 0.51 5.655 3.04 ;
      RECT 3.185 0.51 3.415 3.04 ;
      RECT 0.605 0.51 0.835 3.04 ;
  END
  PROPERTY CatenaDesignType "deviceLevel" ;
END SDFFX4_HS

MACRO TBUFX1_HS
  CLASS CORE ;
  ORIGIN 0 0 ;
  FOREIGN TBUFX1_HS 0 0 ;
  SIZE 4.6 BY 4.14 ;
  SYMMETRY X Y ;
  SITE CoreSite ;
  PIN A
    DIRECTION INPUT ;
    USE SIGNAL ;
    ANTENNAMODEL OXIDE1 ;
      ANTENNAGATEAREA 0.3615 LAYER met1 ;
      ANTENNAMAXAREACAR 0.754772 LAYER met1 ;
      ANTENNAMAXSIDEAREACAR 0.793914 LAYER met1 ;
    PORT
      LAYER met1 ;
        RECT 2.17 1.47 2.43 2.71 ;
    END
  END A
  PIN OE
    DIRECTION INPUT ;
    USE SIGNAL ;
    ANTENNAMODEL OXIDE1 ;
      ANTENNAGATEAREA 0.3615 LAYER met1 ;
      ANTENNAMAXAREACAR 1.194467 LAYER met1 ;
      ANTENNAMAXSIDEAREACAR 1.311203 LAYER met1 ;
    PORT
      LAYER met1 ;
        RECT 1.25 1.655 1.51 2.895 ;
    END
  END OE
  PIN VDD
    DIRECTION INPUT ;
    USE POWER ;
    SHAPE ABUTMENT ;
    NETEXPR "VDD VDD!" ;
    PORT
      LAYER met1 ;
        RECT 0 3.94 4.6 4.34 ;
    END
  END VDD
  PIN VSS
    DIRECTION INPUT ;
    USE GROUND ;
    SHAPE ABUTMENT ;
    NETEXPR "VSS VSS!" ;
    PORT
      LAYER met1 ;
        RECT 0 -0.2 4.6 0.2 ;
    END
  END VSS
  PIN Y
    DIRECTION OUTPUT ;
    USE SIGNAL ;
    ANTENNADIFFAREA 0.5883 LAYER met1 ;
    PORT
      LAYER met1 ;
        RECT 3.55 2.325 3.995 3.335 ;
        RECT 3.55 0.415 3.995 1.065 ;
        RECT 3.55 0.415 3.81 3.335 ;
    END
  END Y
  OBS
    LAYER met1 ;
      RECT 2.845 3.045 3.075 3.335 ;
      RECT 2.89 0.59 3.03 3.335 ;
      RECT 2.845 1.625 3.075 1.915 ;
      RECT 2.835 0.59 3.065 0.88 ;
      RECT 1.895 3.045 2.125 3.335 ;
      RECT 1.89 0.49 2.03 3.19 ;
      RECT 1.8 1.285 2.03 1.575 ;
      RECT 1.465 0.415 1.695 0.705 ;
      RECT 1.465 0.49 2.08 0.63 ;
      RECT 0.605 3.045 0.835 3.335 ;
      RECT 0.635 0.415 0.805 3.335 ;
      RECT 0.605 1.625 0.835 1.915 ;
      RECT 0.605 0.415 0.835 0.705 ;
  END
  PROPERTY CatenaDesignType "deviceLevel" ;
END TBUFX1_HS

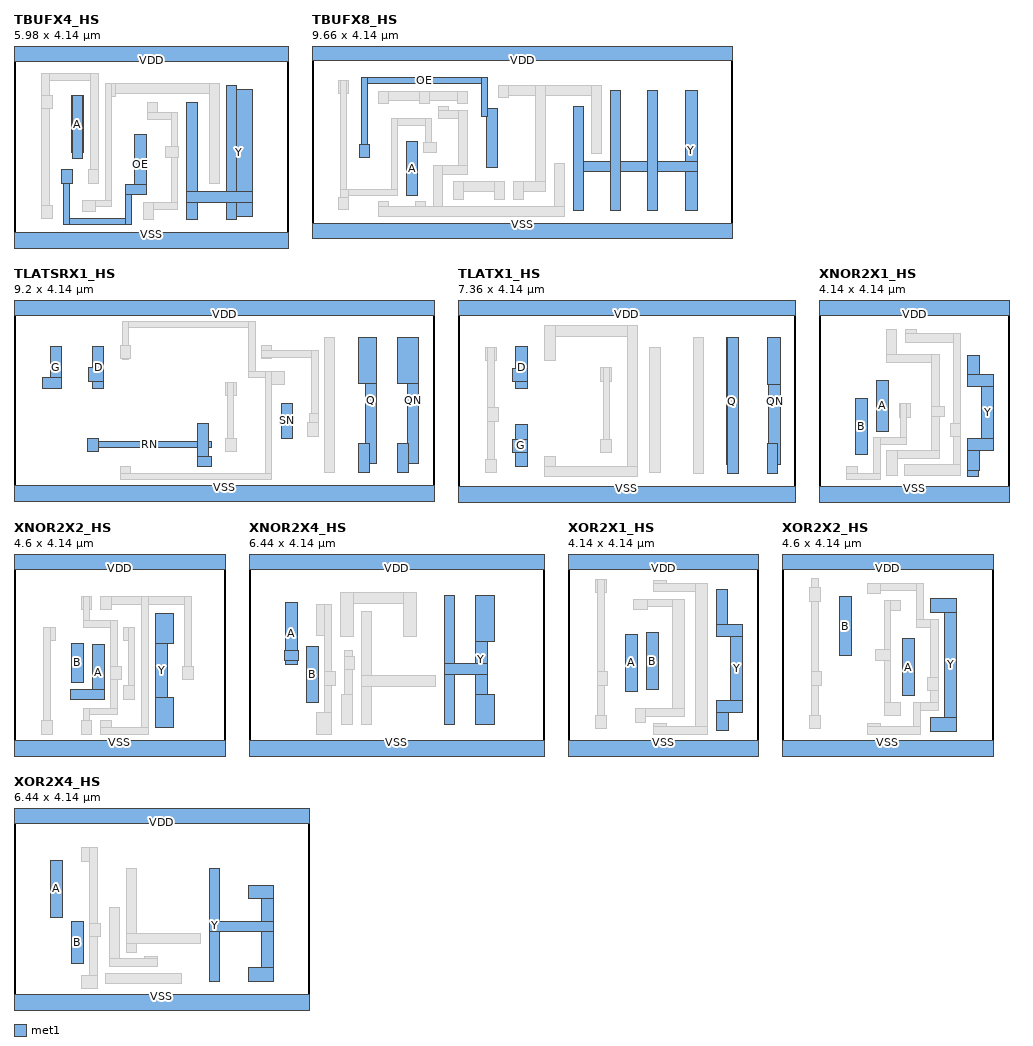
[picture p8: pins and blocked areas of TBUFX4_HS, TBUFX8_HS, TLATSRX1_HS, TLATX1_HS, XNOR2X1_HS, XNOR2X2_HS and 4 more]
MACRO TBUFX4_HS
  CLASS CORE ;
  ORIGIN 0 0 ;
  FOREIGN TBUFX4_HS 0 0 ;
  SIZE 5.98 BY 4.14 ;
  SYMMETRY X Y ;
  SITE CoreSite ;
  PIN A
    DIRECTION INPUT ;
    USE SIGNAL ;
    ANTENNAMODEL OXIDE1 ;
      ANTENNAGATEAREA 0.666 LAYER met1 ;
      ANTENNAMAXAREACAR 0.670045 LAYER met1 ;
      ANTENNAMAXSIDEAREACAR 0.635135 LAYER met1 ;
    PORT
      LAYER met1 ;
        RECT 1.25 1.95 1.51 3.19 ;
        RECT 1.265 1.815 1.495 3.19 ;
    END
  END A
  PIN OE
    DIRECTION INPUT ;
    USE SIGNAL ;
    ANTENNAMODEL OXIDE1 ;
      ANTENNAGATEAREA 0.51375 LAYER met1 ;
      ANTENNAMAXAREACAR 0.663071 LAYER met1 ;
      ANTENNAMAXSIDEAREACAR 0.780083 LAYER met1 ;
    PORT
      LAYER met1 ;
        RECT 2.63 1.025 2.89 2.35 ;
        RECT 2.43 1.025 2.89 1.255 ;
        RECT 2.43 0.375 2.57 1.255 ;
        RECT 1.08 0.375 2.57 0.515 ;
        RECT 1.035 1.285 1.265 1.575 ;
        RECT 1.08 0.375 1.22 1.575 ;
    END
  END OE
  PIN VDD
    DIRECTION INPUT ;
    USE POWER ;
    SHAPE ABUTMENT ;
    NETEXPR "VDD VDD!" ;
    PORT
      LAYER met1 ;
        RECT 0 3.94 5.98 4.34 ;
    END
  END VDD
  PIN VSS
    DIRECTION INPUT ;
    USE GROUND ;
    SHAPE ABUTMENT ;
    NETEXPR "VSS VSS!" ;
    PORT
      LAYER met1 ;
        RECT 0 -0.2 5.98 0.2 ;
    END
  END VSS
  PIN Y
    DIRECTION OUTPUT ;
    USE SIGNAL ;
    ANTENNADIFFAREA 1.2432 LAYER met1 ;
    PORT
      LAYER met1 ;
        RECT 4.625 0.56 5.19 3.33 ;
        RECT 4.625 0.485 4.855 3.405 ;
        RECT 3.765 0.865 5.19 1.095 ;
        RECT 3.765 0.485 3.995 3.045 ;
    END
  END Y
  OBS
    LAYER met1 ;
      RECT 1.985 3.225 4.485 3.455 ;
      RECT 4.255 1.285 4.485 3.455 ;
      RECT 1.985 3.165 2.215 3.455 ;
      RECT 1.985 0.775 2.125 3.455 ;
      RECT 1.495 0.775 2.125 0.915 ;
      RECT 1.495 0.655 1.785 0.915 ;
      RECT 2.905 2.68 3.135 3.045 ;
      RECT 2.905 2.68 3.565 2.82 ;
      RECT 3.425 0.71 3.565 2.82 ;
      RECT 3.305 1.845 3.595 2.075 ;
      RECT 2.815 0.71 3.565 0.85 ;
      RECT 2.815 0.485 3.045 0.85 ;
      RECT 0.605 3.51 1.845 3.68 ;
      RECT 1.675 1.285 1.845 3.68 ;
      RECT 0.605 0.51 0.775 3.68 ;
      RECT 0.605 2.9 0.835 3.19 ;
      RECT 1.615 1.285 1.845 1.575 ;
      RECT 0.605 0.51 0.835 0.8 ;
  END
  PROPERTY CatenaDesignType "deviceLevel" ;
END TBUFX4_HS

MACRO TBUFX8_HS
  CLASS CORE ;
  ORIGIN 0 0 ;
  FOREIGN TBUFX8_HS 0 0 ;
  SIZE 9.66 BY 4.14 ;
  SYMMETRY X Y ;
  SITE CoreSite ;
  PIN A
    DIRECTION INPUT ;
    USE SIGNAL ;
    ANTENNAMODEL OXIDE1 ;
      ANTENNAGATEAREA 1.332 LAYER met1 ;
      ANTENNAMAXAREACAR 0.426914 LAYER met1 ;
      ANTENNAMAXSIDEAREACAR 0.425676 LAYER met1 ;
    PORT
      LAYER met1 ;
        RECT 2.17 0.845 2.43 2.085 ;
    END
  END A
  PIN OE
    DIRECTION INPUT ;
    USE SIGNAL ;
    ANTENNAMODEL OXIDE1 ;
      ANTENNAGATEAREA 0.84675 LAYER met1 ;
      ANTENNAMAXAREACAR 0.799447 LAYER met1 ;
      ANTENNAMAXSIDEAREACAR 0.940526 LAYER met1 ;
    PORT
      LAYER met1 ;
        RECT 4.01 1.485 4.27 2.845 ;
        RECT 1.135 3.42 4.03 3.56 ;
        RECT 3.89 2.66 4.03 3.56 ;
        RECT 1.09 1.725 1.32 2.015 ;
        RECT 1.135 1.725 1.275 3.56 ;
    END
  END OE
  PIN VDD
    DIRECTION INPUT ;
    USE POWER ;
    SHAPE ABUTMENT ;
    NETEXPR "VDD VDD!" ;
    PORT
      LAYER met1 ;
        RECT 0 3.94 9.66 4.34 ;
    END
  END VDD
  PIN VSS
    DIRECTION INPUT ;
    USE GROUND ;
    SHAPE ABUTMENT ;
    NETEXPR "VSS VSS!" ;
    PORT
      LAYER met1 ;
        RECT 0 -0.2 9.66 0.2 ;
    END
  END VSS
  PIN Y
    DIRECTION OUTPUT ;
    USE SIGNAL ;
    ANTENNADIFFAREA 2.4864 LAYER met1 ;
    PORT
      LAYER met1 ;
        RECT 8.585 0.485 8.87 3.255 ;
        RECT 6.005 1.385 8.87 1.615 ;
        RECT 7.725 0.485 7.955 3.255 ;
        RECT 6.865 0.485 7.095 3.255 ;
        RECT 6.005 0.485 6.235 2.895 ;
    END
  END Y
  OBS
    LAYER met1 ;
      RECT 4.285 3.15 6.665 3.38 ;
      RECT 6.435 1.805 6.665 3.38 ;
      RECT 5.145 0.925 5.375 3.38 ;
      RECT 4.285 3.09 4.515 3.38 ;
      RECT 4.625 0.925 5.375 1.155 ;
      RECT 4.625 0.75 4.855 1.155 ;
      RECT 2.905 2.605 3.135 2.895 ;
      RECT 2.905 2.605 3.58 2.805 ;
      RECT 3.38 1.33 3.58 2.805 ;
      RECT 5.575 0.36 5.805 1.575 ;
      RECT 2.8 1.33 3.58 1.53 ;
      RECT 2.8 0.36 3 1.53 ;
      RECT 2.385 0.36 2.615 0.705 ;
      RECT 1.525 0.36 1.755 0.705 ;
      RECT 1.525 0.36 5.805 0.59 ;
      RECT 3.245 0.93 4.425 1.16 ;
      RECT 4.195 0.75 4.425 1.16 ;
      RECT 3.245 0.75 3.475 1.16 ;
      RECT 1.525 3.035 3.565 3.235 ;
      RECT 3.335 2.945 3.565 3.235 ;
      RECT 2.475 2.945 2.705 3.235 ;
      RECT 1.525 2.945 1.755 3.235 ;
      RECT 0.605 3.195 0.835 3.485 ;
      RECT 0.645 0.51 0.785 3.485 ;
      RECT 1.835 2.46 2.755 2.6 ;
      RECT 2.615 1.835 2.755 2.6 ;
      RECT 1.835 0.845 1.975 2.6 ;
      RECT 2.57 1.835 2.86 2.065 ;
      RECT 0.645 0.845 1.975 0.985 ;
      RECT 0.645 0.51 0.835 0.985 ;
      RECT 0.605 0.51 0.835 0.8 ;
  END
  PROPERTY CatenaDesignType "deviceLevel" ;
END TBUFX8_HS

MACRO TLATSRX1_HS
  CLASS CORE ;
  ORIGIN 0 0 ;
  FOREIGN TLATSRX1_HS 0 0 ;
  SIZE 9.2 BY 4.14 ;
  SYMMETRY X Y ;
  SITE CoreSite ;
  PIN D
    DIRECTION INPUT ;
    USE SIGNAL ;
    ANTENNAMODEL OXIDE1 ;
      ANTENNAGATEAREA 0.18075 LAYER met1 ;
      ANTENNAMAXAREACAR 0.780636 LAYER met1 ;
      ANTENNAMAXSIDEAREACAR 0.918396 LAYER met1 ;
    PORT
      LAYER met1 ;
        RECT 1.71 2.34 1.97 3.255 ;
        RECT 1.625 2.495 1.97 2.785 ;
    END
  END D
  PIN G
    DIRECTION INPUT ;
    USE SIGNAL ;
    ANTENNAMODEL OXIDE1 ;
      ANTENNAGATEAREA 0.18075 LAYER met1 ;
      ANTENNAMAXAREACAR 0.470263 LAYER met1 ;
      ANTENNAMAXSIDEAREACAR 0.55325 LAYER met1 ;
    PORT
      LAYER met1 ;
        RECT 0.79 2.34 1.05 3.255 ;
        RECT 0.635 2.34 1.05 2.57 ;
    END
  END G
  PIN Q
    DIRECTION OUTPUT ;
    USE SIGNAL ;
    ANTENNADIFFAREA 0.5883 LAYER met1 ;
    PORT
      LAYER met1 ;
        RECT 7.55 2.44 7.95 3.45 ;
        RECT 7.69 0.68 7.95 3.45 ;
        RECT 7.55 0.485 7.78 1.135 ;
    END
  END Q
  PIN QN
    DIRECTION OUTPUT ;
    USE SIGNAL ;
    ANTENNADIFFAREA 0.5883 LAYER met1 ;
    PORT
      LAYER met1 ;
        RECT 8.41 2.44 8.87 3.45 ;
        RECT 8.61 0.68 8.87 3.45 ;
        RECT 8.41 0.485 8.64 1.135 ;
    END
  END QN
  PIN RN
    DIRECTION INPUT ;
    USE SIGNAL ;
    ANTENNAMODEL OXIDE1 ;
      ANTENNAGATEAREA 0.3615 LAYER met1 ;
      ANTENNAMAXAREACAR 0.874689 LAYER met1 ;
      ANTENNAMAXSIDEAREACAR 1.029046 LAYER met1 ;
    PORT
      LAYER met1 ;
        RECT 1.61 1.03 4.32 1.17 ;
        RECT 4.01 0.62 4.32 0.85 ;
        RECT 4.01 0.62 4.27 1.575 ;
        RECT 1.61 0.95 1.84 1.24 ;
    END
  END RN
  PIN SN
    DIRECTION INPUT ;
    USE SIGNAL ;
    ANTENNAMODEL OXIDE1 ;
      ANTENNAGATEAREA 0.18075 LAYER met1 ;
      ANTENNAMAXAREACAR 1.321438 LAYER met1 ;
      ANTENNAMAXSIDEAREACAR 1.554633 LAYER met1 ;
    PORT
      LAYER met1 ;
        RECT 5.85 1.235 6.11 2.01 ;
    END
  END SN
  PIN VDD
    DIRECTION INPUT ;
    USE POWER ;
    SHAPE ABUTMENT ;
    NETEXPR "VDD VDD!" ;
    PORT
      LAYER met1 ;
        RECT 0 3.94 9.2 4.34 ;
    END
  END VDD
  PIN VSS
    DIRECTION INPUT ;
    USE GROUND ;
    SHAPE ABUTMENT ;
    NETEXPR "VSS VSS!" ;
    PORT
      LAYER met1 ;
        RECT 0 -0.2 9.2 0.2 ;
    END
  END VSS
  OBS
    LAYER met1 ;
      RECT 5.42 2.985 5.65 3.275 ;
      RECT 5.42 3.02 6.66 3.16 ;
      RECT 6.52 1.29 6.66 3.16 ;
      RECT 6.475 1.29 6.66 1.775 ;
      RECT 6.43 1.29 6.66 1.58 ;
      RECT 2.37 3.66 5.28 3.8 ;
      RECT 5.14 2.57 5.28 3.8 ;
      RECT 2.37 2.97 2.51 3.8 ;
      RECT 2.325 2.985 2.555 3.275 ;
      RECT 5.14 2.57 5.925 2.71 ;
      RECT 5.51 2.42 5.925 2.71 ;
      RECT 5.51 0.34 5.65 2.71 ;
      RECT 2.325 0.34 2.555 0.63 ;
      RECT 2.325 0.34 5.65 0.48 ;
      RECT 4.64 2.185 4.87 2.475 ;
      RECT 4.675 0.95 4.815 2.475 ;
      RECT 4.64 0.95 4.87 1.24 ;
      RECT 6.8 0.485 7.03 3.45 ;
  END
  PROPERTY CatenaDesignType "deviceLevel" ;
END TLATSRX1_HS

MACRO TLATX1_HS
  CLASS CORE ;
  ORIGIN 0 0 ;
  FOREIGN TLATX1_HS 0 0 ;
  SIZE 7.36 BY 4.14 ;
  SYMMETRY X Y ;
  SITE CoreSite ;
  PIN D
    DIRECTION INPUT ;
    USE SIGNAL ;
    ANTENNAMODEL OXIDE1 ;
      ANTENNAGATEAREA 0.18075 LAYER met1 ;
      ANTENNAMAXAREACAR 0.780636 LAYER met1 ;
      ANTENNAMAXSIDEAREACAR 0.918396 LAYER met1 ;
    PORT
      LAYER met1 ;
        RECT 1.25 2.34 1.51 3.255 ;
        RECT 1.195 2.495 1.51 2.785 ;
    END
  END D
  PIN G
    DIRECTION INPUT ;
    USE SIGNAL ;
    ANTENNAMODEL OXIDE1 ;
      ANTENNAGATEAREA 0.18075 LAYER met1 ;
      ANTENNAMAXAREACAR 0.874689 LAYER met1 ;
      ANTENNAMAXSIDEAREACAR 1.029046 LAYER met1 ;
    PORT
      LAYER met1 ;
        RECT 1.25 0.635 1.51 1.555 ;
        RECT 1.18 0.95 1.51 1.24 ;
    END
  END G
  PIN Q
    DIRECTION OUTPUT ;
    USE SIGNAL ;
    ANTENNADIFFAREA 0.5883 LAYER met1 ;
    PORT
      LAYER met1 ;
        RECT 5.85 0.68 6.11 3.45 ;
        RECT 5.875 0.485 6.105 3.45 ;
    END
  END Q
  PIN QN
    DIRECTION OUTPUT ;
    USE SIGNAL ;
    ANTENNADIFFAREA 0.5883 LAYER met1 ;
    PORT
      LAYER met1 ;
        RECT 6.735 2.44 7.03 3.45 ;
        RECT 6.77 0.68 7.03 3.45 ;
        RECT 6.735 0.485 6.965 1.135 ;
    END
  END QN
  PIN VDD
    DIRECTION INPUT ;
    USE POWER ;
    SHAPE ABUTMENT ;
    NETEXPR "VDD VDD!" ;
    PORT
      LAYER met1 ;
        RECT 0 3.94 7.36 4.34 ;
    END
  END VDD
  PIN VSS
    DIRECTION INPUT ;
    USE GROUND ;
    SHAPE ABUTMENT ;
    NETEXPR "VSS VSS!" ;
    PORT
      LAYER met1 ;
        RECT 0 -0.2 7.36 0.2 ;
    END
  END VSS
  OBS
    LAYER met1 ;
      RECT 1.895 3.485 3.92 3.715 ;
      RECT 3.69 0.415 3.92 3.715 ;
      RECT 1.895 2.945 2.125 3.715 ;
      RECT 1.895 0.415 2.125 0.85 ;
      RECT 1.895 0.415 3.92 0.645 ;
      RECT 3.105 2.505 3.335 2.795 ;
      RECT 3.16 0.95 3.3 2.795 ;
      RECT 3.105 0.95 3.335 1.24 ;
      RECT 0.605 2.945 0.835 3.235 ;
      RECT 0.65 0.51 0.79 3.235 ;
      RECT 0.65 1.63 0.88 1.92 ;
      RECT 0.605 0.51 0.835 0.8 ;
      RECT 5.125 0.485 5.355 3.45 ;
      RECT 4.175 0.51 4.405 3.235 ;
  END
  PROPERTY CatenaDesignType "deviceLevel" ;
END TLATX1_HS

MACRO XNOR2X1_HS
  CLASS CORE ;
  ORIGIN 0 0 ;
  FOREIGN XNOR2X1_HS 0 0 ;
  SIZE 4.14 BY 4.14 ;
  SYMMETRY X Y ;
  SITE CoreSite ;
  PIN A
    DIRECTION INPUT ;
    USE SIGNAL ;
    ANTENNAMODEL OXIDE1 ;
      ANTENNAGATEAREA 0.18075 LAYER met1 ;
      ANTENNAMAXAREACAR 0.540802 LAYER met1 ;
      ANTENNAMAXSIDEAREACAR 0.636238 LAYER met1 ;
    PORT
      LAYER met1 ;
        RECT 1.25 1.41 1.51 2.525 ;
    END
  END A
  PIN B
    DIRECTION INPUT ;
    USE SIGNAL ;
    ANTENNAMODEL OXIDE1 ;
      ANTENNAGATEAREA 0.3615 LAYER met1 ;
      ANTENNAMAXAREACAR 1.87823 LAYER met1 ;
      ANTENNAMAXSIDEAREACAR 1.770401 LAYER met1 ;
    PORT
      LAYER met1 ;
        RECT 0.79 0.895 1.05 2.135 ;
    END
  END B
  PIN VDD
    DIRECTION INPUT ;
    USE POWER ;
    SHAPE ABUTMENT ;
    NETEXPR "VDD VDD!" ;
    PORT
      LAYER met1 ;
        RECT 0 3.94 4.14 4.34 ;
    END
  END VDD
  PIN VSS
    DIRECTION INPUT ;
    USE GROUND ;
    SHAPE ABUTMENT ;
    NETEXPR "VSS VSS!" ;
    PORT
      LAYER met1 ;
        RECT 0 -0.2 4.14 0.2 ;
    END
  END VSS
  PIN Y
    DIRECTION OUTPUT ;
    USE SIGNAL ;
    ANTENNADIFFAREA 0.5883 LAYER met1 ;
    PORT
      LAYER met1 ;
        RECT 3.23 2.38 3.81 2.64 ;
        RECT 3.55 0.995 3.81 2.64 ;
        RECT 3.23 0.995 3.81 1.255 ;
        RECT 3.23 2.38 3.49 3.07 ;
        RECT 3.23 0.55 3.49 1.255 ;
        RECT 3.245 0.42 3.475 1.255 ;
    END
  END Y
  OBS
    LAYER met1 ;
      RECT 1.895 3.345 2.125 3.635 ;
      RECT 1.895 3.345 3.09 3.535 ;
      RECT 2.92 0.45 3.09 3.535 ;
      RECT 2.86 1.3 3.09 1.59 ;
      RECT 1.865 0.45 3.09 0.68 ;
      RECT 1.465 2.915 1.695 3.635 ;
      RECT 1.465 2.915 2.615 3.085 ;
      RECT 2.445 0.82 2.615 3.085 ;
      RECT 2.445 1.725 2.735 1.955 ;
      RECT 1.47 0.82 2.615 0.99 ;
      RECT 1.47 0.45 1.7 0.99 ;
      RECT 1.76 1.715 1.99 2.005 ;
      RECT 1.77 1.13 1.91 2.005 ;
      RECT 1.19 1.13 1.91 1.27 ;
      RECT 1.19 0.35 1.33 1.27 ;
      RECT 0.605 0.35 0.835 0.64 ;
      RECT 0.605 0.35 1.33 0.49 ;
  END
  PROPERTY CatenaDesignType "deviceLevel" ;
END XNOR2X1_HS

MACRO XNOR2X2_HS
  CLASS CORE ;
  ORIGIN 0 0 ;
  FOREIGN XNOR2X2_HS 0 0 ;
  SIZE 4.6 BY 4.14 ;
  SYMMETRY X Y ;
  SITE CoreSite ;
  PIN A
    DIRECTION INPUT ;
    USE SIGNAL ;
    ANTENNAMODEL OXIDE1 ;
      ANTENNAGATEAREA 0.18075 LAYER met1 ;
      ANTENNAMAXAREACAR 0.503181 LAYER met1 ;
      ANTENNAMAXSIDEAREACAR 0.591978 LAYER met1 ;
    PORT
      LAYER met1 ;
        RECT 1.71 1.09 1.97 2.295 ;
        RECT 1.235 1.09 1.97 1.32 ;
    END
  END A
  PIN B
    DIRECTION INPUT ;
    USE SIGNAL ;
    ANTENNAMODEL OXIDE1 ;
      ANTENNAGATEAREA 0.3615 LAYER met1 ;
      ANTENNAMAXAREACAR 0.764177 LAYER met1 ;
      ANTENNAMAXSIDEAREACAR 0.804979 LAYER met1 ;
    PORT
      LAYER met1 ;
        RECT 1.25 1.48 1.51 2.33 ;
    END
  END B
  PIN VDD
    DIRECTION INPUT ;
    USE POWER ;
    SHAPE ABUTMENT ;
    NETEXPR "VDD VDD!" ;
    PORT
      LAYER met1 ;
        RECT 0 3.94 4.6 4.34 ;
    END
  END VDD
  PIN VSS
    DIRECTION INPUT ;
    USE GROUND ;
    SHAPE ABUTMENT ;
    NETEXPR "VSS VSS!" ;
    PORT
      LAYER met1 ;
        RECT 0 -0.2 4.6 0.2 ;
    END
  END VSS
  PIN Y
    DIRECTION OUTPUT ;
    USE SIGNAL ;
    ANTENNADIFFAREA 0.6216 LAYER met1 ;
    PORT
      LAYER met1 ;
        RECT 3.09 2.32 3.475 2.97 ;
        RECT 3.09 0.49 3.475 1.14 ;
        RECT 3.09 0.49 3.35 2.97 ;
    END
  END Y
  OBS
    LAYER met1 ;
      RECT 1.895 3.18 3.875 3.35 ;
      RECT 3.705 1.53 3.875 3.35 ;
      RECT 2.78 0.345 2.92 3.35 ;
      RECT 1.895 3.06 2.125 3.35 ;
      RECT 3.675 1.53 3.905 1.82 ;
      RECT 1.895 0.345 2.125 0.635 ;
      RECT 1.895 0.345 2.92 0.485 ;
      RECT 2.395 2.385 2.625 2.675 ;
      RECT 2.485 1.105 2.625 2.675 ;
      RECT 2.395 1.105 2.625 1.395 ;
      RECT 1.465 3.06 1.695 3.35 ;
      RECT 1.51 2.68 1.65 3.35 ;
      RECT 1.51 2.68 2.25 2.82 ;
      RECT 2.11 0.775 2.25 2.82 ;
      RECT 2.11 1.535 2.34 1.825 ;
      RECT 1.51 0.775 2.25 0.915 ;
      RECT 1.51 0.345 1.65 0.915 ;
      RECT 1.465 0.345 1.695 0.635 ;
      RECT 0.635 2.385 0.915 2.675 ;
      RECT 0.635 0.345 0.805 2.675 ;
      RECT 0.605 0.345 0.835 0.635 ;
  END
  PROPERTY CatenaDesignType "deviceLevel" ;
END XNOR2X2_HS

MACRO XNOR2X4_HS
  CLASS CORE ;
  ORIGIN 0 0 ;
  FOREIGN XNOR2X4_HS 0 0 ;
  SIZE 6.44 BY 4.14 ;
  SYMMETRY X Y ;
  SITE CoreSite ;
  PIN A
    DIRECTION INPUT ;
    USE SIGNAL ;
    ANTENNAMODEL OXIDE1 ;
      ANTENNAGATEAREA 0.18075 LAYER met1 ;
      ANTENNAMAXAREACAR 0.470263 LAYER met1 ;
      ANTENNAMAXSIDEAREACAR 0.55325 LAYER met1 ;
    PORT
      LAYER met1 ;
        RECT 0.78 1.945 1.07 2.175 ;
        RECT 0.79 1.855 1.05 3.205 ;
    END
  END A
  PIN B
    DIRECTION INPUT ;
    USE SIGNAL ;
    ANTENNAMODEL OXIDE1 ;
      ANTENNAGATEAREA 0.51375 LAYER met1 ;
      ANTENNAMAXAREACAR 0.350754 LAYER met1 ;
      ANTENNAMAXSIDEAREACAR 0.346472 LAYER met1 ;
    PORT
      LAYER met1 ;
        RECT 1.25 1.03 1.51 2.265 ;
    END
  END B
  PIN VDD
    DIRECTION INPUT ;
    USE POWER ;
    SHAPE ABUTMENT ;
    NETEXPR "VDD VDD!" ;
    PORT
      LAYER met1 ;
        RECT 0 3.94 6.44 4.34 ;
    END
  END VDD
  PIN VSS
    DIRECTION INPUT ;
    USE GROUND ;
    SHAPE ABUTMENT ;
    NETEXPR "VSS VSS!" ;
    PORT
      LAYER met1 ;
        RECT 0 -0.2 6.44 0.2 ;
    END
  END VSS
  PIN Y
    DIRECTION OUTPUT ;
    USE SIGNAL ;
    ANTENNADIFFAREA 1.2432 LAYER met1 ;
    PORT
      LAYER met1 ;
        RECT 4.93 2.365 5.345 3.375 ;
        RECT 4.93 0.56 5.345 1.21 ;
        RECT 4.93 0.56 5.19 3.375 ;
        RECT 4.255 1.65 5.19 1.88 ;
        RECT 4.255 0.56 4.485 3.375 ;
    END
  END Y
  OBS
    LAYER met1 ;
      RECT 2.445 0.56 2.675 3.015 ;
      RECT 2.445 1.39 4.055 1.62 ;
      RECT 1.985 3.195 3.655 3.425 ;
      RECT 3.365 2.475 3.655 3.425 ;
      RECT 1.985 2.475 2.275 3.425 ;
      RECT 2.075 0.56 2.245 2.17 ;
      RECT 2.075 1.755 2.305 2.045 ;
      RECT 2.015 0.56 2.245 1.21 ;
      RECT 1.465 2.49 1.79 3.16 ;
      RECT 1.65 0.345 1.79 3.16 ;
      RECT 1.65 1.415 1.88 1.705 ;
      RECT 1.465 0.345 1.79 0.82 ;
  END
  PROPERTY CatenaDesignType "deviceLevel" ;
END XNOR2X4_HS

MACRO XOR2X1_HS
  CLASS CORE ;
  ORIGIN 0 0 ;
  FOREIGN XOR2X1_HS 0 0 ;
  SIZE 4.14 BY 4.14 ;
  SYMMETRY X Y ;
  SITE CoreSite ;
  PIN A
    DIRECTION INPUT ;
    USE SIGNAL ;
    ANTENNAMODEL OXIDE1 ;
      ANTENNAGATEAREA 0.18075 LAYER met1 ;
      ANTENNAMAXAREACAR 0.606639 LAYER met1 ;
      ANTENNAMAXSIDEAREACAR 0.713693 LAYER met1 ;
    PORT
      LAYER met1 ;
        RECT 1.25 1.285 1.51 2.525 ;
    END
  END A
  PIN B
    DIRECTION INPUT ;
    USE SIGNAL ;
    ANTENNAMODEL OXIDE1 ;
      ANTENNAGATEAREA 0.3615 LAYER met1 ;
      ANTENNAMAXAREACAR 1.795934 LAYER met1 ;
      ANTENNAMAXSIDEAREACAR 1.767635 LAYER met1 ;
    PORT
      LAYER met1 ;
        RECT 1.71 1.31 1.97 2.55 ;
    END
  END B
  PIN VDD
    DIRECTION INPUT ;
    USE POWER ;
    SHAPE ABUTMENT ;
    NETEXPR "VDD VDD!" ;
    PORT
      LAYER met1 ;
        RECT 0 3.94 4.14 4.34 ;
    END
  END VDD
  PIN VSS
    DIRECTION INPUT ;
    USE GROUND ;
    SHAPE ABUTMENT ;
    NETEXPR "VSS VSS!" ;
    PORT
      LAYER met1 ;
        RECT 0 -0.2 4.14 0.2 ;
    END
  END VSS
  PIN Y
    DIRECTION OUTPUT ;
    USE SIGNAL ;
    ANTENNADIFFAREA 0.5883 LAYER met1 ;
    PORT
      LAYER met1 ;
        RECT 3.245 2.48 3.81 2.74 ;
        RECT 3.55 0.81 3.81 2.74 ;
        RECT 3.23 0.81 3.81 1.07 ;
        RECT 3.23 0.42 3.49 1.07 ;
        RECT 3.245 2.48 3.475 3.49 ;
    END
  END Y
  OBS
    LAYER met1 ;
      RECT 1.865 3.46 2.155 3.69 ;
      RECT 1.865 3.46 3.03 3.63 ;
      RECT 2.77 0.34 3.03 3.63 ;
      RECT 1.865 0.34 2.155 0.57 ;
      RECT 1.865 0.34 3.03 0.51 ;
      RECT 1.435 3.12 2.535 3.29 ;
      RECT 2.275 0.74 2.535 3.29 ;
      RECT 1.435 3.06 1.725 3.29 ;
      RECT 1.465 0.74 2.535 0.91 ;
      RECT 1.465 0.59 1.695 0.91 ;
      RECT 0.605 3.435 0.835 3.725 ;
      RECT 0.635 0.46 0.805 3.725 ;
      RECT 0.635 1.415 0.865 1.705 ;
      RECT 0.605 0.46 0.835 0.75 ;
  END
  PROPERTY CatenaDesignType "deviceLevel" ;
END XOR2X1_HS

MACRO XOR2X2_HS
  CLASS CORE ;
  ORIGIN 0 0 ;
  FOREIGN XOR2X2_HS 0 0 ;
  SIZE 4.6 BY 4.14 ;
  SYMMETRY X Y ;
  SITE CoreSite ;
  PIN A
    DIRECTION INPUT ;
    USE SIGNAL ;
    ANTENNAMODEL OXIDE1 ;
      ANTENNAGATEAREA 0.18075 LAYER met1 ;
      ANTENNAMAXAREACAR 0.512586 LAYER met1 ;
      ANTENNAMAXSIDEAREACAR 0.603043 LAYER met1 ;
    PORT
      LAYER met1 ;
        RECT 2.63 1.18 2.89 2.42 ;
    END
  END A
  PIN B
    DIRECTION INPUT ;
    USE SIGNAL ;
    ANTENNAMODEL OXIDE1 ;
      ANTENNAGATEAREA 0.3615 LAYER met1 ;
      ANTENNAMAXAREACAR 1.821798 LAYER met1 ;
      ANTENNAMAXSIDEAREACAR 1.798064 LAYER met1 ;
    PORT
      LAYER met1 ;
        RECT 1.25 2.055 1.51 3.345 ;
    END
  END B
  PIN VDD
    DIRECTION INPUT ;
    USE POWER ;
    SHAPE ABUTMENT ;
    NETEXPR "VDD VDD!" ;
    PORT
      LAYER met1 ;
        RECT 0 3.94 4.6 4.34 ;
    END
  END VDD
  PIN VSS
    DIRECTION INPUT ;
    USE GROUND ;
    SHAPE ABUTMENT ;
    NETEXPR "VSS VSS!" ;
    PORT
      LAYER met1 ;
        RECT 0 -0.2 4.6 0.2 ;
    END
  END VSS
  PIN Y
    DIRECTION OUTPUT ;
    USE SIGNAL ;
    ANTENNADIFFAREA 0.6216 LAYER met1 ;
    PORT
      LAYER met1 ;
        RECT 3.23 3.005 3.81 3.3 ;
        RECT 3.55 0.41 3.81 3.3 ;
        RECT 3.23 0.41 3.81 0.705 ;
    END
  END Y
  OBS
    LAYER met1 ;
      RECT 1.865 3.465 3.09 3.635 ;
      RECT 2.92 2.68 3.09 3.635 ;
      RECT 1.865 3.405 2.155 3.635 ;
      RECT 2.92 2.68 3.41 2.85 ;
      RECT 3.24 0.87 3.41 2.85 ;
      RECT 3.18 1.29 3.41 1.58 ;
      RECT 2.855 0.87 3.41 1.04 ;
      RECT 2.855 0.34 3.025 1.04 ;
      RECT 1.865 0.34 2.155 0.57 ;
      RECT 1.865 0.34 3.025 0.51 ;
      RECT 2.23 3.035 2.585 3.265 ;
      RECT 2.23 0.75 2.37 3.265 ;
      RECT 2.04 1.95 2.37 2.18 ;
      RECT 2.23 0.75 2.585 1.04 ;
      RECT 0.635 0.46 0.805 3.73 ;
      RECT 0.605 3.245 0.835 3.535 ;
      RECT 0.635 1.415 0.865 1.705 ;
      RECT 0.605 0.46 0.835 0.75 ;
  END
  PROPERTY CatenaDesignType "deviceLevel" ;
END XOR2X2_HS

MACRO XOR2X4_HS
  CLASS CORE ;
  ORIGIN 0 0 ;
  FOREIGN XOR2X4_HS 0 0 ;
  SIZE 6.44 BY 4.14 ;
  SYMMETRY X Y ;
  SITE CoreSite ;
  PIN A
    DIRECTION INPUT ;
    USE SIGNAL ;
    ANTENNAMODEL OXIDE1 ;
      ANTENNAGATEAREA 0.18075 LAYER met1 ;
      ANTENNAMAXAREACAR 0.545505 LAYER met1 ;
      ANTENNAMAXSIDEAREACAR 0.64177 LAYER met1 ;
    PORT
      LAYER met1 ;
        RECT 0.79 1.895 1.05 3.135 ;
    END
  END A
  PIN B
    DIRECTION INPUT ;
    USE SIGNAL ;
    ANTENNAMODEL OXIDE1 ;
      ANTENNAGATEAREA 0.51375 LAYER met1 ;
      ANTENNAMAXAREACAR 0.200195 LAYER met1 ;
      ANTENNAMAXSIDEAREACAR 0.235523 LAYER met1 ;
    PORT
      LAYER met1 ;
        RECT 1.25 0.875 1.51 1.805 ;
    END
  END B
  PIN VDD
    DIRECTION INPUT ;
    USE POWER ;
    SHAPE ABUTMENT ;
    NETEXPR "VDD VDD!" ;
    PORT
      LAYER met1 ;
        RECT 0 3.94 6.44 4.34 ;
    END
  END VDD
  PIN VSS
    DIRECTION INPUT ;
    USE GROUND ;
    SHAPE ABUTMENT ;
    NETEXPR "VSS VSS!" ;
    PORT
      LAYER met1 ;
        RECT 0 -0.2 6.44 0.2 ;
    END
  END VSS
  PIN Y
    DIRECTION OUTPUT ;
    USE SIGNAL ;
    ANTENNADIFFAREA 1.2432 LAYER met1 ;
    PORT
      LAYER met1 ;
        RECT 5.115 2.295 5.65 2.585 ;
        RECT 5.39 0.5 5.65 2.585 ;
        RECT 4.255 1.575 5.65 1.805 ;
        RECT 5.115 0.5 5.65 0.79 ;
        RECT 4.255 0.485 4.485 2.945 ;
    END
  END Y
  OBS
    LAYER met1 ;
      RECT 2.445 1.125 2.675 2.945 ;
      RECT 2.445 1.315 4.055 1.545 ;
      RECT 2.075 0.815 2.305 2.095 ;
      RECT 2.845 0.815 3.135 1.045 ;
      RECT 2.075 0.815 3.135 0.985 ;
      RECT 1.465 3.11 1.82 3.4 ;
      RECT 1.65 0.34 1.82 3.4 ;
      RECT 1.65 1.465 1.88 1.755 ;
      RECT 1.465 0.34 1.82 0.63 ;
      RECT 1.985 0.445 3.655 0.675 ;
  END
  PROPERTY CatenaDesignType "deviceLevel" ;
END XOR2X4_HS

END LIBRARY
